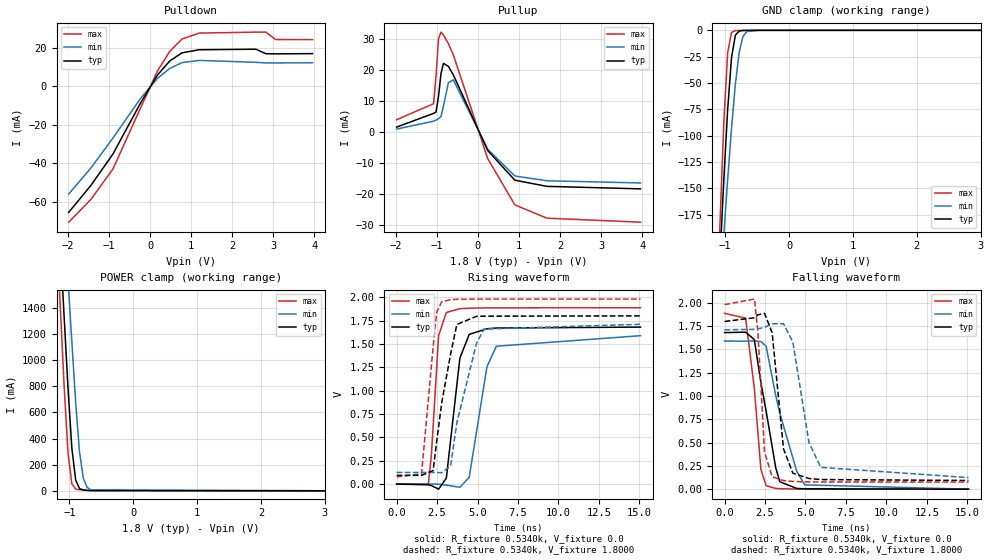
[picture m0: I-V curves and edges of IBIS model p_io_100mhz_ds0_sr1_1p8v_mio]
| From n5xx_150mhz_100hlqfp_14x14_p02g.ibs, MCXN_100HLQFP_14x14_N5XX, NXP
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[Model] p_io_100mhz_ds0_sr1_1p8v_mio
|   Model p_io_100mhz_ds0_sr1_1p8v_mio
| This model was characterised for following simulation conditions:
| External (pad) voltage:
|   - Typ: 1.8V,   - Min: 1.71V,   - Max: 1.98V
| Library cells for typ/min/max conditions are connected as defined below:
|  pad - External Pad
|  ipp_do_lv - Core Input
|  ipp_obe_lv - Output Buffer Enable
|  IOGC - NC
|  REFH3V3 - REFH3V3
|  REFL3V3 - REFL3V3
|  ZI - NC
|  abut_ncal_vddio[1] - vssio vddio vddio
|  abut_ncal_vddio[2] - vddio vddio vssio
|  abut_ncal_vddio[3] - vddio
|  abut_ncal_vddio[4] - vssio vddio vddio
|  abut_ncal_vddio[5] - vddio vddio vssio
|  abut_ncal_vddio[6] - vddio
|  abut_pcal_vddio[1] - vssio
|  abut_pcal_vddio[2] - vddio vssio vddio
|  abut_pcal_vddio[3] - vssio
|  abut_pcal_vddio[4] - vssio
|  abut_pcal_vddio[5] - vddio vssio vddio
|  abut_pcal_vddio[6] - vssio
|  ipp_do_1p8v - ipp_do_1p8v
|  ipp_dse_lv - 0
|  ipp_eftd_lv - NC
|  ipp_ina_mux_vddio - NC
|  ipp_ina_mux_vddio[0] - NC
|  ipp_ina_mux_vddio[1] - NC
|  ipp_ina_r0_vddio - NC
|  ipp_ina_r0a_vddio - NC
|  ipp_ina_r0b_vddio - NC
|  ipp_ina_r0c_vddio - NC
|  ipp_ina_r0d_vddio - NC
|  ipp_ina_r0e_vddio - NC
|  ipp_ina_r0f_vddio - NC
|  ipp_ina_r300_vddio - NC
|  ipp_ina_r300a_vddio - NC
|  ipp_ina_r300b_vddio - NC
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Model_type I/O
Polarity   Non-Inverting
Enable   Active-High
Vinl =   0.5400V
Vinh =   1.2600V
Vmeas =  0.9000V
Cref =   30.0000pF
Rref =   1.0000M
Vref =   1.8000V
C_comp   1.3623pF   1.2981pF   1.4425pF
|C_comp_pullup   0.7130pF   0.7388pF   0.6867pF
|C_comp_pulldown   0.5818pF   0.6364pF   0.5437pF
[Model Spec]
| variable   typ   min   max
Vinh   1.2600V   1.1970V   1.3860V
Vinl   0.5400V   0.5130V   0.5940V
[Temperature Range]   25.0000   0.1250k   -40.0000
[Voltage Range]   1.8000V   1.7100V   1.9800V
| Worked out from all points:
|   slope of the pulldown table from 0 to 0.27 V, typ, clamps not added: 32.1 ohm
|   slope of the pullup table from 0 to 0.27 V, typ, clamps not added: 40.8 ohm
|   GND clamp passes 1 mA (typ) near -0.79 V on its own axis
|   POWER clamp passes 1 mA (typ) near -0.56 V on its own axis
|   rising waveform, R_fixture 0.5340k, V_fixture 0.0: 20-80 % time 601ps typ, 817ps min, 376ps max; typ from 0 V to 1.68 V
|   rising waveform, R_fixture 0.5340k, V_fixture 1.8000: 20-80 % time 932ps typ, 1.21ns min, 574ps max; typ from 0.093 V to 1.8 V
|   falling waveform, R_fixture 0.5340k, V_fixture 0.0: 20-80 % time 990ps typ, 1.35ns min, 603ps max; typ from 1.68 V to 0 V
|   falling waveform, R_fixture 0.5340k, V_fixture 1.8000: 20-80 % time 546ps typ, 868ps min, 349ps max; typ from 1.8 V to 0.093 V
[Pulldown]
|Voltage   I(typ)   I(min)   I(max)
-1.98V    -65.51mA   -56mA      -70.63mA
-1.44V    -51.49mA   -42.44mA   -58.8mA
-900mV    -35.05mA   -26.74mA   -42.86mA
-240mV    -8.99mA    -6.551mA   -11.63mA
180mV     5.909mA    4.185mA    8.006mA
480mV     13.23mA    9.376mA    18.24mA
780mV     17.5mA     12.4mA     24.7mA
1.2V      19.11mA    13.55mA    27.78mA
2.58V     19.37mA    12.56mA    28.27mA
2.82V     17.04mA    12.25mA    28.29mA
3.06V     16.96mA    12.25mA    24.43mA
3.96V     17.09mA    12.34mA    24.37mA
[Pullup]
|Voltage   I(typ)   I(min)   I(max)
-1.98V    1.636mA    1mA        4.028mA
-1.08V    6.077mA    3.554mA    9.208mA
-1.02V    6.51mA     3.931mA    18.29mA
-960mV    11.61mA    4.325mA    30.19mA
-900mV    18.94mA    5.078mA    32.34mA
-840mV    22.24mA    8.431mA    31.43mA
-720mV    21.27mA    15.96mA    28.62mA
-600mV    18.54mA    16.92mA    25.03mA
240mV     -5.971mA   -5.553mA   -8.582mA
900mV     -15.52mA   -14.17mA   -23.51mA
1.68V     -17.51mA   -15.71mA   -27.79mA
3.96V     -18.32mA   -16.41mA   -29.09mA
[GND_clamp]
|Voltage   I(typ)   I(min)   I(max)
-1.98V    -1.537A    -1.19A     -2.019A
-1.14V    -294.9mA   -305.1mA   -290.2mA
-1.08V    -215.7mA   -248.6mA   -182.3mA
-1.02V    -141mA     -193.8mA   -86.65mA
-960mV    -74.83mA   -141.5mA   -21.03mA
-900mV    -25.88mA   -93.07mA   -2.012mA
-840mV    -4.609mA   -51.31mA   -311uA
-780mV    -637.2uA   -20.91mA   -159.7uA
-720mV    -151.2uA   -5.716mA   -109.9uA
-660mV    -72.83uA   -1.219mA   -73.5uA
-480mV    -11.41uA   -25.38uA   -9.438uA
3.96V     0A         0A         0A
[POWER_clamp]
|Voltage   I(typ)   I(min)   I(max)
-1.98V    9.576A     9.287A     10.07A
-1.2V     2.409A     3.037A     2.006A
-1.14V    1.864A     2.56A      1.395A
-1.08V    1.321A     2.084A     791mA
-1.02V    782.7mA    1.609A     287.5mA
-960mV    325.1mA    1.137A     54.65mA
-900mV    82.58mA    671mA      14.08mA
-840mV    18.02mA    296.8mA    8.778mA
-780mV    6.907mA    95.14mA    6.356mA
-720mV    4.149mA    25.95mA    4.381mA
-660mV    2.634mA    7.923mA    2.736mA
3.96V     0A         0A         0A
[Ramp]
| variable   typ   min   max
dV/dt_r  1.0081/0.6014n   0.9529/0.8166n   1.1320/0.3762n
dV/dt_f  1.0242/0.5458n   0.9513/0.8676n   1.1422/0.3495n
R_load = 0.5340k
[Rising Waveform]
R_fixture= 0.5340k
V_fixture= 0.0
V_fixture_min= 0.0
V_fixture_max= 0.0
|time   V(typ)   V(min)   V(max)
0s        464.8pV    171.6nV    14.01pV
1.962ns   -8.088mV   270.7uV    3.648mV
2.148ns   -15.92mV   560.3uV    309.5mV
2.593ns   -54.73mV   -902.1uV   1.59V
3.071ns   63.74mV    -11.49mV   1.836V
3.909ns   1.349V     -35.2mV    1.877V
4.486ns   1.602V     73.79mV    1.882V
5.58ns    1.662V     1.255V     1.886V
6.16ns    1.67V      1.475V     1.886V
15.07ns   1.68V      1.588V     1.887V
[Rising Waveform]
R_fixture= 0.5340k
V_fixture= 1.8000
V_fixture_min= 1.7100
V_fixture_max= 1.9800
|time   V(typ)   V(min)   V(max)
0s        92.99mV    124mV      76.26mV
1.542ns   93.33mV    124mV      109.5mV
2.256ns   144.3mV    124.2mV    1.471V
2.473ns   452.9mV    123.3mV    1.841V
2.782ns   866.6mV    121.3mV    1.95V
3.336ns   1.392V     193.3mV    1.974V
3.721ns   1.708V     656.6mV    1.977V
4.931ns   1.795V     1.504V     1.98V
5.397ns   1.797V     1.659V     1.98V
15.07ns   1.8V       1.71V      1.98V
[Falling Waveform]
R_fixture= 0.5340k
V_fixture= 0.0
V_fixture_min= 0.0
V_fixture_max= 0.0
|time   V(typ)   V(min)   V(max)
0s        1.68V      1.589V     1.887V
1.302ns   1.685V     1.588V     1.835V
1.839ns   1.605V     1.592V     1.083V
2.245ns   1.145V     1.584V     213.2mV
2.57ns    837mV      1.534V     37.51mV
3.164ns   228.2mV    1.003V     7.745mV
3.415ns   79.61mV    815.6mV    4.796mV
4.469ns   7.465mV    187.1mV    993.8uV
4.953ns   3.898mV    46.45mV    566.9uV
15.07ns   36.14uV    86.85uV    22.42uV
[Falling Waveform]
R_fixture= 0.5340k
V_fixture= 1.8000
V_fixture_min= 1.7100
V_fixture_max= 1.9800
|time   V(typ)   V(min)   V(max)
0s        1.8V       1.71V      1.98V
1.851ns   1.839V     1.715V     2.04V
2.062ns   1.871V     1.721V     1.683V
2.472ns   1.886V     1.736V     397.2mV
2.941ns   1.679V     1.775V     133.3mV
3.642ns   432.9mV    1.775V     91.6mV
4.221ns   171.9mV    1.58V      82.81mV
5.214ns   114.5mV    500.7mV    78.24mV
5.947ns   103.2mV    233.6mV    77.18mV
15.07ns   93.05mV    124.5mV    76.29mV
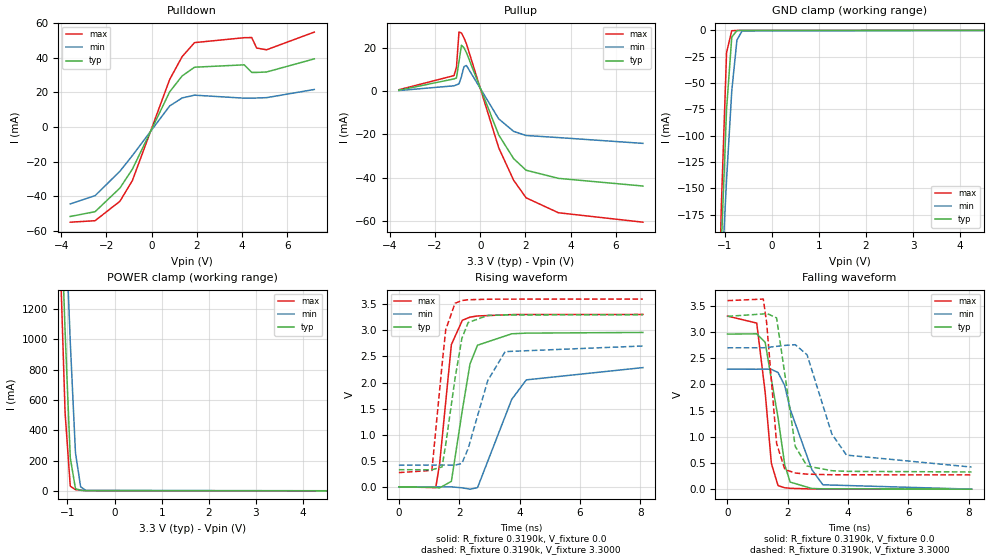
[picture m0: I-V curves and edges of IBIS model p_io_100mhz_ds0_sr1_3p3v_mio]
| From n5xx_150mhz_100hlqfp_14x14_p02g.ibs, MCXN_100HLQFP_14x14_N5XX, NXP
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[Model] p_io_100mhz_ds0_sr1_3p3v_mio
|   Model p_io_100mhz_ds0_sr1_3p3v_mio
| This model was characterised for following simulation conditions:
| External (pad) voltage:
|   - Typ: 3.3V,   - Min: 2.7V,   - Max: 3.6V
| Library cells for typ/min/max conditions are connected as defined below:
|  pad - External Pad
|  ipp_do_lv - Core Input
|  ipp_obe_lv - Output Buffer Enable
|  IOGC - NC
|  REFH3V3 - REFH3V3
|  REFL3V3 - REFL3V3
|  ZI - NC
|  abut_ncal_vddio[1] - vddio
|  abut_ncal_vddio[2] - vddio
|  abut_ncal_vddio[3] - vssio
|  abut_ncal_vddio[4] - vddio
|  abut_ncal_vddio[5] - vddio
|  abut_ncal_vddio[6] - vssio
|  abut_pcal_vddio[1] - vssio
|  abut_pcal_vddio[2] - vssio
|  abut_pcal_vddio[3] - vddio
|  abut_pcal_vddio[4] - vssio
|  abut_pcal_vddio[5] - vssio
|  abut_pcal_vddio[6] - vddio
|  ipp_do_1p8v - ipp_do_1p8v
|  ipp_dse_lv - 0
|  ipp_eftd_lv - NC
|  ipp_ina_mux_vddio - NC
|  ipp_ina_mux_vddio[0] - NC
|  ipp_ina_mux_vddio[1] - NC
|  ipp_ina_r0_vddio - NC
|  ipp_ina_r0a_vddio - NC
|  ipp_ina_r0b_vddio - NC
|  ipp_ina_r0c_vddio - NC
|  ipp_ina_r0d_vddio - NC
|  ipp_ina_r0e_vddio - NC
|  ipp_ina_r0f_vddio - NC
|  ipp_ina_r300_vddio - NC
|  ipp_ina_r300a_vddio - NC
|  ipp_ina_r300b_vddio - NC
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Model_type I/O
Polarity   Non-Inverting
Enable   Active-High
Vinl =   0.9900V
Vinh =   2.3100V
Vmeas =  1.6500V
Cref =   30.0000pF
Rref =   1.0000M
Vref =   3.3000V
C_comp   1.3234pF   1.2639pF   1.4076pF
|C_comp_pullup   0.6739pF   0.7056pF   0.6520pF
|C_comp_pulldown   0.5815pF   0.6343pF   0.5433pF
[Model Spec]
| variable   typ   min   max
Vinh   2.3100V   1.8900V   2.5200V
Vinl   0.9900V   0.8100V   1.0800V
[Temperature Range]   25.0000   0.1250k   -40.0000
[Voltage Range]   3.3000V   2.7000V   3.6000V
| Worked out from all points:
|   slope of the pulldown table from 0 to 0.495 V, typ, clamps not added: 36.6 ohm
|   slope of the pullup table from 0 to 0.495 V, typ, clamps not added: 37.7 ohm
|   GND clamp passes 1 mA (typ) near -0.75 V on its own axis
|   POWER clamp passes 1 mA (typ) near -0.55 V on its own axis
|   rising waveform, R_fixture 0.3190k, V_fixture 0.0: 20-80 % time 463ps typ, 831ps min, 328ps max; typ from 0 V to 2.96 V
|   rising waveform, R_fixture 0.3190k, V_fixture 3.3000: 20-80 % time 462ps typ, 748ps min, 321ps max; typ from 0.328 V to 3.3 V
|   falling waveform, R_fixture 0.3190k, V_fixture 0.0: 20-80 % time 473ps typ, 774ps min, 323ps max; typ from 2.96 V to 0 V
|   falling waveform, R_fixture 0.3190k, V_fixture 3.3000: 20-80 % time 407ps typ, 768ps min, 280ps max; typ from 3.3 V to 0.329 V
[Pulldown]
|Voltage   I(typ)   I(min)   I(max)
-3.6V     -51.52mA   -44.27mA   -54.81mA
-2.5V     -48.75mA   -39.51mA   -53.96mA
-1.4V     -35.12mA   -25.45mA   -42.73mA
-850mV    -24.27mA   -16.41mA   -30.84mA
800mV     20.29mA    12.16mA    27.43mA
1.35V     29.44mA    16.78mA    40.57mA
1.9V      34.5mA     18.39mA    48.67mA
4.1V      35.87mA    16.66mA    51.51mA
4.43V     31.5mA     16.69mA    51.59mA
4.65V     31.5mA     16.75mA    45.53mA
5.09V     31.75mA    16.96mA    44.55mA
7.2V      39.3mA     21.67mA    54.74mA
[Pullup]
|Voltage   I(typ)   I(min)   I(max)
-3.6V     391.8uA    234.9uA    605.7uA
-1.16V    5.604mA    2.419mA    7.14mA
-1.05V    6.055mA    2.871mA    11mA
-940mV    13.56mA    3.339mA    27.24mA
-830mV    21.15mA    6.685mA    26.82mA
-720mV    20.05mA    11.26mA    24.61mA
-610mV    17.74mA    11.81mA    21.86mA
820mV     -20.29mA   -12.86mA   -26.23mA
1.48V     -31.23mA   -18.63mA   -41.23mA
2.03V     -36.57mA   -20.53mA   -49.31mA
3.46V     -40.33mA   -21.49mA   -56.22mA
7.2V      -43.87mA   -24.17mA   -60.58mA
[GND_clamp]
|Voltage   I(typ)   I(min)   I(max)
-3.6V     -4.134A    -3.035A    -5.609A
-1.18V    -349.4mA   -343.6mA   -365.7mA
-1.07V    -202.9mA   -239.3mA   -165.2mA
-960mV    -74.83mA   -141.5mA   -21.03mA
-850mV    -6.389mA   -57.64mA   -383.3uA
-740mV    -222.1uA   -9.174mA   -124.1uA
-630mV    -55.93uA   -558.9uA   -58.07uA
7.2V      0A         0A         0A
[POWER_clamp]
|Voltage   I(typ)   I(min)   I(max)
-3.6V     24.54A     22.33A     26.93A
-1.16V    2.046A     2.721A     1.599A
-1.05V    1.052A     1.847A     514.4mA
-940mV    218.6mA    981.8mA    31.16mA
-830mV    15.1mA     252.4mA    8.462mA
-720mV    4.281mA    26.81mA    4.453mA
-610mV    1.717mA    3.626mA    1.66mA
7.2V      0A         0A         0A
[Ramp]
| variable   typ   min   max
dV/dt_r  1.7762/0.4628n   1.3718/0.8312n   1.9832/0.3278n
dV/dt_f  1.7828/0.4073n   1.3669/0.7682n   1.9962/0.2798n
R_load = 0.3190k
[Rising Waveform]
R_fixture= 0.3190k
V_fixture= 0.0
V_fixture_min= 0.0
V_fixture_max= 0.0
|time   V(typ)   V(min)   V(max)
0s        2.902nV    250nV      9.459nV
1.223ns   -10.89mV   -6.243uV   -14.66mV
1.35ns    -21.51mV   358.4uV    434mV
1.741ns   105.7mV    -947.7uV   2.727V
2.104ns   1.47V      -19.17mV   3.193V
2.36ns    2.361V     -44.72mV   3.254V
2.608ns   2.715V     -14.73mV   3.276V
3.741ns   2.934V     1.676V     3.302V
4.225ns   2.947V     2.051V     3.304V
8.09ns    2.96V      2.286V     3.305V
[Rising Waveform]
R_fixture= 0.3190k
V_fixture= 3.3000
V_fixture_min= 2.7000
V_fixture_max= 3.6000
|time   V(typ)   V(min)   V(max)
0s        328.4mV    417.4mV    273mV
1.095ns   327.1mV    417.3mV    314.8mV
1.431ns   382.2mV    418mV      2.335V
1.554ns   814mV      418.4mV    3.012V
1.861ns   2.073V     414.8mV    3.519V
2.089ns   2.846V     449mV      3.572V
2.297ns   3.149V     734.6mV    3.587V
2.946ns   3.286V     2.037V     3.597V
3.524ns   3.295V     2.593V     3.599V
8.09ns    3.3V       2.7V       3.6V
[Falling Waveform]
R_fixture= 0.3190k
V_fixture= 0.0
V_fixture_min= 0.0
V_fixture_max= 0.0
|time   V(typ)   V(min)   V(max)
0s        2.961V     2.292V     3.305V
969.2ps   2.966V     2.29V      3.171V
1.25ns    2.803V     2.294V     1.843V
1.455ns   2.098V     2.287V     491.1mV
1.675ns   1.368V     2.228V     68.76mV
1.899ns   460.9mV    1.976V     27.06mV
2.078ns   134.9mV    1.527V     16.67mV
2.798ns   12.69mV    370.7mV    3.526mV
3.163ns   6.586mV    83.31mV    1.82mV
8.09ns    98.44uV    359.7uV    57.86uV
[Falling Waveform]
R_fixture= 0.3190k
V_fixture= 3.3000
V_fixture_min= 2.7000
V_fixture_max= 3.6000
|time   V(typ)   V(min)   V(max)
0s        3.3V       2.7V       3.6V
1.188ns   3.346V     2.7V       3.63V
1.3ns     3.357V     2.706V     3.166V
1.628ns   3.27V      2.727V     873.3mV
1.902ns   2.192V     2.745V     375.1mV
2.245ns   817.2mV    2.759V     308.5mV
2.638ns   442.1mV    2.567V     286.7mV
3.46ns    352.5mV    1.052V     275.7mV
3.946ns   340mV      650.1mV    274.3mV
8.09ns    328.7mV    421.8mV    273.1mV
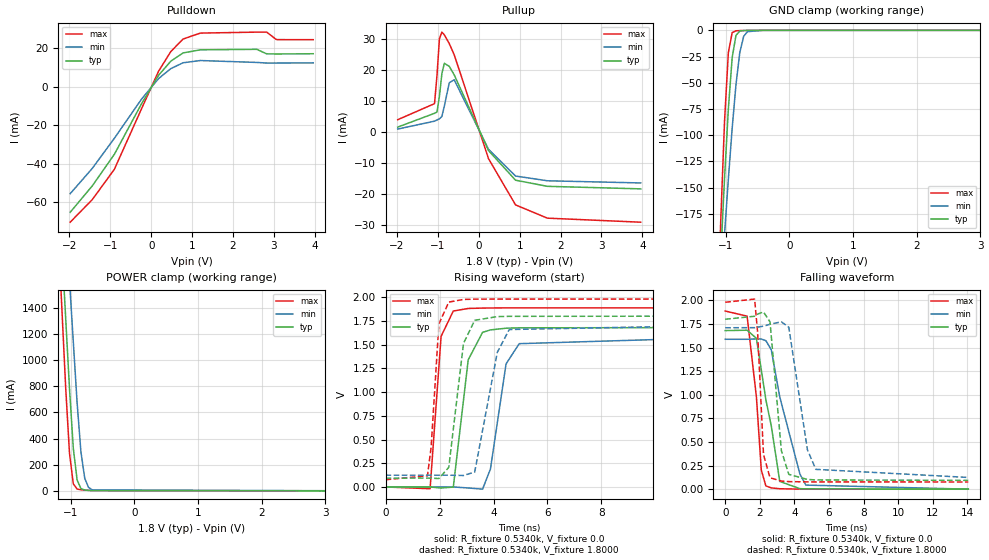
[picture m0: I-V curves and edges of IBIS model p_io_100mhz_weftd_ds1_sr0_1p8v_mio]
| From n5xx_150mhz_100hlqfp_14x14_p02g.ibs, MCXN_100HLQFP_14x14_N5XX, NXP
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[Model] p_io_100mhz_weftd_ds1_sr0_1p8v_mio
|   Model p_io_100mhz_weftd_ds1_sr0_1p8v_mio
| This model was characterised for following simulation conditions:
| External (pad) voltage:
|   - Typ: 1.8V,   - Min: 1.71V,   - Max: 1.98V
| Library cells for typ/min/max conditions are connected as defined below:
|  pad - External Pad
|  ipp_do_lv - Core Input
|  ipp_obe_lv - Output Buffer Enable
|  IOGC - NC
|  REFH3V3 - REFH3V3
|  REFL3V3 - REFL3V3
|  ZI - NC
|  abut_ncal_vddio[1] - vssio vddio vddio
|  abut_ncal_vddio[2] - vddio vddio vssio
|  abut_ncal_vddio[3] - vddio
|  abut_ncal_vddio[4] - vssio vddio vddio
|  abut_ncal_vddio[5] - vddio vddio vssio
|  abut_ncal_vddio[6] - vddio
|  abut_pcal_vddio[1] - vssio
|  abut_pcal_vddio[2] - vddio vssio vddio
|  abut_pcal_vddio[3] - vssio
|  abut_pcal_vddio[4] - vssio
|  abut_pcal_vddio[5] - vddio vssio vddio
|  abut_pcal_vddio[6] - vssio
|  ipp_do_1p8v - ipp_do_1p8v
|  ipp_dse_lv - vdd_lv
|  ipp_eftd_lv - NC
|  ipp_ina_mux_vddio - NC
|  ipp_ina_mux_vddio[0] - NC
|  ipp_ina_mux_vddio[1] - NC
|  ipp_ina_r0_vddio - NC
|  ipp_ina_r0a_vddio - NC
|  ipp_ina_r0b_vddio - NC
|  ipp_ina_r0c_vddio - NC
|  ipp_ina_r0d_vddio - NC
|  ipp_ina_r0e_vddio - NC
|  ipp_ina_r0f_vddio - NC
|  ipp_ina_r300_vddio - NC
|  ipp_ina_r300a_vddio - NC
|  ipp_ina_r300b_vddio - NC
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Model_type I/O
Polarity   Non-Inverting
Enable   Active-High
Vinl =   0.5400V
Vinh =   1.2600V
Vmeas =  0.9000V
Cref =   30.0000pF
Rref =   1.0000M
Vref =   1.8000V
C_comp   1.4209pF   1.3571pF   1.5007pF
|C_comp_pullup   0.7321pF   0.7588pF   0.7062pF
|C_comp_pulldown   0.6105pF   0.6618pF   0.5700pF
[Model Spec]
| variable   typ   min   max
Vinh   1.2600V   1.1970V   1.3860V
Vinl   0.5400V   0.5130V   0.5940V
[Temperature Range]   25.0000   0.1250k   -40.0000
[Voltage Range]   1.8000V   1.7100V   1.9800V
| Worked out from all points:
|   slope of the pulldown table from 0 to 0.27 V, typ, clamps not added: 32.1 ohm
|   slope of the pullup table from 0 to 0.27 V, typ, clamps not added: 40.9 ohm
|   GND clamp passes 1 mA (typ) near -0.78 V on its own axis
|   POWER clamp passes 1 mA (typ) near -0.56 V on its own axis
|   rising waveform, R_fixture 0.5340k, V_fixture 0.0: 20-80 % time 375ps typ, 478ps min, 240ps max; typ from 0 V to 1.68 V
|   rising waveform, R_fixture 0.5340k, V_fixture 1.8000: 20-80 % time 383ps typ, 516ps min, 235ps max; typ from 0.093 V to 1.8 V
|   falling waveform, R_fixture 0.5340k, V_fixture 0.0: 20-80 % time 874ps typ, 1.25ns min, 521ps max; typ from 1.68 V to 0 V
|   falling waveform, R_fixture 0.5340k, V_fixture 1.8000: 20-80 % time 429ps typ, 647ps min, 286ps max; typ from 1.8 V to 0.093 V
[Pulldown]
|Voltage   I(typ)   I(min)   I(max)
-1.98V    -65.1mA    -55.47mA   -70.23mA
-1.44V    -51.41mA   -42.35mA   -58.53mA
-900mV    -35.03mA   -26.74mA   -42.81mA
-240mV    -8.989mA   -6.551mA   -11.62mA
180mV     5.908mA    4.185mA    8mA
480mV     13.23mA    9.376mA    18.23mA
780mV     17.5mA     12.4mA     24.7mA
1.2V      19.1mA     13.55mA    27.77mA
2.58V     19.36mA    12.56mA    28.27mA
2.82V     17.02mA    12.25mA    28.29mA
3.06V     16.94mA    12.25mA    24.4mA
3.96V     17.07mA    12.34mA    24.35mA
[Pullup]
|Voltage   I(typ)   I(min)   I(max)
-1.98V    1.629mA    999.6uA    4.015mA
-1.08V    6.088mA    3.551mA    9.212mA
-1.02V    6.511mA    3.928mA    18.3mA
-960mV    11.61mA    4.321mA    30.17mA
-900mV    18.93mA    5.074mA    32.31mA
-840mV    22.23mA    8.425mA    31.4mA
-720mV    21.25mA    15.95mA    28.6mA
-600mV    18.53mA    16.91mA    25.01mA
240mV     -5.966mA   -5.551mA   -8.574mA
900mV     -15.51mA   -14.17mA   -23.49mA
1.68V     -17.49mA   -15.7mA    -27.77mA
3.96V     -18.31mA   -16.4mA    -29.07mA
[GND_clamp]
|Voltage   I(typ)   I(min)   I(max)
-1.98V    -1.543A    -1.201A    -2.023A
-1.14V    -295.8mA   -306.3mA   -290.9mA
-1.08V    -216.4mA   -249.6mA   -182.7mA
-1.02V    -141.5mA   -194.6mA   -86.96mA
-960mV    -75.17mA   -142.1mA   -21.27mA
-900mV    -26.1mA    -93.57mA   -2.203mA
-840mV    -4.74mA    -51.67mA   -459.1uA
-780mV    -724.6uA   -21.14mA   -268.2uA
-720mV    -210.5uA   -5.843mA   -184.1uA
-660mV    -110.6uA   -1.28mA    -119.5uA
-420mV    -5.355uA   -12.87uA   -3.609uA
3.96V     0A         0A         0A
[POWER_clamp]
|Voltage   I(typ)   I(min)   I(max)
-1.98V    9.578A     9.289A     10.07A
-1.2V     2.41A      3.038A     2.007A
-1.14V    1.864A     2.561A     1.396A
-1.08V    1.321A     2.084A     791.3mA
-1.02V    783mA      1.609A     287.7mA
-960mV    325.3mA    1.137A     54.76mA
-900mV    82.69mA    671.2mA    14.16mA
-840mV    18.08mA    297mA      8.834mA
-780mV    6.944mA    95.27mA    6.398mA
-720mV    4.174mA    26.01mA    4.41mA
-660mV    2.65mA     7.951mA    2.754mA
3.96V     0A         0A         0A
[Ramp]
| variable   typ   min   max
dV/dt_r  1.0081/0.3746n   0.9531/0.4784n   1.1320/0.2401n
dV/dt_f  1.0242/0.4289n   0.9515/0.6474n   1.1422/0.2863n
R_load = 0.5340k
[Rising Waveform]
R_fixture= 0.5340k
V_fixture= 0.0
V_fixture_min= 0.0
V_fixture_max= 0.0
|time   V(typ)   V(min)   V(max)
0s        469.4pV    172.1nV    14.64pV
1.65ns    132.1uV    -84.45uV   -18.72mV
2.058ns   -10.99mV   292.2uV    1.587V
2.51ns    -1.382mV   -42.26uV   1.854V
3.063ns   1.34V      -10.44mV   1.881V
3.595ns   1.629V     -23.25mV   1.885V
3.887ns   1.655V     189.7mV    1.886V
4.465ns   1.673V     1.297V     1.887V
4.953ns   1.677V     1.51V      1.887V
14.06ns   1.68V      1.588V     1.887V
[Rising Waveform]
R_fixture= 0.5340k
V_fixture= 1.8000
V_fixture_min= 1.7100
V_fixture_max= 1.9800
|time   V(typ)   V(min)   V(max)
0s        93mV       124mV      76.32mV
1.553ns   93.25mV    123.9mV    117.7mV
1.688ns   92.31mV    123.9mV    416.9mV
1.976ns   88.86mV    124.2mV    1.718V
2.343ns   207.3mV    124mV      1.948V
2.888ns   1.513V     121mV      1.976V
3.303ns   1.756V     157mV      1.979V
4.141ns   1.795V     1.419V     1.98V
4.583ns   1.798V     1.659V     1.98V
14.06ns   1.8V       1.71V      1.98V
[Falling Waveform]
R_fixture= 0.5340k
V_fixture= 0.0
V_fixture_min= 0.0
V_fixture_max= 0.0
|time   V(typ)   V(min)   V(max)
0s        1.68V      1.588V     1.887V
1.266ns   1.684V     1.588V     1.833V
1.804ns   1.598V     1.592V     977.9mV
2.087ns   1.264V     1.591V     202mV
2.351ns   948.2mV    1.573V     34.38mV
2.665ns   669.8mV    1.476V     13.4mV
3.155ns   81.83mV    976.7mV    4.503mV
4.319ns   5.338mV    160.8mV    586uV
4.662ns   3.286mV    43.18mV    371.7uV
14.06ns   39.62uV    75.35uV    25uV
[Falling Waveform]
R_fixture= 0.5340k
V_fixture= 1.8000
V_fixture_min= 1.7100
V_fixture_max= 1.9800
|time   V(typ)   V(min)   V(max)
0s        1.8V       1.71V      1.98V
1.7ns     1.832V     1.711V     2.014V
1.872ns   1.855V     1.716V     1.667V
2.215ns   1.877V     1.727V     365.9mV
2.591ns   1.772V     1.747V     120.9mV
3.247ns   409.7mV    1.773V     85.73mV
3.677ns   157mV      1.716V     80.23mV
4.755ns   102.9mV    417mV      76.96mV
5.242ns   97.84mV    209.9mV    76.68mV
14.06ns   93.05mV    124.1mV    76.35mV
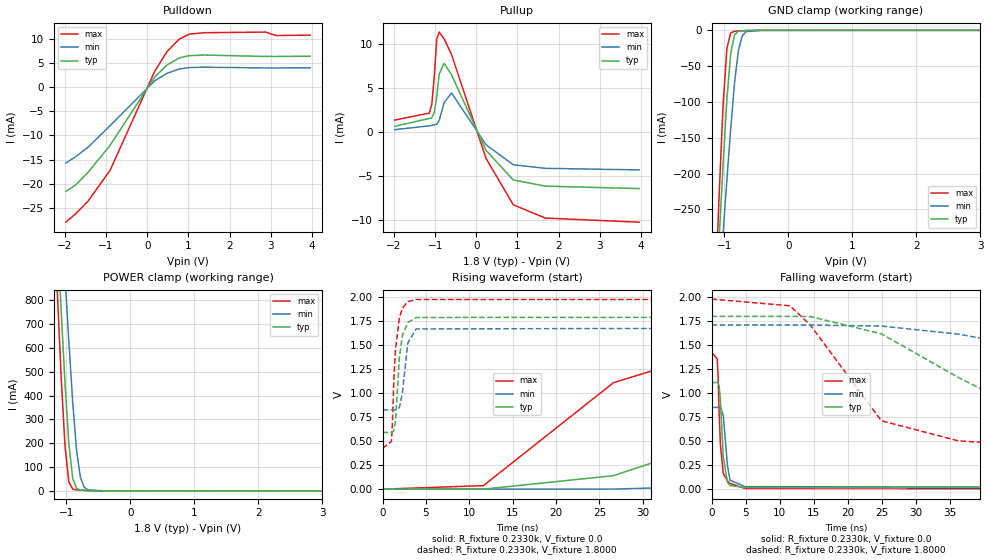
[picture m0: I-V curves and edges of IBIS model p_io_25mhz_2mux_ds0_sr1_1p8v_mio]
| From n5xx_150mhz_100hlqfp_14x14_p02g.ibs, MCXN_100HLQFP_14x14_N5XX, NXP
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[Model] p_io_25mhz_2mux_ds0_sr1_1p8v_mio
|   Model p_io_25mhz_2mux_ds0_sr1_1p8v_mio
| This model was characterised for following simulation conditions:
| External (pad) voltage:
|   - Typ: 1.8V,   - Min: 1.71V,   - Max: 1.98V
| Library cells for typ/min/max conditions are connected as defined below:
|  pad - External Pad
|  ipp_do_lv - Core Input
|  ipp_obe_lv - Output Buffer Enable
|  IOGC - NC
|  REFH3V3 - REFH3V3
|  REFL3V3 - REFL3V3
|  ZI - NC
|  abut_ncal_vddio[1] - vssio vddio vddio
|  abut_ncal_vddio[2] - vddio vddio vssio
|  abut_ncal_vddio[3] - vddio
|  abut_ncal_vddio[4] - vssio vddio vddio
|  abut_ncal_vddio[5] - vddio vddio vssio
|  abut_ncal_vddio[6] - vddio
|  abut_pcal_vddio[1] - vssio
|  abut_pcal_vddio[2] - vddio vssio vddio
|  abut_pcal_vddio[3] - vssio
|  abut_pcal_vddio[4] - vssio
|  abut_pcal_vddio[5] - vddio vssio vddio
|  abut_pcal_vddio[6] - vssio
|  ipp_do_1p8v - ipp_do_1p8v
|  ipp_dse_lv - 0
|  ipp_eftd_lv - NC
|  ipp_ina_mux_vddio - NC
|  ipp_ina_mux_vddio[0] - NC
|  ipp_ina_mux_vddio[1] - NC
|  ipp_ina_r0_vddio - NC
|  ipp_ina_r0a_vddio - NC
|  ipp_ina_r0b_vddio - NC
|  ipp_ina_r0c_vddio - NC
|  ipp_ina_r0d_vddio - NC
|  ipp_ina_r0e_vddio - NC
|  ipp_ina_r0f_vddio - NC
|  ipp_ina_r300_vddio - NC
|  ipp_ina_r300a_vddio - NC
|  ipp_ina_r300b_vddio - NC
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Model_type I/O
Polarity   Non-Inverting
Enable   Active-High
Vinl =   0.5400V
Vinh =   1.2600V
Vmeas =  0.9000V
Cref =   30.0000pF
Rref =   1.0000M
Vref =   1.8000V
C_comp   1.3067pF   1.2540pF   1.3694pF
|C_comp_pullup   0.5689pF   0.5980pF   0.5421pF
|C_comp_pulldown   0.6636pF   0.6953pF   0.6387pF
[Model Spec]
| variable   typ   min   max
Vinh   1.2600V   1.1970V   1.3860V
Vinl   0.5400V   0.5130V   0.5940V
[Temperature Range]   25.0000   0.1250k   -40.0000
[Voltage Range]   1.8000V   1.7100V   1.9800V
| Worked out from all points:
|   slope of the pulldown table from 0 to 0.27 V, typ, clamps not added: 93.6 ohm
|   slope of the pullup table from 0 to 0.27 V, typ, clamps not added: 116 ohm
|   GND clamp passes 1 mA (typ) near -0.75 V on its own axis
|   POWER clamp passes 1 mA (typ) near -0.63 V on its own axis
|   rising waveform, R_fixture 0.2330k, V_fixture 0.0: 20-80 % time 23ns typ, 43.3ns min, 11.5ns max; typ from 0 V to 1.11 V
|   rising waveform, R_fixture 0.2330k, V_fixture 1.8000: 20-80 % time 591ps typ, 648ps min, 565ps max; typ from 0.59 V to 1.8 V
|   falling waveform, R_fixture 0.2330k, V_fixture 0.0: 20-80 % time 550ps typ, 630ps min, 505ps max; typ from 1.11 V to 0 V
|   falling waveform, R_fixture 0.2330k, V_fixture 1.8000: 20-80 % time 19.4ns typ, 38ns min, 9.57ns max; typ from 1.8 V to 0.591 V
[Pulldown]
|Voltage   I(typ)   I(min)   I(max)
-1.98V    -21.59mA   -15.72mA   -27.94mA
-1.74V    -20.25mA   -14.42mA   -26.22mA
-1.44V    -17.66mA   -12.45mA   -23.61mA
-900mV    -12.03mA   -7.992mA   -17.18mA
180mV     2.026mA    1.252mA    3.209mA
480mV     4.533mA    2.805mA    7.304mA
780mV     5.999mA    3.712mA    9.89mA
1.02V     6.468mA    4.005mA    10.9mA
1.38V     6.587mA    4.078mA    11.2mA
2.88V     6.293mA    3.922mA    11.33mA
3.12V     6.289mA    3.924mA    10.62mA
3.96V     6.35mA     3.959mA    10.7mA
[Pullup]
|Voltage   I(typ)   I(min)   I(max)
-1.98V    644.9uA    266.3uA    1.361mA
-1.14V    1.542mA    707.2uA    2.153mA
-1.08V    1.604mA    764.5uA    3.171mA
-1.02V    2.234mA    824.1uA    6.358mA
-960mV    4.021mA    885.3uA    10.59mA
-900mV    6.607mA    1.315mA    11.37mA
-780mV    7.807mA    3.354mA    10.59mA
-600mV    6.505mA    4.443mA    8.805mA
240mV     -2.097mA   -1.459mA   -3.022mA
900mV     -5.454mA   -3.726mA   -8.28mA
1.68V     -6.156mA   -4.132mA   -9.795mA
3.96V     -6.438mA   -4.31mA    -10.26mA
[GND_clamp]
|Voltage   I(typ)   I(min)   I(max)
-1.98V    -2A        -1.65A     -2.499A
-1.14V    -394mA     -441.5mA   -363.8mA
-1.08V    -288.3mA   -361.7mA   -226.5mA
-1.02V    -187.2mA   -283.6mA   -103.8mA
-960mV    -95.65mA   -208mA     -24.73mA
-900mV    -31.48mA   -136.2mA   -3.446mA
-840mV    -6.013mA   -72.18mA   -1.335mA
-780mV    -1.302mA   -27.91mA   -907.3uA
-720mV    -579.6uA   -7.635mA   -620.4uA
-660mV    -347.7uA   -1.81mA    -390uA
-420mV    -12.74uA   -30.23uA   -7.287uA
3.96V     0A         0A         0A
[POWER_clamp]
|Voltage   I(typ)   I(min)   I(max)
-1.98V    5.618A     5.349A     6.084A
-1.14V    1.071A     1.443A     829.6mA
-1.08V    754.2mA    1.168A     476.4mA
-1.02V    449mA      895.6mA    184.6mA
-960mV    195.8mA    625.5mA    36.76mA
-900mV    52.43mA    371.1mA    7.779mA
-840mV    10.73mA    170.2mA    4.41mA
-780mV    3.609mA    56.22mA    3.161mA
-720mV    2.066mA    15.04mA    2.177mA
-660mV    1.299mA    4.297mA    1.362mA
-360mV    4.834uA    27.3uA     1.2uA
3.96V     0A         0A         0A
[Ramp]
| variable   typ   min   max
dV/dt_r  0.6658/22.9565n   0.5082/43.3348n   0.8537/11.4911n
dV/dt_f  0.7256/19.4260n   0.5286/37.9905n   0.9328/9.5683n
R_load = 0.2330k
[Rising Waveform]
R_fixture= 0.2330k
V_fixture= 0.0
V_fixture_min= 0.0
V_fixture_max= 0.0
|time   V(typ)   V(min)   V(max)
0s        586.1pV    202.5nV    16.24pV
11.63ns   -35.35uV   -15.81uV   36.92mV
26.64ns   140.8mV    873.7uV    1.11V
32.3ns    310.5mV    15.68mV    1.266V
41.04ns   607mV      74.15mV    1.351V
50.05ns   847.8mV    173.6mV    1.387V
60.24ns   971.3mV    312.1mV    1.406V
81.69ns   1.062V     589.4mV    1.419V
102.2ns   1.09V      723mV      1.422V
225.6ns   1.11V      847mV      1.423V
[Rising Waveform]
R_fixture= 0.2330k
V_fixture= 1.8000
V_fixture_min= 1.7100
V_fixture_max= 1.9800
|time   V(typ)   V(min)   V(max)
0s        590.5mV    825.5mV    425.3mV
1.01ns    590.4mV    825.6mV    494.8mV
1.102ns   590.6mV    825.6mV    601.6mV
1.299ns   611.4mV    825.6mV    1.132V
1.49ns    698.1mV    825.4mV    1.452V
1.939ns   1.367V     848.1mV    1.784V
2.292ns   1.602V     1.004V     1.886V
2.911ns   1.734V     1.522V     1.954V
3.875ns   1.788V     1.669V     1.975V
225.6ns   1.8V       1.71V      1.98V
[Falling Waveform]
R_fixture= 0.2330k
V_fixture= 0.0
V_fixture_min= 0.0
V_fixture_max= 0.0
|time   V(typ)   V(min)   V(max)
0s        1.11V      851.6mV    1.423V
825.5ps   1.111V     851.6mV    1.358V
946.3ps   1.109V     851.5mV    1.194V
1.109ns   1.074V     852.1mV    804mV
1.295ns   926.3mV    853.6mV    466.3mV
1.718ns   336mV      768.2mV    163.1mV
2.333ns   71.08mV    246.4mV    85.79mV
2.711ns   37.71mV    93.38mV    59.86mV
4.934ns   17.68mV    26.16mV    6.154mV
225.6ns   173.9nV    2.824uV    36.08nV
[Falling Waveform]
R_fixture= 0.2330k
V_fixture= 1.8000
V_fixture_min= 1.7100
V_fixture_max= 1.9800
|time   V(typ)   V(min)   V(max)
0s        1.8V       1.71V      1.98V
11.51ns   1.8V       1.71V      1.91V
14.49ns   1.798V     1.71V      1.71V
24.92ns   1.618V     1.699V     712.7mV
36.2ns    1.165V     1.615V     503.5mV
44.44ns   867.9mV    1.509V     466mV
52.67ns   744.5mV    1.377V     448.1mV
70.6ns    651.2mV    1.094V     432.4mV
91.93ns   614.3mV    947.5mV    427.2mV
225.6ns   590.6mV    828.9mV    425.3mV
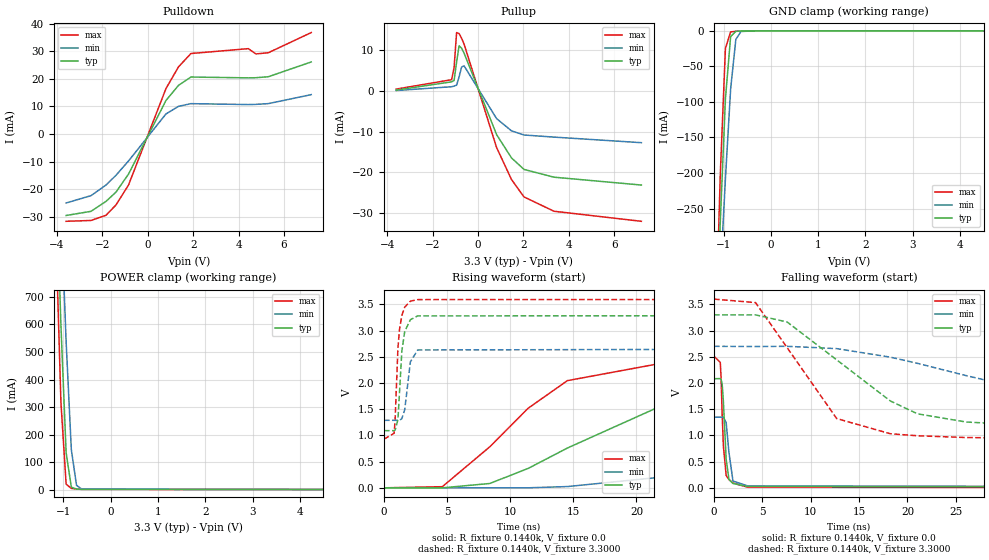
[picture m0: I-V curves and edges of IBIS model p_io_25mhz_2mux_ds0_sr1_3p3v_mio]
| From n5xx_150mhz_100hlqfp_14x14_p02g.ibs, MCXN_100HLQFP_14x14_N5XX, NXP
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[Model] p_io_25mhz_2mux_ds0_sr1_3p3v_mio
|   Model p_io_25mhz_2mux_ds0_sr1_3p3v_mio
| This model was characterised for following simulation conditions:
| External (pad) voltage:
|   - Typ: 3.3V,   - Min: 2.7V,   - Max: 3.6V
| Library cells for typ/min/max conditions are connected as defined below:
|  pad - External Pad
|  ipp_do_lv - Core Input
|  ipp_obe_lv - Output Buffer Enable
|  IOGC - NC
|  REFH3V3 - REFH3V3
|  REFL3V3 - REFL3V3
|  ZI - NC
|  abut_ncal_vddio[1] - vddio
|  abut_ncal_vddio[2] - vddio
|  abut_ncal_vddio[3] - vssio
|  abut_ncal_vddio[4] - vddio
|  abut_ncal_vddio[5] - vddio
|  abut_ncal_vddio[6] - vssio
|  abut_pcal_vddio[1] - vssio
|  abut_pcal_vddio[2] - vssio
|  abut_pcal_vddio[3] - vddio
|  abut_pcal_vddio[4] - vssio
|  abut_pcal_vddio[5] - vssio
|  abut_pcal_vddio[6] - vddio
|  ipp_do_1p8v - ipp_do_1p8v
|  ipp_dse_lv - 0
|  ipp_eftd_lv - NC
|  ipp_ina_mux_vddio - NC
|  ipp_ina_mux_vddio[0] - NC
|  ipp_ina_mux_vddio[1] - NC
|  ipp_ina_r0_vddio - NC
|  ipp_ina_r0a_vddio - NC
|  ipp_ina_r0b_vddio - NC
|  ipp_ina_r0c_vddio - NC
|  ipp_ina_r0d_vddio - NC
|  ipp_ina_r0e_vddio - NC
|  ipp_ina_r0f_vddio - NC
|  ipp_ina_r300_vddio - NC
|  ipp_ina_r300a_vddio - NC
|  ipp_ina_r300b_vddio - NC
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Model_type I/O
Polarity   Non-Inverting
Enable   Active-High
Vinl =   0.9900V
Vinh =   2.3100V
Vmeas =  1.6500V
Cref =   30.0000pF
Rref =   1.0000M
Vref =   3.3000V
C_comp   1.2811pF   1.2303pF   1.3501pF
|C_comp_pullup   0.5371pF   0.5683pF   0.5158pF
|C_comp_pulldown   0.6703pF   0.7070pF   0.6412pF
[Model Spec]
| variable   typ   min   max
Vinh   2.3100V   1.8900V   2.5200V
Vinl   0.9900V   0.8100V   1.0800V
[Temperature Range]   25.0000   0.1250k   -40.0000
[Voltage Range]   3.3000V   2.7000V   3.6000V
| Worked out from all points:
|   slope of the pulldown table from 0 to 0.495 V, typ, clamps not added: 61.2 ohm
|   slope of the pullup table from 0 to 0.495 V, typ, clamps not added: 71.7 ohm
|   GND clamp passes 1 mA (typ) near -0.74 V on its own axis
|   POWER clamp passes 1 mA (typ) near -0.62 V on its own axis
|   rising waveform, R_fixture 0.1440k, V_fixture 0.0: 20-80 % time 11.8ns typ, 25.5ns min, 6.93ns max; typ from 0 V to 2.08 V
|   rising waveform, R_fixture 0.1440k, V_fixture 3.3000: 20-80 % time 369ps typ, 420ps min, 343ps max; typ from 1.09 V to 3.3 V
|   falling waveform, R_fixture 0.1440k, V_fixture 0.0: 20-80 % time 354ps typ, 419ps min, 326ps max; typ from 2.08 V to 0 V
|   falling waveform, R_fixture 0.1440k, V_fixture 3.3000: 20-80 % time 9.37ns typ, 20.6ns min, 5.63ns max; typ from 3.3 V to 1.09 V
[Pulldown]
|Voltage   I(typ)   I(min)   I(max)
-3.6V     -29.55mA   -25.02mA   -31.65mA
-2.5V     -28.03mA   -22.34mA   -31.35mA
-1.84V    -24.43mA   -18.49mA   -29.45mA
-1.4V     -21.05mA   -14.95mA   -25.71mA
-850mV    -14.55mA   -9.778mA   -18.51mA
800mV     12.15mA    7.264mA    16.45mA
1.35V     17.61mA    10.02mA    24.32mA
1.9V      20.65mA    11mA       29.17mA
4.43V     20.35mA    10.67mA    30.94mA
4.76V     20.4mA     10.74mA    29.03mA
5.31V     20.76mA    11.01mA    29.46mA
7.2V      26.12mA    14.27mA    36.77mA
[Pullup]
|Voltage   I(typ)   I(min)   I(max)
-3.6V     250.7uA    138.3uA    483.6uA
-1.16V    2.271mA    1.069mA    2.801mA
-1.05V    2.603mA    1.213mA    5.776mA
-940mV    7.093mA    1.465mA    14.38mA
-830mV    11.13mA    3.481mA    14.15mA
-720mV    10.55mA    5.904mA    12.99mA
-610mV    9.336mA    6.198mA    11.54mA
820mV     -10.68mA   -6.749mA   -13.84mA
1.48V     -16.43mA   -9.783mA   -21.75mA
2.03V     -19.25mA   -10.79mA   -26.01mA
3.35V     -21.16mA   -11.31mA   -29.53mA
7.2V      -23.09mA   -12.68mA   -32mA
[GND_clamp]
|Voltage   I(typ)   I(min)   I(max)
-3.6V     -5.309A    -4.128A    -6.876A
-1.18V    -466mA     -495.4mA   -458.9mA
-1.07V    -271.1mA   -348.5mA   -204.6mA
-960mV    -95.65mA   -208mA     -24.74mA
-850mV    -8.096mA   -81.85mA   -1.471mA
-740mV    -719.7uA   -12.14mA   -717.6uA
-630mV    -272.5uA   -923.5uA   -300.8uA
-300mV    -385.6nA   -2.502uA   -74.88nA
7.2V      0A         0A         0A
[POWER_clamp]
|Voltage   I(typ)   I(min)   I(max)
-3.6V     14.48A     12.95A     16.35A
-1.16V    1.177A     1.535A     951.2mA
-1.05V    598.4mA    1.032A     318mA
-940mV    134.2mA    537.3mA    20.02mA
-830mV    8.708mA    145.4mA    4.242mA
-720mV    2.127mA    15.38mA    2.218mA
-610mV    847.4uA    1.853mA    834.1uA
7.2V      0A         0A         0A
[Ramp]
| variable   typ   min   max
dV/dt_r  1.2492/11.7863n   0.8051/25.5330n   1.5061/6.9303n
dV/dt_f  1.3253/9.3646n   0.8448/20.6188n   1.6029/5.6275n
R_load = 0.1440k
[Rising Waveform]
R_fixture= 0.1440k
V_fixture= 0.0
V_fixture_min= 0.0
V_fixture_max= 0.0
|time   V(typ)   V(min)   V(max)
0s        4.603nV    154.1nV    15.8nV
4.623ns   -87.19uV   -485.7uV   21.82mV
8.385ns   82.97mV    -14.69uV   783.5mV
11.43ns   371.1mV    524.6uV    1.52V
14.53ns   759.1mV    24.19mV    2.045V
21.8ns    1.546V     199.7mV    2.369V
32.26ns   1.91V      584.5mV    2.466V
44.2ns    2.014V     975.5mV    2.496V
55.64ns   2.051V     1.151V     2.505V
141ns     2.082V     1.342V     2.51V
[Rising Waveform]
R_fixture= 0.1440k
V_fixture= 3.3000
V_fixture_min= 2.7000
V_fixture_max= 3.6000
|time   V(typ)   V(min)   V(max)
0s        1.091V     1.288V     928.6mV
807.5ps   1.091V     1.288V     1.041V
884.8ps   1.1V       1.288V     1.3V
1.107ns   1.3V       1.288V     2.664V
1.231ns   1.814V     1.289V     3.019V
1.417ns   2.608V     1.319V     3.289V
1.645ns   2.982V     1.492V     3.447V
2.094ns   3.207V     2.403V     3.561V
2.67ns    3.28V      2.63V      3.591V
141ns     3.3V       2.7V       3.6V
[Falling Waveform]
R_fixture= 0.1440k
V_fixture= 0.0
V_fixture_min= 0.0
V_fixture_max= 0.0
|time   V(typ)   V(min)   V(max)
0s        2.082V     1.348V     2.51V
641.6ps   2.084V     1.348V     2.392V
722.3ps   2.072V     1.348V     2.117V
835.5ps   1.986V     1.348V     1.409V
964ps     1.646V     1.349V     797.8mV
1.251ns   543.9mV    1.242V     236.9mV
1.539ns   161.3mV    673.5mV    157.7mV
1.955ns   82.81mV    130mV      93.06mV
3.486ns   25.59mV    37.02mV    10.93mV
141ns     112.5nV    3.195uV    21.4nV
[Falling Waveform]
R_fixture= 0.1440k
V_fixture= 3.3000
V_fixture_min= 2.7000
V_fixture_max= 3.6000
|time   V(typ)   V(min)   V(max)
0s        3.3V       2.7V       3.6V
4.285ns   3.3V       2.696V     3.534V
7.56ns    3.163V     2.7V       2.673V
12.68ns   2.442V     2.656V     1.322V
18.23ns   1.657V     2.493V     1.032V
21.04ns   1.412V     2.375V     993.7mV
26.07ns   1.256V     2.141V     960.2mV
37.48ns   1.147V     1.653V     936.7mV
48.23ns   1.115V     1.466V     931.3mV
141ns     1.091V     1.292V     928.6mV
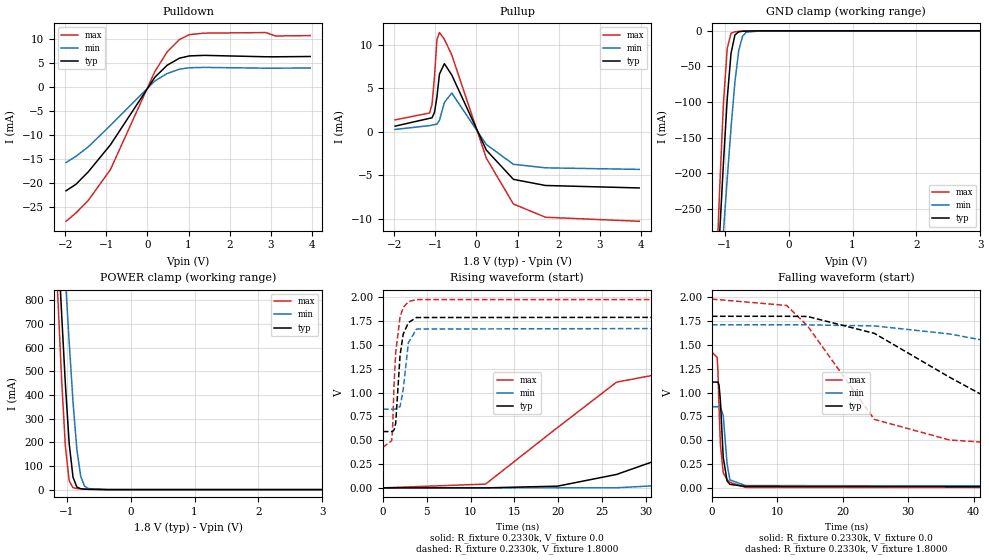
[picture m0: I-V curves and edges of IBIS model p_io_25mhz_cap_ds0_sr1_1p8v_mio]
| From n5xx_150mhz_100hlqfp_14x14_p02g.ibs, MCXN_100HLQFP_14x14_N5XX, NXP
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[Model] p_io_25mhz_cap_ds0_sr1_1p8v_mio
|   Model p_io_25mhz_cap_ds0_sr1_1p8v_mio
| This model was characterised for following simulation conditions:
| External (pad) voltage:
|   - Typ: 1.8V,   - Min: 1.71V,   - Max: 1.98V
| Library cells for typ/min/max conditions are connected as defined below:
|  pad - External Pad
|  ipp_do_lv - Core Input
|  ipp_obe_lv - Output Buffer Enable
|  IOGC - NC
|  REFH3V3 - REFH3V3
|  REFL3V3 - REFL3V3
|  ZI - NC
|  abut_ncal_vddio[1] - vssio vddio vddio
|  abut_ncal_vddio[2] - vddio vddio vssio
|  abut_ncal_vddio[3] - vddio
|  abut_ncal_vddio[4] - vssio vddio vddio
|  abut_ncal_vddio[5] - vddio vddio vssio
|  abut_ncal_vddio[6] - vddio
|  abut_pcal_vddio[1] - vssio
|  abut_pcal_vddio[2] - vddio vssio vddio
|  abut_pcal_vddio[3] - vssio
|  abut_pcal_vddio[4] - vssio
|  abut_pcal_vddio[5] - vddio vssio vddio
|  abut_pcal_vddio[6] - vssio
|  ipp_do_1p8v - ipp_do_1p8v
|  ipp_dse_lv - 0
|  ipp_eftd_lv - NC
|  ipp_ina_mux_vddio - NC
|  ipp_ina_mux_vddio[0] - NC
|  ipp_ina_mux_vddio[1] - NC
|  ipp_ina_r0_vddio - NC
|  ipp_ina_r0a_vddio - NC
|  ipp_ina_r0b_vddio - NC
|  ipp_ina_r0c_vddio - NC
|  ipp_ina_r0d_vddio - NC
|  ipp_ina_r0e_vddio - NC
|  ipp_ina_r0f_vddio - NC
|  ipp_ina_r300_vddio - NC
|  ipp_ina_r300a_vddio - NC
|  ipp_ina_r300b_vddio - NC
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Model_type I/O
Polarity   Non-Inverting
Enable   Active-High
Vinl =   0.5400V
Vinh =   1.2600V
Vmeas =  0.9000V
Cref =   30.0000pF
Rref =   1.0000M
Vref =   1.8000V
C_comp   1.3068pF   1.2541pF   1.3694pF
|C_comp_pullup   0.5699pF   0.5991pF   0.5431pF
|C_comp_pulldown   0.6502pF   0.6819pF   0.6252pF
[Model Spec]
| variable   typ   min   max
Vinh   1.2600V   1.1970V   1.3860V
Vinl   0.5400V   0.5130V   0.5940V
[Temperature Range]   25.0000   0.1250k   -40.0000
[Voltage Range]   1.8000V   1.7100V   1.9800V
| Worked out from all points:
|   slope of the pulldown table from 0 to 0.27 V, typ, clamps not added: 93.6 ohm
|   slope of the pullup table from 0 to 0.27 V, typ, clamps not added: 116 ohm
|   GND clamp passes 1 mA (typ) near -0.76 V on its own axis
|   POWER clamp passes 1 mA (typ) near -0.63 V on its own axis
|   rising waveform, R_fixture 0.2330k, V_fixture 0.0: 20-80 % time 23ns typ, 43.4ns min, 11.5ns max; typ from 0 V to 1.11 V
|   rising waveform, R_fixture 0.2330k, V_fixture 1.8000: 20-80 % time 592ps typ, 649ps min, 565ps max; typ from 0.59 V to 1.8 V
|   falling waveform, R_fixture 0.2330k, V_fixture 0.0: 20-80 % time 550ps typ, 630ps min, 505ps max; typ from 1.11 V to 0 V
|   falling waveform, R_fixture 0.2330k, V_fixture 1.8000: 20-80 % time 19.4ns typ, 38ns min, 9.57ns max; typ from 1.8 V to 0.591 V
[Pulldown]
|Voltage   I(typ)   I(min)   I(max)
-1.98V    -21.59mA   -15.72mA   -27.94mA
-1.74V    -20.25mA   -14.42mA   -26.22mA
-1.44V    -17.66mA   -12.45mA   -23.61mA
-900mV    -12.03mA   -7.993mA   -17.18mA
180mV     2.026mA    1.252mA    3.209mA
480mV     4.533mA    2.805mA    7.305mA
780mV     5.999mA    3.712mA    9.891mA
1.02V     6.469mA    4.005mA    10.9mA
1.38V     6.587mA    4.078mA    11.21mA
2.88V     6.294mA    3.922mA    11.33mA
3.12V     6.289mA    3.924mA    10.62mA
3.96V     6.351mA    3.959mA    10.7mA
[Pullup]
|Voltage   I(typ)   I(min)   I(max)
-1.98V    644.9uA    266.3uA    1.361mA
-1.14V    1.542mA    707.2uA    2.153mA
-1.08V    1.604mA    764.5uA    3.171mA
-1.02V    2.234mA    824.1uA    6.358mA
-960mV    4.021mA    885.3uA    10.59mA
-900mV    6.607mA    1.315mA    11.37mA
-780mV    7.807mA    3.354mA    10.59mA
-600mV    6.505mA    4.443mA    8.805mA
240mV     -2.097mA   -1.459mA   -3.022mA
900mV     -5.454mA   -3.726mA   -8.28mA
1.68V     -6.156mA   -4.132mA   -9.795mA
3.96V     -6.438mA   -4.31mA    -10.26mA
[GND_clamp]
|Voltage   I(typ)   I(min)   I(max)
-1.98V    -2A        -1.65A     -2.499A
-1.14V    -394mA     -441.5mA   -363.8mA
-1.08V    -288.3mA   -361.7mA   -226.5mA
-1.02V    -187.2mA   -283.6mA   -103.8mA
-960mV    -95.64mA   -207.9mA   -24.71mA
-900mV    -31.47mA   -136.2mA   -3.431mA
-840mV    -6.005mA   -72.18mA   -1.326mA
-780mV    -1.297mA   -27.91mA   -902.8uA
-720mV    -576.7uA   -7.631mA   -619.4uA
-660mV    -346.6uA   -1.807mA   -391.2uA
-420mV    -13.9uA    -31.12uA   -8.588uA
3.96V     0A         0A         0A
[POWER_clamp]
|Voltage   I(typ)   I(min)   I(max)
-1.98V    5.618A     5.349A     6.084A
-1.14V    1.071A     1.443A     829.6mA
-1.08V    754.2mA    1.168A     476.4mA
-1.02V    449mA      895.6mA    184.6mA
-960mV    195.8mA    625.5mA    36.79mA
-900mV    52.44mA    371.1mA    7.808mA
-840mV    10.74mA    170.2mA    4.435mA
-780mV    3.619mA    56.22mA    3.182mA
-720mV    2.074mA    15.04mA    2.195mA
-660mV    1.306mA    4.299mA    1.376mA
-360mV    5.079uA    27.62uA    1.341uA
3.96V     0A         0A         0A
[Ramp]
| variable   typ   min   max
dV/dt_r  0.6658/22.9562n   0.5082/43.3555n   0.8537/11.5006n
dV/dt_f  0.7256/19.4131n   0.5286/37.9876n   0.9328/9.5732n
R_load = 0.2330k
[Rising Waveform]
R_fixture= 0.2330k
V_fixture= 0.0
V_fixture_min= 0.0
V_fixture_max= 0.0
|time   V(typ)   V(min)   V(max)
0s        633.2pV    205.5nV    16.75pV
11.71ns   -34.77uV   -15.75uV   39.45mV
19.91ns   17.74mV    38.91uV    632.4mV
26.64ns   140.6mV    862.6uV    1.109V
40.41ns   586.7mV    68.61mV    1.347V
49.27ns   832.8mV    163.9mV    1.385V
59.5ns    965.5mV    301.6mV    1.405V
80.54ns   1.059V     578mV      1.419V
99.99ns   1.088V     713.4mV    1.422V
225.6ns   1.11V      847mV      1.423V
[Rising Waveform]
R_fixture= 0.2330k
V_fixture= 1.8000
V_fixture_min= 1.7100
V_fixture_max= 1.9800
|time   V(typ)   V(min)   V(max)
0s        590.5mV    825.5mV    425.3mV
1.009ns   590.4mV    825.6mV    493.9mV
1.106ns   590.6mV    825.6mV    609.3mV
1.3ns     611.4mV    825.6mV    1.132V
1.47ns    683mV      825.5mV    1.424V
1.964ns   1.393V     852.7mV    1.794V
2.32ns    1.612V     1.029V     1.891V
2.914ns   1.734V     1.523V     1.954V
3.827ns   1.787V     1.666V     1.975V
225.6ns   1.8V       1.71V      1.98V
[Falling Waveform]
R_fixture= 0.2330k
V_fixture= 0.0
V_fixture_min= 0.0
V_fixture_max= 0.0
|time   V(typ)   V(min)   V(max)
0s        1.11V      851.6mV    1.423V
810ps     1.11V      851.6mV    1.369V
930.3ps   1.11V      851.5mV    1.223V
1.095ns   1.079V     852mV      836.7mV
1.301ns   916.9mV    853.6mV    457mV
1.735ns   320.1mV    757.8mV    158mV
2.324ns   72.57mV    251.6mV    86.63mV
2.755ns   36.7mV     83.44mV    57.69mV
5.128ns   15.42mV    24.35mV    4.946mV
225.6ns   174nV      2.834uV    36.02nV
[Falling Waveform]
R_fixture= 0.2330k
V_fixture= 1.8000
V_fixture_min= 1.7100
V_fixture_max= 1.9800
|time   V(typ)   V(min)   V(max)
0s        1.8V       1.71V      1.98V
11.41ns   1.8V       1.71V      1.914V
14.61ns   1.798V     1.71V      1.699V
24.82ns   1.621V     1.699V     718.1mV
36.27ns   1.162V     1.615V     503mV
43.53ns   891mV      1.522V     468.8mV
51.74ns   753.6mV    1.393V     449.5mV
72.24ns   646.7mV    1.076V     431.7mV
90.92ns   615.4mV    951.6mV    427.3mV
225.6ns   590.6mV    828.9mV    425.3mV
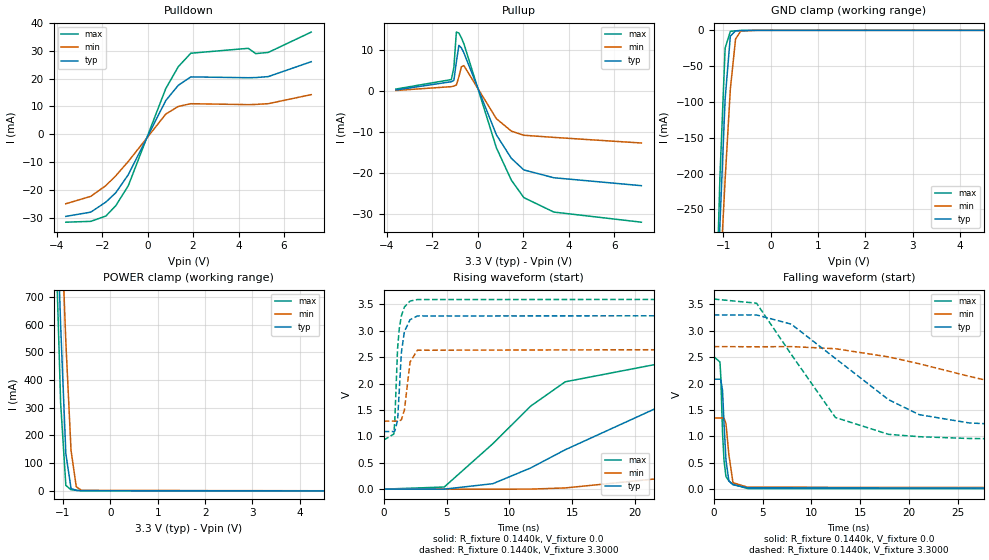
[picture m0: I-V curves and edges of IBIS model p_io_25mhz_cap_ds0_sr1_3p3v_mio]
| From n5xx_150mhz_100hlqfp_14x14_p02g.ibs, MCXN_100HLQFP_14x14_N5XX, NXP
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[Model] p_io_25mhz_cap_ds0_sr1_3p3v_mio
|   Model p_io_25mhz_cap_ds0_sr1_3p3v_mio
| This model was characterised for following simulation conditions:
| External (pad) voltage:
|   - Typ: 3.3V,   - Min: 2.7V,   - Max: 3.6V
| Library cells for typ/min/max conditions are connected as defined below:
|  pad - External Pad
|  ipp_do_lv - Core Input
|  ipp_obe_lv - Output Buffer Enable
|  IOGC - NC
|  REFH3V3 - REFH3V3
|  REFL3V3 - REFL3V3
|  ZI - NC
|  abut_ncal_vddio[1] - vddio
|  abut_ncal_vddio[2] - vddio
|  abut_ncal_vddio[3] - vssio
|  abut_ncal_vddio[4] - vddio
|  abut_ncal_vddio[5] - vddio
|  abut_ncal_vddio[6] - vssio
|  abut_pcal_vddio[1] - vssio
|  abut_pcal_vddio[2] - vssio
|  abut_pcal_vddio[3] - vddio
|  abut_pcal_vddio[4] - vssio
|  abut_pcal_vddio[5] - vssio
|  abut_pcal_vddio[6] - vddio
|  ipp_do_1p8v - ipp_do_1p8v
|  ipp_dse_lv - 0
|  ipp_eftd_lv - NC
|  ipp_ina_mux_vddio - NC
|  ipp_ina_mux_vddio[0] - NC
|  ipp_ina_mux_vddio[1] - NC
|  ipp_ina_r0_vddio - NC
|  ipp_ina_r0a_vddio - NC
|  ipp_ina_r0b_vddio - NC
|  ipp_ina_r0c_vddio - NC
|  ipp_ina_r0d_vddio - NC
|  ipp_ina_r0e_vddio - NC
|  ipp_ina_r0f_vddio - NC
|  ipp_ina_r300_vddio - NC
|  ipp_ina_r300a_vddio - NC
|  ipp_ina_r300b_vddio - NC
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Model_type I/O
Polarity   Non-Inverting
Enable   Active-High
Vinl =   0.9900V
Vinh =   2.3100V
Vmeas =  1.6500V
Cref =   30.0000pF
Rref =   1.0000M
Vref =   3.3000V
C_comp   1.2811pF   1.2304pF   1.3502pF
|C_comp_pullup   0.5381pF   0.5693pF   0.5168pF
|C_comp_pulldown   0.6568pF   0.6935pF   0.6277pF
[Model Spec]
| variable   typ   min   max
Vinh   2.3100V   1.8900V   2.5200V
Vinl   0.9900V   0.8100V   1.0800V
[Temperature Range]   25.0000   0.1250k   -40.0000
[Voltage Range]   3.3000V   2.7000V   3.6000V
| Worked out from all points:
|   slope of the pulldown table from 0 to 0.495 V, typ, clamps not added: 61.2 ohm
|   slope of the pullup table from 0 to 0.495 V, typ, clamps not added: 71.7 ohm
|   GND clamp passes 1 mA (typ) near -0.74 V on its own axis
|   POWER clamp passes 1 mA (typ) near -0.62 V on its own axis
|   rising waveform, R_fixture 0.1440k, V_fixture 0.0: 20-80 % time 11.8ns typ, 25.5ns min, 6.93ns max; typ from 0 V to 2.08 V
|   rising waveform, R_fixture 0.1440k, V_fixture 3.3000: 20-80 % time 368ps typ, 420ps min, 343ps max; typ from 1.09 V to 3.3 V
|   falling waveform, R_fixture 0.1440k, V_fixture 0.0: 20-80 % time 355ps typ, 419ps min, 326ps max; typ from 2.08 V to 0 V
|   falling waveform, R_fixture 0.1440k, V_fixture 3.3000: 20-80 % time 9.36ns typ, 20.6ns min, 5.63ns max; typ from 3.3 V to 1.09 V
[Pulldown]
|Voltage   I(typ)   I(min)   I(max)
-3.6V     -29.56mA   -25.02mA   -31.65mA
-2.5V     -28.03mA   -22.34mA   -31.35mA
-1.84V    -24.43mA   -18.49mA   -29.45mA
-1.4V     -21.05mA   -14.95mA   -25.71mA
-850mV    -14.55mA   -9.779mA   -18.52mA
800mV     12.15mA    7.264mA    16.46mA
1.35V     17.62mA    10.02mA    24.32mA
1.9V      20.65mA    11mA       29.17mA
4.43V     20.35mA    10.67mA    30.94mA
4.76V     20.41mA    10.74mA    29.03mA
5.31V     20.76mA    11.01mA    29.46mA
7.2V      26.12mA    14.27mA    36.78mA
[Pullup]
|Voltage   I(typ)   I(min)   I(max)
-3.6V     250.7uA    138.3uA    483.6uA
-1.16V    2.271mA    1.069mA    2.801mA
-1.05V    2.603mA    1.213mA    5.776mA
-940mV    7.093mA    1.465mA    14.38mA
-830mV    11.13mA    3.481mA    14.15mA
-720mV    10.55mA    5.904mA    12.99mA
-610mV    9.336mA    6.198mA    11.54mA
820mV     -10.68mA   -6.749mA   -13.84mA
1.48V     -16.43mA   -9.783mA   -21.75mA
2.03V     -19.25mA   -10.79mA   -26.01mA
3.35V     -21.16mA   -11.31mA   -29.53mA
7.2V      -23.09mA   -12.68mA   -32mA
[GND_clamp]
|Voltage   I(typ)   I(min)   I(max)
-3.6V     -5.309A    -4.128A    -6.876A
-1.18V    -466mA     -495.4mA   -458.9mA
-1.07V    -271.1mA   -348.5mA   -204.6mA
-960mV    -95.65mA   -207.9mA   -24.72mA
-850mV    -8.088mA   -81.85mA   -1.461mA
-740mV    -716.3uA   -12.13mA   -715.9uA
-630mV    -272.3uA   -921.7uA   -303uA
-300mV    -444.9nA   -2.656uA   -94.82nA
7.2V      0A         0A         0A
[POWER_clamp]
|Voltage   I(typ)   I(min)   I(max)
-3.6V     14.48A     12.95A     16.35A
-1.16V    1.177A     1.535A     951.2mA
-1.05V    598.4mA    1.032A     318mA
-940mV    134.2mA    537.3mA    20.05mA
-830mV    8.719mA    145.4mA    4.267mA
-720mV    2.135mA    15.38mA    2.236mA
-610mV    852.8uA    1.854mA    844.7uA
7.2V      0A         0A         0A
[Ramp]
| variable   typ   min   max
dV/dt_r  1.2492/11.7922n   0.8051/25.5189n   1.5061/6.9341n
dV/dt_f  1.3253/9.3636n   0.8449/20.5957n   1.6029/5.6280n
R_load = 0.1440k
[Rising Waveform]
R_fixture= 0.1440k
V_fixture= 0.0
V_fixture_min= 0.0
V_fixture_max= 0.0
|time   V(typ)   V(min)   V(max)
0s        4.636nV    156.4nV    15.8nV
4.816ns   -71.67uV   -328.3uV   40.61mV
8.685ns   103.9mV    -2.297uV   862.2mV
11.68ns   400.9mV    612.2uV    1.572V
14.43ns   745.9mV    22.81mV    2.033V
21.72ns   1.539V     196.9mV    2.367V
32.57ns   1.915V     596.2mV    2.467V
44.53ns   2.015V     983.3mV    2.497V
56.41ns   2.053V     1.158V     2.506V
141ns     2.082V     1.342V     2.51V
[Rising Waveform]
R_fixture= 0.1440k
V_fixture= 3.3000
V_fixture_min= 2.7000
V_fixture_max= 3.6000
|time   V(typ)   V(min)   V(max)
0s        1.091V     1.288V     928.5mV
809.7ps   1.091V     1.288V     1.044V
884.1ps   1.099V     1.288V     1.296V
1.107ns   1.3V       1.288V     2.663V
1.242ns   1.871V     1.29V      3.041V
1.411ns   2.591V     1.317V     3.283V
1.651ns   2.987V     1.501V     3.45V
2.099ns   3.209V     2.408V     3.562V
2.682ns   3.28V      2.631V     3.591V
141ns     3.3V       2.7V       3.6V
[Falling Waveform]
R_fixture= 0.1440k
V_fixture= 0.0
V_fixture_min= 0.0
V_fixture_max= 0.0
|time   V(typ)   V(min)   V(max)
0s        2.082V     1.348V     2.51V
632.4ps   2.083V     1.348V     2.408V
716.5ps   2.074V     1.348V     2.144V
897.4ps   1.869V     1.349V     1.069V
1.051ns   1.241V     1.343V     540.9mV
1.249ns   546.7mV    1.243V     237.8mV
1.547ns   155.8mV    653.2mV    155.6mV
1.967ns   83.68mV    122.8mV    91.86mV
3.459ns   26.4mV     37.44mV    11.4mV
141ns     112.7nV    3.203uV    21.4nV
[Falling Waveform]
R_fixture= 0.1440k
V_fixture= 3.3000
V_fixture_min= 2.7000
V_fixture_max= 3.6000
|time   V(typ)   V(min)   V(max)
0s        3.3V       2.7V       3.6V
4.383ns   3.299V     2.696V     3.522V
7.943ns   3.125V     2.7V       2.552V
12.47ns   2.475V     2.66V      1.357V
17.92ns   1.694V     2.505V     1.038V
21.06ns   1.411V     2.375V     993.6mV
26.15ns   1.255V     2.138V     959.7mV
37.89ns   1.145V     1.64V      936.3mV
48.86ns   1.114V     1.46V      931.1mV
141ns     1.091V     1.292V     928.5mV
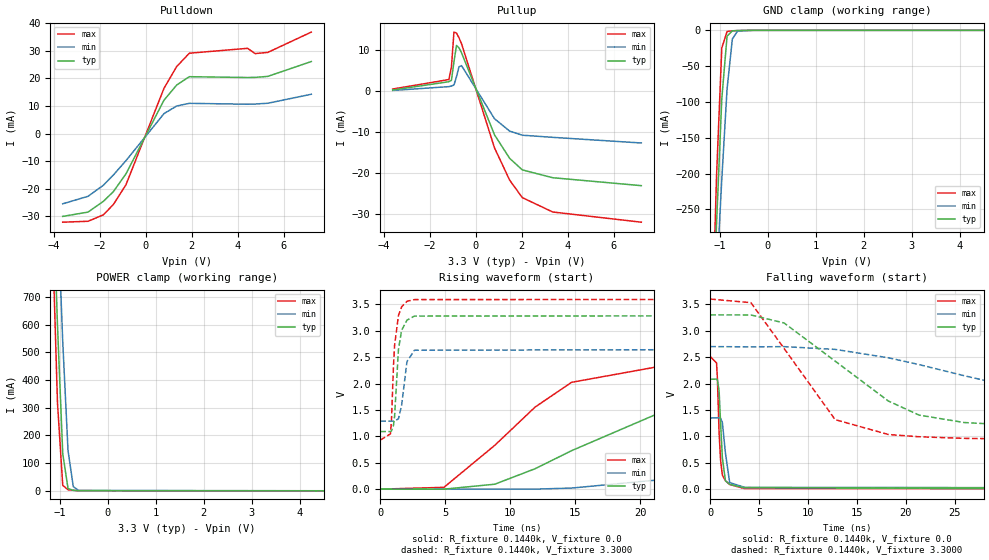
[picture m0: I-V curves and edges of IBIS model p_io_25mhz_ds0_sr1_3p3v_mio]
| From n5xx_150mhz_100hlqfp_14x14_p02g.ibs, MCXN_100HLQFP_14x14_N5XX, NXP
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[Model] p_io_25mhz_ds0_sr1_3p3v_mio
|   Model p_io_25mhz_ds0_sr1_3p3v_mio
| This model was characterised for following simulation conditions:
| External (pad) voltage:
|   - Typ: 3.3V,   - Min: 2.7V,   - Max: 3.6V
| Library cells for typ/min/max conditions are connected as defined below:
|  pad - External Pad
|  ipp_do_lv - Core Input
|  ipp_obe_lv - Output Buffer Enable
|  IOGC - NC
|  REFH3V3 - REFH3V3
|  REFL3V3 - REFL3V3
|  ZI - NC
|  abut_ncal_vddio[1] - vddio
|  abut_ncal_vddio[2] - vddio
|  abut_ncal_vddio[3] - vssio
|  abut_ncal_vddio[4] - vddio
|  abut_ncal_vddio[5] - vddio
|  abut_ncal_vddio[6] - vssio
|  abut_pcal_vddio[1] - vssio
|  abut_pcal_vddio[2] - vssio
|  abut_pcal_vddio[3] - vddio
|  abut_pcal_vddio[4] - vssio
|  abut_pcal_vddio[5] - vssio
|  abut_pcal_vddio[6] - vddio
|  ipp_do_1p8v - ipp_do_1p8v
|  ipp_dse_lv - 0
|  ipp_eftd_lv - NC
|  ipp_ina_mux_vddio - NC
|  ipp_ina_mux_vddio[0] - NC
|  ipp_ina_mux_vddio[1] - NC
|  ipp_ina_r0_vddio - NC
|  ipp_ina_r0a_vddio - NC
|  ipp_ina_r0b_vddio - NC
|  ipp_ina_r0c_vddio - NC
|  ipp_ina_r0d_vddio - NC
|  ipp_ina_r0e_vddio - NC
|  ipp_ina_r0f_vddio - NC
|  ipp_ina_r300_vddio - NC
|  ipp_ina_r300a_vddio - NC
|  ipp_ina_r300b_vddio - NC
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Model_type I/O
Polarity   Non-Inverting
Enable   Active-High
Vinl =   0.9900V
Vinh =   2.3100V
Vmeas =  1.6500V
Cref =   30.0000pF
Rref =   1.0000M
Vref =   3.3000V
C_comp   1.2813pF   1.2310pF   1.3501pF
|C_comp_pullup   0.5367pF   0.5681pF   0.5154pF
|C_comp_pulldown   0.6536pF   0.6897pF   0.6248pF
[Model Spec]
| variable   typ   min   max
Vinh   2.3100V   1.8900V   2.5200V
Vinl   0.9900V   0.8100V   1.0800V
[Temperature Range]   25.0000   0.1250k   -40.0000
[Voltage Range]   3.3000V   2.7000V   3.6000V
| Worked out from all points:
|   slope of the pulldown table from 0 to 0.495 V, typ, clamps not added: 61.2 ohm
|   slope of the pullup table from 0 to 0.495 V, typ, clamps not added: 71.6 ohm
|   GND clamp passes 1 mA (typ) near -0.74 V on its own axis
|   POWER clamp passes 1 mA (typ) near -0.62 V on its own axis
|   rising waveform, R_fixture 0.1440k, V_fixture 0.0: 20-80 % time 12.1ns typ, 26.1ns min, 7.09ns max; typ from 0 V to 2.08 V
|   rising waveform, R_fixture 0.1440k, V_fixture 3.3000: 20-80 % time 367ps typ, 422ps min, 345ps max; typ from 1.09 V to 3.3 V
|   falling waveform, R_fixture 0.1440k, V_fixture 0.0: 20-80 % time 358ps typ, 425ps min, 329ps max; typ from 2.08 V to 0 V
|   falling waveform, R_fixture 0.1440k, V_fixture 3.3000: 20-80 % time 9.56ns typ, 21ns min, 5.76ns max; typ from 3.3 V to 1.09 V
[Pulldown]
|Voltage   I(typ)   I(min)   I(max)
-3.6V     -30mA      -25.44mA   -32.1mA
-2.5V     -28.44mA   -22.71mA   -31.77mA
-1.84V    -24.58mA   -18.74mA   -29.46mA
-1.4V     -21.04mA   -15mA      -25.71mA
-850mV    -14.54mA   -9.776mA   -18.5mA
800mV     12.14mA    7.262mA    16.45mA
1.35V     17.61mA    10.02mA    24.31mA
1.9V      20.65mA    10.99mA    29.16mA
4.43V     20.35mA    10.67mA    30.93mA
4.76V     20.4mA     10.74mA    29.02mA
5.31V     20.76mA    11.02mA    29.46mA
7.2V      26.15mA    14.29mA    36.82mA
[Pullup]
|Voltage   I(typ)   I(min)   I(max)
-3.6V     251.1uA    138.4uA    485.2uA
-1.16V    2.273mA    1.07mA     2.803mA
-1.05V    2.605mA    1.214mA    5.78mA
-940mV    7.098mA    1.466mA    14.39mA
-830mV    11.13mA    3.483mA    14.16mA
-720mV    10.55mA    5.906mA    12.99mA
-610mV    9.34mA     6.201mA    11.54mA
820mV     -10.68mA   -6.751mA   -13.85mA
1.48V     -16.44mA   -9.786mA   -21.76mA
2.03V     -19.26mA   -10.79mA   -26.03mA
3.35V     -21.17mA   -11.31mA   -29.54mA
7.2V      -23.11mA   -12.69mA   -32.03mA
[GND_clamp]
|Voltage   I(typ)   I(min)   I(max)
-3.6V     -5.285A    -4.099A    -6.854A
-1.18V    -466mA     -495.3mA   -458.9mA
-1.07V    -271.1mA   -348.5mA   -204.6mA
-960mV    -95.66mA   -207.9mA   -24.82mA
-850mV    -8.126mA   -81.84mA   -1.536mA
-740mV    -740.4uA   -12.14mA   -755uA
-630mV    -283.6uA   -928.1uA   -319.7uA
-300mV    -497.8nA   -2.865uA   -109.5nA
7.2V      0A         0A         0A
[POWER_clamp]
|Voltage   I(typ)   I(min)   I(max)
-3.6V     14.48A     12.95A     16.35A
-1.16V    1.177A     1.535A     951.2mA
-1.05V    598.3mA    1.032A     318mA
-940mV    134.2mA    537.3mA    19.98mA
-830mV    8.694mA    145.4mA    4.231mA
-720mV    2.123mA    15.37mA    2.22mA
-610mV    848.6uA    1.85mA     839.5uA
7.2V      0A         0A         0A
[Ramp]
| variable   typ   min   max
dV/dt_r  1.2494/12.0722n   0.8047/26.1311n   1.5064/7.0911n
dV/dt_f  1.3251/9.5638n   0.8446/21.0206n   1.6027/5.7555n
R_load = 0.1440k
[Rising Waveform]
R_fixture= 0.1440k
V_fixture= 0.0
V_fixture_min= 0.0
V_fixture_max= 0.0
|time   V(typ)   V(min)   V(max)
0s        4.67nV     159.2nV    15.81nV
4.895ns   -91.81uV   -262.4uV   34.24mV
8.805ns   93.57mV    -14.76uV   830mV
11.91ns   387.1mV    525.9uV    1.555V
14.71ns   728.4mV    20.54mV    2.023V
22.58ns   1.561V     202.9mV    2.374V
33.65ns   1.919V     601.1mV    2.469V
44.77ns   2.012V     960.1mV    2.496V
56.88ns   2.051V     1.149V     2.506V
141ns     2.082V     1.341V     2.511V
[Rising Waveform]
R_fixture= 0.1440k
V_fixture= 3.3000
V_fixture_min= 2.7000
V_fixture_max= 3.6000
|time   V(typ)   V(min)   V(max)
0s        1.091V     1.289V     928.9mV
785.4ps   1.091V     1.289V     1.047V
857.9ps   1.101V     1.289V     1.287V
1.015ns   1.205V     1.289V     2.332V
1.099ns   1.375V     1.288V     2.717V
1.398ns   2.645V     1.333V     3.289V
1.64ns    3.007V     1.585V     3.452V
2.051ns   3.2V       2.414V     3.557V
2.629ns   3.278V     2.631V     3.59V
141ns     3.3V       2.7V       3.6V
[Falling Waveform]
R_fixture= 0.1440k
V_fixture= 0.0
V_fixture_min= 0.0
V_fixture_max= 0.0
|time   V(typ)   V(min)   V(max)
0s        2.083V     1.348V     2.511V
641.5ps   2.084V     1.348V     2.392V
731.4ps   2.068V     1.348V     2.082V
902.6ps   1.863V     1.349V     1.068V
1.053ns   1.262V     1.343V     550.2mV
1.237ns   594.6mV    1.263V     265.4mV
1.551ns   159.5mV    685.3mV    159.3mV
1.985ns   90.75mV    124.6mV    88.43mV
3.499ns   24.68mV    35.57mV    11.09mV
141ns     118nV      3.311uV    20.12nV
[Falling Waveform]
R_fixture= 0.1440k
V_fixture= 3.3000
V_fixture_min= 2.7000
V_fixture_max= 3.6000
|time   V(typ)   V(min)   V(max)
0s        3.3V       2.7V       3.6V
4.157ns   3.299V     2.695V     3.532V
7.558ns   3.147V     2.699V     2.664V
12.78ns   2.425V     2.647V     1.317V
18.23ns   1.669V     2.488V     1.035V
21.37ns   1.403V     2.359V     992.4mV
25.98ns   1.262V     2.149V     961.8mV
37.33ns   1.15V      1.666V     937.4mV
48.26ns   1.116V     1.47V      931.7mV
141ns     1.091V     1.292V     928.9mV
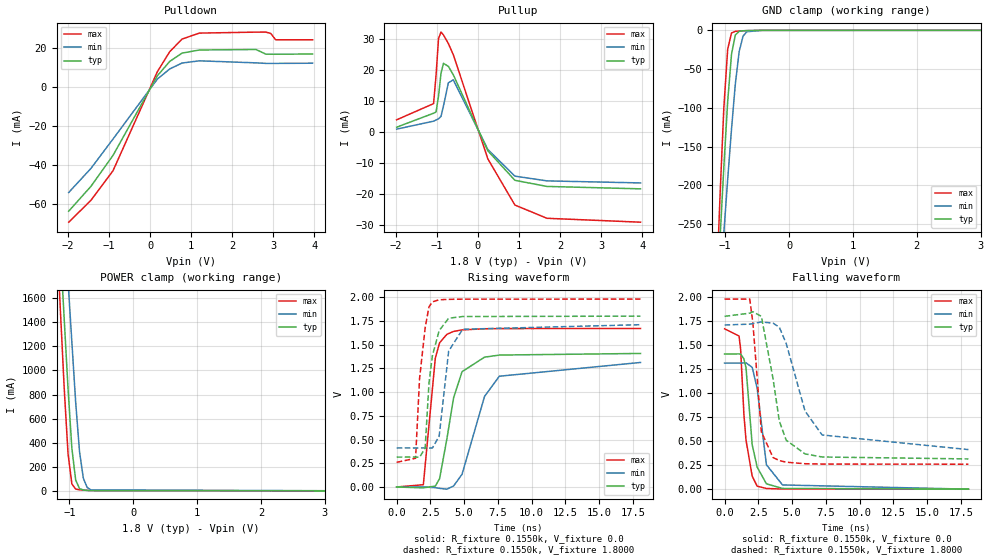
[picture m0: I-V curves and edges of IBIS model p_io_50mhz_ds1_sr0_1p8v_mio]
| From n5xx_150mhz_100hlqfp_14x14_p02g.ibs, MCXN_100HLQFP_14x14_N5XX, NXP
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[Model] p_io_50mhz_ds1_sr0_1p8v_mio
|   Model p_io_50mhz_ds1_sr0_1p8v_mio
| This model was characterised for following simulation conditions:
| External (pad) voltage:
|   - Typ: 1.8V,   - Min: 1.71V,   - Max: 1.98V
| Library cells for typ/min/max conditions are connected as defined below:
|  pad - External Pad
|  ipp_do_lv - Core Input
|  ipp_obe_lv - Output Buffer Enable
|  IOGC - NC
|  REFH3V3 - REFH3V3
|  REFL3V3 - REFL3V3
|  ZI - NC
|  abut_ncal_vddio[1] - vssio vddio vddio
|  abut_ncal_vddio[2] - vddio vddio vssio
|  abut_ncal_vddio[3] - vddio
|  abut_ncal_vddio[4] - vssio vddio vddio
|  abut_ncal_vddio[5] - vddio vddio vssio
|  abut_ncal_vddio[6] - vddio
|  abut_pcal_vddio[1] - vssio
|  abut_pcal_vddio[2] - vddio vssio vddio
|  abut_pcal_vddio[3] - vssio
|  abut_pcal_vddio[4] - vssio
|  abut_pcal_vddio[5] - vddio vssio vddio
|  abut_pcal_vddio[6] - vssio
|  ipp_do_1p8v - ipp_do_1p8v
|  ipp_dse_lv - vdd_lv
|  ipp_eftd_lv - NC
|  ipp_ina_mux_vddio - NC
|  ipp_ina_mux_vddio[0] - NC
|  ipp_ina_mux_vddio[1] - NC
|  ipp_ina_r0_vddio - NC
|  ipp_ina_r0a_vddio - NC
|  ipp_ina_r0b_vddio - NC
|  ipp_ina_r0c_vddio - NC
|  ipp_ina_r0d_vddio - NC
|  ipp_ina_r0e_vddio - NC
|  ipp_ina_r0f_vddio - NC
|  ipp_ina_r300_vddio - NC
|  ipp_ina_r300a_vddio - NC
|  ipp_ina_r300b_vddio - NC
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Model_type I/O
Polarity   Non-Inverting
Enable   Active-High
Vinl =   0.5400V
Vinh =   1.2600V
Vmeas =  0.9000V
Cref =   30.0000pF
Rref =   1.0000M
Vref =   1.8000V
C_comp   1.4770pF   1.4118pF   1.5590pF
|C_comp_pullup   0.7605pF   0.7871pF   0.7346pF
|C_comp_pulldown   0.6305pF   0.6838pF   0.5886pF
[Model Spec]
| variable   typ   min   max
Vinh   1.2600V   1.1970V   1.3860V
Vinl   0.5400V   0.5130V   0.5940V
[Temperature Range]   25.0000   0.1250k   -40.0000
[Voltage Range]   1.8000V   1.7100V   1.9800V
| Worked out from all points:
|   slope of the pulldown table from 0 to 0.27 V, typ, clamps not added: 32.1 ohm
|   slope of the pullup table from 0 to 0.27 V, typ, clamps not added: 40.9 ohm
|   GND clamp passes 1 mA (typ) near -0.75 V on its own axis
|   POWER clamp passes 1 mA (typ) near -0.55 V on its own axis
|   rising waveform, R_fixture 0.1550k, V_fixture 0.0: 20-80 % time 1.1ns typ, 1.7ns min, 609ps max; typ from 0 V to 1.41 V
|   rising waveform, R_fixture 0.1550k, V_fixture 1.8000: 20-80 % time 594ps typ, 636ps min, 529ps max; typ from 0.315 V to 1.8 V
|   falling waveform, R_fixture 0.1550k, V_fixture 0.0: 20-80 % time 584ps typ, 669ps min, 563ps max; typ from 1.41 V to 0 V
|   falling waveform, R_fixture 0.1550k, V_fixture 1.8000: 20-80 % time 988ps typ, 1.75ns min, 565ps max; typ from 1.8 V to 0.315 V
[Pulldown]
|Voltage   I(typ)   I(min)   I(max)
-1.98V    -63.59mA   -54.01mA   -69.25mA
-1.44V    -50.89mA   -41.69mA   -58.06mA
-900mV    -34.94mA   -26.56mA   -42.81mA
180mV     5.908mA    4.185mA    8.001mA
480mV     13.23mA    9.376mA    18.23mA
780mV     17.5mA     12.41mA    24.7mA
1.2V      19.1mA     13.55mA    27.77mA
2.58V     19.36mA    12.5mA     28.27mA
2.82V     16.99mA    12.23mA    28.29mA
2.94V     16.93mA    12.23mA    27.6mA
3.06V     16.92mA    12.23mA    24.35mA
3.96V     17.05mA    12.32mA    24.33mA
[Pullup]
|Voltage   I(typ)   I(min)   I(max)
-1.98V    1.62mA     998.6uA    4.005mA
-1.08V    6.133mA    3.566mA    9.235mA
-1.02V    6.531mA    3.947mA    18.33mA
-960mV    11.63mA    4.346mA    30.19mA
-900mV    18.95mA    5.088mA    32.31mA
-840mV    22.23mA    8.438mA    31.4mA
-720mV    21.25mA    15.95mA    28.6mA
-600mV    18.53mA    16.91mA    25.01mA
240mV     -5.967mA   -5.552mA   -8.574mA
900mV     -15.51mA   -14.17mA   -23.49mA
1.68V     -17.49mA   -15.7mA    -27.77mA
3.96V     -18.27mA   -16.36mA   -29.03mA
[GND_clamp]
|Voltage   I(typ)   I(min)   I(max)
-1.98V    -1.861A    -1.524A    -2.333A
-1.14V    -366mA     -404.8mA   -340.6mA
-1.08V    -268.7mA   -331.9mA   -213.6mA
-1.02V    -175.9mA   -260.7mA   -99.61mA
-960mV    -91.54mA   -192mA     -24.26mA
-900mV    -30.77mA   -127.1mA   -3.42mA
-840mV    -5.96mA    -68.91mA   -1.328mA
-780mV    -1.308mA   -27.16mA   -908.9uA
-720mV    -590.1uA   -7.525mA   -630.1uA
-660mV    -358.7uA   -1.804mA   -403.9uA
-420mV    -15.5uA    -34.36uA   -9.716uA
3.96V     0A         0A         0A
[POWER_clamp]
|Voltage   I(typ)   I(min)   I(max)
-1.98V    10.29A     9.986A     10.79A
-1.2V     2.598A     3.277A     2.158A
-1.14V    2.012A     2.764A     1.504A
-1.08V    1.429A     2.253A     855.2mA
-1.02V    851mA      1.743A     310.4mA
-960mV    354.2mA    1.236A     58.61mA
-900mV    89.61mA    734.2mA    15.24mA
-840mV    19.5mA     326mA      9.554mA
-780mV    7.508mA    104.4mA    6.926mA
-720mV    4.523mA    28.33mA    4.778mA
-660mV    2.875mA    8.601mA    2.988mA
3.96V     0A         0A         0A
[Ramp]
| variable   typ   min   max
dV/dt_r  0.8441/1.1037n   0.7874/1.7012n   1.0018/0.6085n
dV/dt_f  0.8911/0.9883n   0.7786/1.7538n   1.0321/0.5651n
R_load = 0.1550k
[Rising Waveform]
R_fixture= 0.1550k
V_fixture= 0.0
V_fixture_min= 0.0
V_fixture_max= 0.0
|time   V(typ)   V(min)   V(max)
0s        513.4pV    165.8nV    14.19pV
1.978ns   -9.171mV   210.8uV    24.02mV
2.864ns   9.372mV    -7.299mV   1.357V
3.179ns   86.63mV    -14.48mV   1.519V
3.723ns   508.5mV    -22.97mV   1.609V
4.22ns    940.9mV    10.77mV    1.639V
4.845ns   1.215V     134.3mV    1.655V
6.51ns    1.368V     954.3mV    1.667V
7.606ns   1.39V      1.167V     1.669V
18.06ns   1.407V     1.312V     1.67V
[Rising Waveform]
R_fixture= 0.1550k
V_fixture= 1.8000
V_fixture_min= 1.7100
V_fixture_max= 1.9800
|time   V(typ)   V(min)   V(max)
0s        314.8mV    411.2mV    259.8mV
1.402ns   315.2mV    411.1mV    302.6mV
1.698ns   313.1mV    411.1mV    1.143V
2.112ns   411mV      411.4mV    1.678V
2.393ns   1.091V     410.3mV    1.897V
2.646ns   1.382V     410.4mV    1.951V
3.148ns   1.647V     534mV      1.972V
3.853ns   1.778V     1.432V     1.977V
4.889ns   1.796V     1.662V     1.979V
18.06ns   1.8V       1.71V      1.98V
[Falling Waveform]
R_fixture= 0.1550k
V_fixture= 0.0
V_fixture_min= 0.0
V_fixture_max= 0.0
|time   V(typ)   V(min)   V(max)
0s        1.407V     1.313V     1.67V
1.073ns   1.409V     1.313V     1.595V
1.19ns    1.407V     1.313V     1.458V
1.435ns   1.357V     1.315V     773.8mV
1.59ns    1.263V     1.316V     510.5mV
2.047ns   462mV      1.269V     135.1mV
2.414ns   229.8mV    1.051V     31.17mV
3.099ns   55.83mV    254.4mV    7.319mV
4.294ns   7.635mV    43.98mV    1.393mV
18.06ns   24.09uV    50.88uV    15.96uV
[Falling Waveform]
R_fixture= 0.1550k
V_fixture= 1.8000
V_fixture_min= 1.7100
V_fixture_max= 1.9800
|time   V(typ)   V(min)   V(max)
0s        1.8V       1.71V      1.98V
1.867ns   1.833V     1.719V     1.98V
2.1ns     1.848V     1.724V     1.729V
2.725ns   1.8V       1.742V     597.6mV
3.59ns    1.151V     1.729V     329.9mV
4.055ns   709.7mV    1.687V     298.1mV
4.567ns   509.6mV    1.517V     280.9mV
5.96ns    367.7mV    813.6mV    264.9mV
7.225ns   335mV      564.3mV    261.5mV
18.06ns   314.9mV    412.3mV    259.9mV
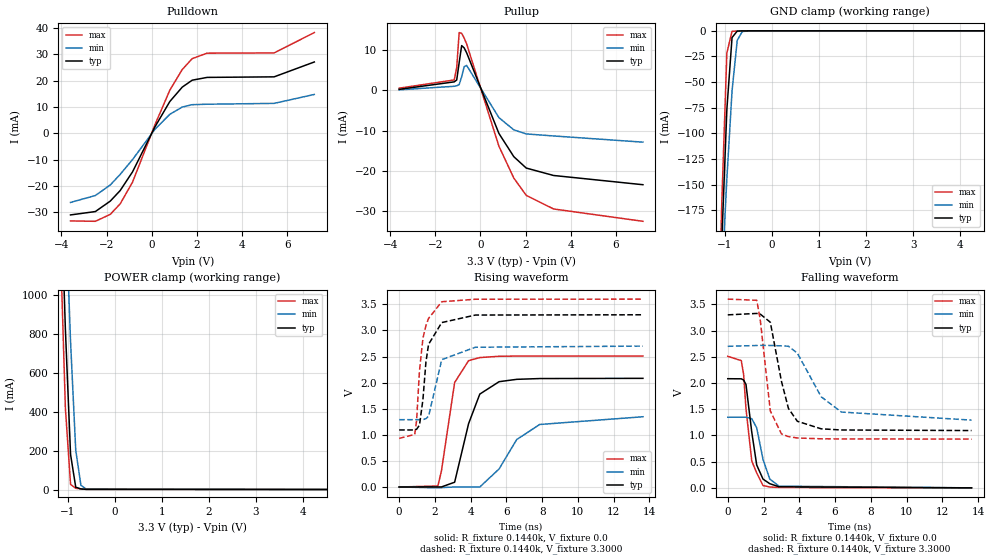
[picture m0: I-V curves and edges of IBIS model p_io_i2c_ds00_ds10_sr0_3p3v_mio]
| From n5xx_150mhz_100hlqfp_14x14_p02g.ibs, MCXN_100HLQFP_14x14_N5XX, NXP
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[Model] p_io_i2c_ds00_ds10_sr0_3p3v_mio
|   Model p_io_i2c_ds00_ds10_sr0_3p3v_mio
| This model was characterised for following simulation conditions:
| External (pad) voltage:
|   - Typ: 3.3V,   - Min: 2.7V,   - Max: 3.6V
| Library cells for typ/min/max conditions are connected as defined below:
|  pad - External Pad
|  ipp_do_lv - Core Input
|  ipp_obe_lv - Output Buffer Enable
|  IOGC - NC
|  REFH3V3 - REFH3V3
|  REFL3V3 - REFL3V3
|  ZI - NC
|  abut_ncal_vddio[1] - vddio
|  abut_ncal_vddio[2] - vddio
|  abut_ncal_vddio[3] - vssio
|  abut_ncal_vddio[4] - vddio
|  abut_ncal_vddio[5] - vddio
|  abut_ncal_vddio[6] - vssio
|  abut_pcal_vddio[1] - vssio
|  abut_pcal_vddio[2] - vssio
|  abut_pcal_vddio[3] - vddio
|  abut_pcal_vddio[4] - vssio
|  abut_pcal_vddio[5] - vssio
|  abut_pcal_vddio[6] - vddio
|  ipp_do_1p8v - ipp_do_1p8v
|  ipp_dse_lv[0] - 0
|  ipp_dse_lv[1] - 0
|  ipp_eftd_lv - NC
|  ipp_ina_mux_vddio - NC
|  ipp_ina_mux_vddio[0] - NC
|  ipp_ina_mux_vddio[1] - NC
|  ipp_ina_r0_vddio - NC
|  ipp_ina_r0a_vddio - NC
|  ipp_ina_r0b_vddio - NC
|  ipp_ina_r0c_vddio - NC
|  ipp_ina_r0d_vddio - NC
|  ipp_ina_r0e_vddio - NC
|  ipp_ina_r0f_vddio - NC
|  ipp_ina_r300_vddio - NC
|  ipp_ina_r300a_vddio - NC
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Model_type I/O
Polarity   Non-Inverting
Enable   Active-High
Vinl =   0.9900V
Vinh =   2.3100V
Vmeas =  1.6500V
Cref =   30.0000pF
Rref =   1.0000M
Vref =   3.3000V
C_comp   1.4149pF   1.3702pF   1.4746pF
|C_comp_pullup   0.5854pF   0.6307pF   0.5568pF
|C_comp_pulldown   0.7312pF   0.7415pF   0.7171pF
[Model Spec]
| variable   typ   min   max
Vinh   2.3100V   1.8900V   2.5200V
Vinl   0.9900V   0.8100V   1.0800V
[Temperature Range]   25.0000   0.1250k   -40.0000
[Voltage Range]   3.3000V   2.7000V   3.6000V
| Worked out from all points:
|   slope of the pulldown table from 0 to 0.495 V, typ, clamps not added: 61.3 ohm
|   slope of the pullup table from 0 to 0.495 V, typ, clamps not added: 71.7 ohm
|   GND clamp passes 1 mA (typ) near -0.75 V on its own axis
|   POWER clamp passes 1 mA (typ) near -0.57 V on its own axis
|   rising waveform, R_fixture 0.1440k, V_fixture 0.0: 20-80 % time 949ps typ, 1.73ns min, 658ps max; typ from 0 V to 2.08 V
|   rising waveform, R_fixture 0.1440k, V_fixture 3.3000: 20-80 % time 452ps typ, 482ps min, 463ps max; typ from 1.09 V to 3.3 V
|   falling waveform, R_fixture 0.1440k, V_fixture 0.0: 20-80 % time 456ps typ, 538ps min, 424ps max; typ from 2.08 V to 0 V
|   falling waveform, R_fixture 0.1440k, V_fixture 3.3000: 20-80 % time 791ps typ, 1.54ns min, 519ps max; typ from 3.3 V to 1.09 V
[Pulldown]
|Voltage   I(typ)   I(min)   I(max)
-3.6V     -30.97mA   -26.22mA   -33.25mA
-2.5V     -29.69mA   -23.6mA    -33.39mA
-1.84V    -25.73mA   -19.61mA   -30.76mA
-1.4V     -21.71mA   -15.56mA   -26.77mA
-850mV    -14.57mA   -9.916mA   -18.47mA
140mV     2.472mA    1.548mA    3.283mA
800mV     12.12mA    7.253mA    16.41mA
1.35V     17.58mA    10.01mA    24.26mA
1.79V     20.21mA    10.91mA    28.4mA
2.45V     21.27mA    11.08mA    30.48mA
5.42V     21.48mA    11.4mA     30.56mA
7.2V      27.13mA    14.79mA    38.3mA
[Pullup]
|Voltage   I(typ)   I(min)   I(max)
-3.6V     265.1uA    141.9uA    552.1uA
-1.16V    2.117mA    1.022mA    2.595mA
-1.05V    2.581mA    1.145mA    5.627mA
-940mV    6.922mA    1.451mA    14.34mA
-830mV    11.11mA    3.398mA    14.14mA
-720mV    10.54mA    5.878mA    12.98mA
-610mV    9.33mA     6.194mA    11.53mA
820mV     -10.67mA   -6.749mA   -13.83mA
1.48V     -16.43mA   -9.783mA   -21.74mA
2.03V     -19.25mA   -10.79mA   -26.01mA
3.24V     -21.09mA   -11.29mA   -29.39mA
7.2V      -23.38mA   -12.83mA   -32.45mA
[GND_clamp]
|Voltage   I(typ)   I(min)   I(max)
-3.6V     -4.327A    -3.181A    -5.901A
-1.18V    -358.9mA   -350.6mA   -379.3mA
-1.07V    -208.2mA   -244.2mA   -170.8mA
-960mV    -76.59mA   -144.3mA   -21.58mA
-850mV    -6.561mA   -58.74mA   -508.1uA
-740mV    -273.3uA   -9.382mA   -183.5uA
-630mV    -73.8uA    -593.1uA   -76.7uA
-410mV    -3.432uA   -9.016uA   -2.096uA
7.2V      0A         0A         0A
[POWER_clamp]
|Voltage   I(typ)   I(min)   I(max)
-3.6V     20.44A     18.76A     22.48A
-1.16V    1.647A     2.216A     1.289A
-1.05V    823.6mA    1.482A     419.2mA
-940mV    180.4mA    758.9mA    26.72mA
-830mV    12.56mA    202.9mA    6.794mA
-720mV    3.422mA    22.23mA    3.58mA
-610mV    1.373mA    2.923mA    1.344mA
7.2V      0A         0A         0A
[Ramp]
| variable   typ   min   max
dV/dt_r  1.2491/0.9491n   0.8076/1.7305n   1.5059/0.6578n
dV/dt_f  1.3239/0.7910n   0.8446/1.5368n   1.6015/0.5190n
R_load = 0.1440k
[Rising Waveform]
R_fixture= 0.1440k
V_fixture= 0.0
V_fixture_min= 0.0
V_fixture_max= 0.0
|time   V(typ)   V(min)   V(max)
0s        3.241nV    240.6nV    11.14nV
2.166ns   804.3uV    -16.54mV   19.1mV
2.364ns   771.9uV    -12.09mV   302.2mV
3.105ns   91.45mV    720.8uV    2.002V
3.886ns   1.214V     -496.7uV   2.421V
4.512ns   1.78V      -172.4uV   2.48V
5.593ns   2.018V     346mV      2.505V
6.575ns   2.063V     908.4mV    2.509V
7.863ns   2.078V     1.198V     2.51V
13.64ns   2.082V     1.346V     2.51V
[Rising Waveform]
R_fixture= 0.1440k
V_fixture= 3.3000
V_fixture_min= 2.7000
V_fixture_max= 3.6000
|time   V(typ)   V(min)   V(max)
0s        1.093V     1.29V      930.6mV
872.3ps   1.093V     1.29V      1.008V
975.6ps   1.106V     1.29V      1.267V
1.138ns   1.184V     1.29V      2.227V
1.33ns    1.671V     1.291V     2.847V
1.499ns   2.395V     1.309V     3.093V
1.647ns   2.734V     1.357V     3.231V
2.385ns   3.151V     2.441V     3.55V
4.266ns   3.295V     2.678V     3.598V
13.64ns   3.3V       2.7V       3.6V
[Falling Waveform]
R_fixture= 0.1440k
V_fixture= 0.0
V_fixture_min= 0.0
V_fixture_max= 0.0
|time   V(typ)   V(min)   V(max)
0s        2.082V     1.348V     2.51V
756.7ps   2.08V      1.348V     2.427V
888.2ps   2.056V     1.347V     2.16V
1.019ns   1.973V     1.348V     1.514V
1.343ns   1.062V     1.319V     511.8mV
1.619ns   435.8mV    1.144V     284.6mV
1.972ns   167.3mV    544.3mV    43.97mV
2.35ns    79.61mV    168.1mV    16.53mV
2.868ns   20.57mV    32.26mV    7.442mV
13.64ns   5.688uV    51.39uV    959.6nV
[Falling Waveform]
R_fixture= 0.1440k
V_fixture= 3.3000
V_fixture_min= 2.7000
V_fixture_max= 3.6000
|time   V(typ)   V(min)   V(max)
0s        3.3V       2.7V       3.6V
1.621ns   3.327V     2.715V     3.578V
1.812ns   3.316V     2.718V     3.221V
2.381ns   3.159V     2.716V     1.467V
3.004ns   2.032V     2.708V     1.029V
3.396ns   1.514V     2.702V     977.1mV
3.894ns   1.27V      2.569V     951.5mV
5.227ns   1.126V     1.737V     935.6mV
6.358ns   1.104V     1.446V     933.1mV
13.64ns   1.093V     1.292V     930.8mV
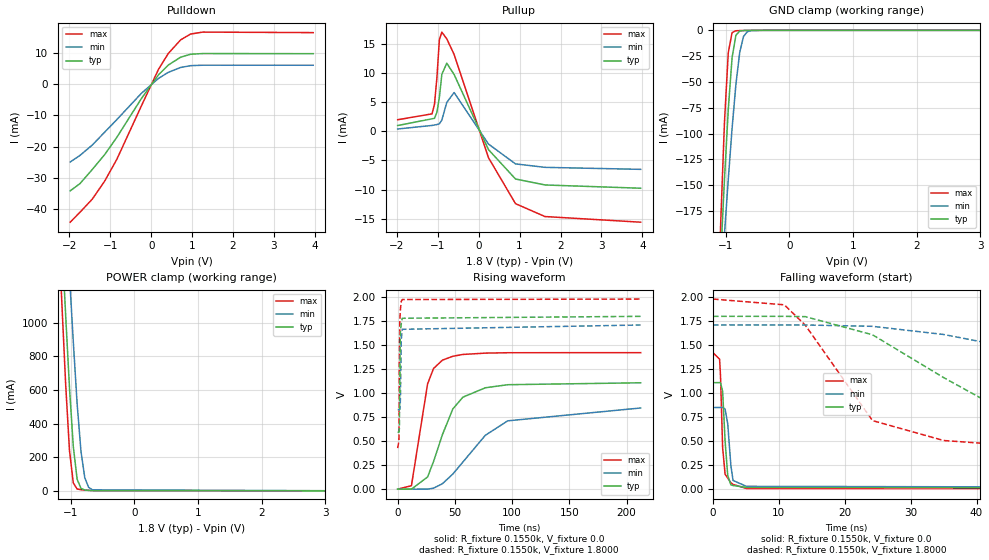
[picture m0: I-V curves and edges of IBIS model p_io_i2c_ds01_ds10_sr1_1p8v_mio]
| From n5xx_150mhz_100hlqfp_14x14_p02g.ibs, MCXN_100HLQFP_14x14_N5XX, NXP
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[Model] p_io_i2c_ds01_ds10_sr1_1p8v_mio
|   Model p_io_i2c_ds01_ds10_sr1_1p8v_mio
| This model was characterised for following simulation conditions:
| External (pad) voltage:
|   - Typ: 1.8V,   - Min: 1.71V,   - Max: 1.98V
| Library cells for typ/min/max conditions are connected as defined below:
|  pad - External Pad
|  ipp_do_lv - Core Input
|  ipp_obe_lv - Output Buffer Enable
|  IOGC - NC
|  REFH3V3 - REFH3V3
|  REFL3V3 - REFL3V3
|  ZI - NC
|  abut_ncal_vddio[1] - vssio vddio vddio
|  abut_ncal_vddio[2] - vddio vddio vssio
|  abut_ncal_vddio[3] - vddio
|  abut_ncal_vddio[4] - vssio vddio vddio
|  abut_ncal_vddio[5] - vddio vddio vssio
|  abut_ncal_vddio[6] - vddio
|  abut_pcal_vddio[1] - vssio
|  abut_pcal_vddio[2] - vddio vssio vddio
|  abut_pcal_vddio[3] - vssio
|  abut_pcal_vddio[4] - vssio
|  abut_pcal_vddio[5] - vddio vssio vddio
|  abut_pcal_vddio[6] - vssio
|  ipp_do_1p8v - ipp_do_1p8v
|  ipp_dse_lv[0] - vdd_lv
|  ipp_dse_lv[1] - 0
|  ipp_eftd_lv - NC
|  ipp_ina_mux_vddio - NC
|  ipp_ina_mux_vddio[0] - NC
|  ipp_ina_mux_vddio[1] - NC
|  ipp_ina_r0_vddio - NC
|  ipp_ina_r0a_vddio - NC
|  ipp_ina_r0b_vddio - NC
|  ipp_ina_r0c_vddio - NC
|  ipp_ina_r0d_vddio - NC
|  ipp_ina_r0e_vddio - NC
|  ipp_ina_r0f_vddio - NC
|  ipp_ina_r300_vddio - NC
|  ipp_ina_r300a_vddio - NC
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Model_type I/O
Polarity   Non-Inverting
Enable   Active-High
Vinl =   0.5400V
Vinh =   1.2600V
Vmeas =  0.9000V
Cref =   30.0000pF
Rref =   1.0000M
Vref =   1.8000V
C_comp   1.4328pF   1.3910pF   1.4871pF
|C_comp_pullup   0.6298pF   0.6731pF   0.5895pF
|C_comp_pulldown   0.7019pF   0.7080pF   0.7043pF
[Model Spec]
| variable   typ   min   max
Vinh   1.2600V   1.1970V   1.3860V
Vinl   0.5400V   0.5130V   0.5940V
[Temperature Range]   25.0000   0.1250k   -40.0000
[Voltage Range]   1.8000V   1.7100V   1.9800V
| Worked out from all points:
|   slope of the pulldown table from 0 to 0.27 V, typ, clamps not added: 62.5 ohm
|   slope of the pullup table from 0 to 0.27 V, typ, clamps not added: 77.5 ohm
|   GND clamp passes 1 mA (typ) near -0.78 V on its own axis
|   POWER clamp passes 1 mA (typ) near -0.58 V on its own axis
|   rising waveform, R_fixture 0.1550k, V_fixture 0.0: 20-80 % time 21.7ns typ, 40.7ns min, 11ns max; typ from 0 V to 1.11 V
|   rising waveform, R_fixture 0.1550k, V_fixture 1.8000: 20-80 % time 488ps typ, 580ps min, 475ps max; typ from 0.593 V to 1.8 V
|   falling waveform, R_fixture 0.1550k, V_fixture 0.0: 20-80 % time 489ps typ, 596ps min, 434ps max; typ from 1.11 V to 0 V
|   falling waveform, R_fixture 0.1550k, V_fixture 1.8000: 20-80 % time 18.9ns typ, 36.9ns min, 9.38ns max; typ from 1.8 V to 0.593 V
[Pulldown]
|Voltage   I(typ)   I(min)   I(max)
-1.98V    -34.2mA    -24.94mA   -44.24mA
-1.74V    -31.86mA   -22.83mA   -41.05mA
-1.44V    -27.34mA   -19.51mA   -36.85mA
-1.14V    -22.63mA   -15.42mA   -31.14mA
-840mV    -17.04mA   -11.36mA   -24.09mA
-240mV    -4.613mA   -2.936mA   -6.972mA
180mV     3.031mA    1.875mA    4.796mA
420mV     6.16mA     3.813mA    9.881mA
720mV     8.658mA    5.36mA     14.2mA
960mV     9.581mA    5.932mA    16.06mA
1.26V     9.826mA    6.085mA    16.7mA
3.96V     9.775mA    6.071mA    16.53mA
[Pullup]
|Voltage   I(typ)   I(min)   I(max)
-1.98V    993.6uA    401.3uA    1.989mA
-1.14V    2.152mA    1.013mA    3.004mA
-1.08V    2.231mA    1.087mA    4.647mA
-1.02V    3.272mA    1.164mA    9.289mA
-960mV    5.867mA    1.291mA    15.78mA
-900mV    9.784mA    1.928mA    17.04mA
-780mV    11.7mA     4.959mA    15.88mA
-600mV    9.753mA    6.662mA    13.2mA
240mV     -3.145mA   -2.189mA   -4.532mA
900mV     -8.182mA   -5.59mA    -12.42mA
1.62V     -9.207mA   -6.184mA   -14.63mA
3.96V     -9.769mA   -6.528mA   -15.6mA
[GND_clamp]
|Voltage   I(typ)   I(min)   I(max)
-1.98V    -1.586A    -1.229A    -2.1A
-1.08V    -221.4mA   -253.6mA   -188.5mA
-1.02V    -144.6mA   -197.7mA   -89.32mA
-960mV    -76.59mA   -144.3mA   -21.58mA
-900mV    -26.43mA   -94.89mA   -2.183mA
-840mV    -4.754mA   -52.29mA   -428.7uA
-780mV    -708.9uA   -21.31mA   -240uA
-720mV    -194.5uA   -5.864mA   -159.9uA
-660mV    -97.62uA   -1.274mA   -100.6uA
-600mV    -55.49uA   -286.4uA   -56.47uA
-420mV    -4.265uA   -10.7uA    -2.74uA
3.96V     0A         0A         0A
[POWER_clamp]
|Voltage   I(typ)   I(min)   I(max)
-1.98V    7.929A     7.752A     8.366A
-1.2V     1.949A     2.483A     1.628A
-1.14V    1.495A     2.081A     1.12A
-1.08V    1.044A     1.68A      633.7mA
-1.02V    613.2mA    1.282A     240.4mA
-960mV    264mA      886.2mA    47.43mA
-900mV    69.94mA    519.6mA    11.58mA
-840mV    15.1mA     237.3mA    7.049mA
-780mV    5.589mA    78.54mA    5.099mA
-720mV    3.316mA    21.56mA    3.521mA
-660mV    2.102mA    6.487mA    2.205mA
3.96V     0A         0A         0A
[Ramp]
| variable   typ   min   max
dV/dt_r  0.6651/21.6842n   0.5074/40.6976n   0.8530/11.0016n
dV/dt_f  0.7241/18.9247n   0.5266/36.9045n   0.9315/9.3824n
R_load = 0.1550k
[Rising Waveform]
R_fixture= 0.1550k
V_fixture= 0.0
V_fixture_min= 0.0
V_fixture_max= 0.0
|time   V(typ)   V(min)   V(max)
0s        511.6pV    206.6nV    17.81pV
12.03ns   -44.49uV   -21uV      35.85mV
26.15ns   127.1mV    279.3uV    1.097V
31.35ns   288.4mV    9.924mV    1.257V
39.13ns   568.5mV    56.91mV    1.344V
48.13ns   834.5mV    156.9mV    1.384V
56.94ns   958mV      281.9mV    1.403V
76.59ns   1.056V     561.2mV    1.417V
96.18ns   1.088V     711.8mV    1.421V
212.3ns   1.108V     845.6mV    1.422V
[Rising Waveform]
R_fixture= 0.1550k
V_fixture= 1.8000
V_fixture_min= 1.7100
V_fixture_max= 1.9800
|time   V(typ)   V(min)   V(max)
0s        593mV      828.3mV    427.5mV
1.116ns   592.7mV    828.3mV    504.2mV
1.224ns   593.4mV    828.3mV    641.6mV
1.502ns   635.5mV    828.3mV    1.395V
1.871ns   1.054V     829.8mV    1.74V
2.118ns   1.45V      850.2mV    1.811V
2.411ns   1.643V     942.5mV    1.874V
3.139ns   1.725V     1.56V      1.956V
4.038ns   1.78V      1.665V     1.975V
212.3ns   1.8V       1.71V      1.98V
[Falling Waveform]
R_fixture= 0.1550k
V_fixture= 0.0
V_fixture_min= 0.0
V_fixture_max= 0.0
|time   V(typ)   V(min)   V(max)
0s        1.109V     850.5mV    1.422V
1.004ns   1.11V      850.4mV    1.353V
1.143ns   1.107V     850.5mV    1.174V
1.462ns   1.018V     852.4mV    432.3mV
1.836ns   502.7mV    833.3mV    155.6mV
2.234ns   143mV      682.6mV    116.1mV
2.714ns   45.62mV    245.6mV    66.83mV
3.041ns   37.81mV    91.03mV    49.66mV
5.072ns   18.55mV    29.31mV    7.328mV
212.3ns   159.3nV    2.397uV    29.73nV
[Falling Waveform]
R_fixture= 0.1550k
V_fixture= 1.8000
V_fixture_min= 1.7100
V_fixture_max= 1.9800
|time   V(typ)   V(min)   V(max)
0s        1.8V       1.71V      1.98V
10.82ns   1.8V       1.71V      1.92V
14.01ns   1.797V     1.71V      1.708V
24.21ns   1.608V     1.696V     714.2mV
35.01ns   1.162V     1.611V     506.7mV
42.25ns   887.8mV    1.515V     471.1mV
50.3ns    753.3mV    1.384V     451.7mV
69.45ns   650.5mV    1.08V      434.2mV
88.17ns   617.7mV    952.5mV    429.5mV
212.3ns   593.1mV    832.3mV    427.5mV
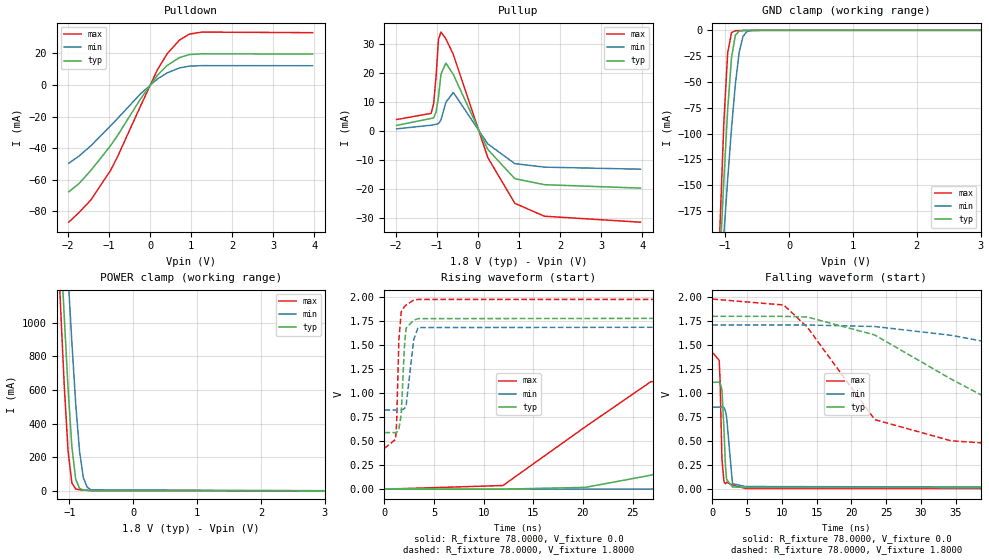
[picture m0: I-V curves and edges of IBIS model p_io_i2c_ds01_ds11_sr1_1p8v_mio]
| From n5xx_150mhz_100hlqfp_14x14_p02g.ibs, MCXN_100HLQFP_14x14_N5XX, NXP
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[Model] p_io_i2c_ds01_ds11_sr1_1p8v_mio
|   Model p_io_i2c_ds01_ds11_sr1_1p8v_mio
| This model was characterised for following simulation conditions:
| External (pad) voltage:
|   - Typ: 1.8V,   - Min: 1.71V,   - Max: 1.98V
| Library cells for typ/min/max conditions are connected as defined below:
|  pad - External Pad
|  ipp_do_lv - Core Input
|  ipp_obe_lv - Output Buffer Enable
|  IOGC - NC
|  REFH3V3 - REFH3V3
|  REFL3V3 - REFL3V3
|  ZI - NC
|  abut_ncal_vddio[1] - vssio vddio vddio
|  abut_ncal_vddio[2] - vddio vddio vssio
|  abut_ncal_vddio[3] - vddio
|  abut_ncal_vddio[4] - vssio vddio vddio
|  abut_ncal_vddio[5] - vddio vddio vssio
|  abut_ncal_vddio[6] - vddio
|  abut_pcal_vddio[1] - vssio
|  abut_pcal_vddio[2] - vddio vssio vddio
|  abut_pcal_vddio[3] - vssio
|  abut_pcal_vddio[4] - vssio
|  abut_pcal_vddio[5] - vddio vssio vddio
|  abut_pcal_vddio[6] - vssio
|  ipp_do_1p8v - ipp_do_1p8v
|  ipp_dse_lv[0] - vdd_lv
|  ipp_dse_lv[1] - vdd_lv
|  ipp_eftd_lv - NC
|  ipp_ina_mux_vddio - NC
|  ipp_ina_mux_vddio[0] - NC
|  ipp_ina_mux_vddio[1] - NC
|  ipp_ina_r0_vddio - NC
|  ipp_ina_r0a_vddio - NC
|  ipp_ina_r0b_vddio - NC
|  ipp_ina_r0c_vddio - NC
|  ipp_ina_r0d_vddio - NC
|  ipp_ina_r0e_vddio - NC
|  ipp_ina_r0f_vddio - NC
|  ipp_ina_r300_vddio - NC
|  ipp_ina_r300a_vddio - NC
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Model_type I/O
Polarity   Non-Inverting
Enable   Active-High
Vinl =   0.5400V
Vinh =   1.2600V
Vmeas =  0.9000V
Cref =   30.0000pF
Rref =   1.0000M
Vref =   1.8000V
C_comp   1.4328pF   1.3910pF   1.4871pF
|C_comp_pullup   0.6297pF   0.6730pF   0.5894pF
|C_comp_pulldown   0.7020pF   0.7080pF   0.7044pF
[Model Spec]
| variable   typ   min   max
Vinh   1.2600V   1.1970V   1.3860V
Vinl   0.5400V   0.5130V   0.5940V
[Temperature Range]   25.0000   0.1250k   -40.0000
[Voltage Range]   1.8000V   1.7100V   1.9800V
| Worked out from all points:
|   slope of the pulldown table from 0 to 0.27 V, typ, clamps not added: 31.3 ohm
|   slope of the pullup table from 0 to 0.27 V, typ, clamps not added: 38.8 ohm
|   GND clamp passes 1 mA (typ) near -0.78 V on its own axis
|   POWER clamp passes 1 mA (typ) near -0.58 V on its own axis
|   rising waveform, R_fixture 78.0000, V_fixture 0.0: 20-80 % time 22.3ns typ, 41.7ns min, 11.3ns max; typ from 0 V to 1.11 V
|   rising waveform, R_fixture 78.0000, V_fixture 1.8000: 20-80 % time 335ps typ, 461ps min, 269ps max; typ from 0.59 V to 1.8 V
|   falling waveform, R_fixture 78.0000, V_fixture 0.0: 20-80 % time 369ps typ, 500ps min, 286ps max; typ from 1.11 V to 0 V
|   falling waveform, R_fixture 78.0000, V_fixture 1.8000: 20-80 % time 18.7ns typ, 36.6ns min, 9.32ns max; typ from 1.8 V to 0.59 V
[Pulldown]
|Voltage   I(typ)   I(min)   I(max)
-1.98V    -67.59mA   -49.58mA   -86.84mA
-1.74V    -62.7mA    -45.23mA   -80.98mA
-1.44V    -54.1mA    -38.51mA   -72.8mA
-960mV    -38.41mA   -25.86mA   -54.05mA
-780mV    -31.57mA   -20.97mA   -44.79mA
-240mV    -9.218mA   -5.869mA   -13.93mA
180mV     6.058mA    3.748mA    9.583mA
420mV     12.31mA    7.625mA    19.75mA
720mV     17.31mA    10.72mA    28.38mA
960mV     19.16mA    11.86mA    32.11mA
1.26V     19.65mA    12.17mA    33.39mA
3.96V     19.52mA    12.12mA    33.02mA
[Pullup]
|Voltage   I(typ)   I(min)   I(max)
-1.98V    1.974mA    801.8uA    4.007mA
-1.14V    4.389mA    2.051mA    6.122mA
-1.08V    4.553mA    2.205mA    9.344mA
-1.02V    6.58mA     2.365mA    18.71mA
-960mV    11.81mA    2.599mA    31.64mA
-900mV    19.63mA    3.875mA    34.08mA
-780mV    23.4mA     9.952mA    31.75mA
-600mV    19.5mA     13.32mA    26.39mA
240mV     -6.288mA   -4.377mA   -9.06mA
900mV     -16.36mA   -11.18mA   -24.83mA
1.62V     -18.41mA   -12.37mA   -29.26mA
3.96V     -19.59mA   -13.08mA   -31.31mA
[GND_clamp]
|Voltage   I(typ)   I(min)   I(max)
-1.98V    -1.586A    -1.229A    -2.1A
-1.08V    -221.4mA   -253.6mA   -188.5mA
-1.02V    -144.6mA   -197.7mA   -89.32mA
-960mV    -76.59mA   -144.3mA   -21.58mA
-900mV    -26.43mA   -94.89mA   -2.183mA
-840mV    -4.754mA   -52.29mA   -428.7uA
-780mV    -708.9uA   -21.31mA   -240uA
-720mV    -194.5uA   -5.864mA   -159.9uA
-660mV    -97.62uA   -1.274mA   -100.6uA
-600mV    -55.49uA   -286.4uA   -56.47uA
-420mV    -4.265uA   -10.7uA    -2.74uA
3.96V     0A         0A         0A
[POWER_clamp]
|Voltage   I(typ)   I(min)   I(max)
-1.98V    7.929A     7.752A     8.366A
-1.2V     1.949A     2.483A     1.628A
-1.14V    1.495A     2.081A     1.12A
-1.08V    1.044A     1.68A      633.7mA
-1.02V    613.2mA    1.282A     240.4mA
-960mV    264mA      886.2mA    47.43mA
-900mV    69.94mA    519.6mA    11.58mA
-840mV    15.1mA     237.3mA    7.049mA
-780mV    5.589mA    78.54mA    5.099mA
-720mV    3.316mA    21.56mA    3.521mA
-660mV    2.102mA    6.487mA    2.205mA
3.96V     0A         0A         0A
[Ramp]
| variable   typ   min   max
dV/dt_r  0.6672/22.2590n   0.5096/41.7296n   0.8548/11.3154n
dV/dt_f  0.7261/18.7286n   0.5294/36.5685n   0.9329/9.3211n
R_load = 78.0000
[Rising Waveform]
R_fixture= 78.0000
V_fixture= 0.0
V_fixture_min= 0.0
V_fixture_max= 0.0
|time   V(typ)   V(min)   V(max)
0s        293.7pV    104.7nV    10.7pV
11.94ns   -36.03uV   -8.428uV   37.92mV
20.26ns   18.87mV    35.18uV    650.7mV
26.81ns   144.7mV    642.4uV    1.117V
39.7ns    576.4mV    63.35mV    1.346V
48.78ns   837.8mV    163.5mV    1.387V
57.99ns   962.8mV    291.8mV    1.406V
78.77ns   1.061V     578.4mV    1.42V
99.84ns   1.093V     725.1mV    1.424V
215.6ns   1.112V     849.3mV    1.425V
[Rising Waveform]
R_fixture= 78.0000
V_fixture= 1.8000
V_fixture_min= 1.7100
V_fixture_max= 1.9800
|time   V(typ)   V(min)   V(max)
0s        589.7mV    824.3mV    425.2mV
1.125ns   589.2mV    824.3mV    518.9mV
1.227ns   590.7mV    824.3mV    686.5mV
1.454ns   625.4mV    824.2mV    1.553V
1.689ns   776.7mV    823.8mV    1.847V
2.009ns   1.48V      837.4mV    1.901V
2.182ns   1.677V     869.3mV    1.917V
2.948ns   1.76V      1.556V     1.97V
3.379ns   1.776V     1.683V     1.976V
215.6ns   1.8V       1.71V      1.98V
[Falling Waveform]
R_fixture= 78.0000
V_fixture= 0.0
V_fixture_min= 0.0
V_fixture_max= 0.0
|time   V(typ)   V(min)   V(max)
0s        1.112V     854.3mV    1.425V
980.1ps   1.115V     854.2mV    1.342V
1.103ns   1.111V     854.6mV    1.153V
1.378ns   1.037V     856.9mV    313.2mV
1.676ns   615.2mV    849.2mV    74.53mV
1.882ns   241.4mV    815.4mV    57.11mV
2.049ns   102.5mV    752.8mV    71.55mV
2.896ns   22.4mV     56.92mV    43.09mV
4.827ns   18.74mV    27.38mV    6.433mV
215.6ns   99.05nV    1.811uV    11.31nV
[Falling Waveform]
R_fixture= 78.0000
V_fixture= 1.8000
V_fixture_min= 1.7100
V_fixture_max= 1.9800
|time   V(typ)   V(min)   V(max)
0s        1.8V       1.71V      1.98V
10.28ns   1.8V       1.71V      1.918V
13.68ns   1.793V     1.71V      1.686V
23.37ns   1.606V     1.694V     724.5mV
34.33ns   1.148V     1.603V     504.2mV
41.24ns   884.4mV    1.51V      469.6mV
49.19ns   750.1mV    1.379V     449.8mV
67.62ns   648.5mV    1.08V      432.2mV
85.84ns   615.3mV    951.1mV    427.4mV
215.6ns   589.8mV    827.6mV    425.2mV
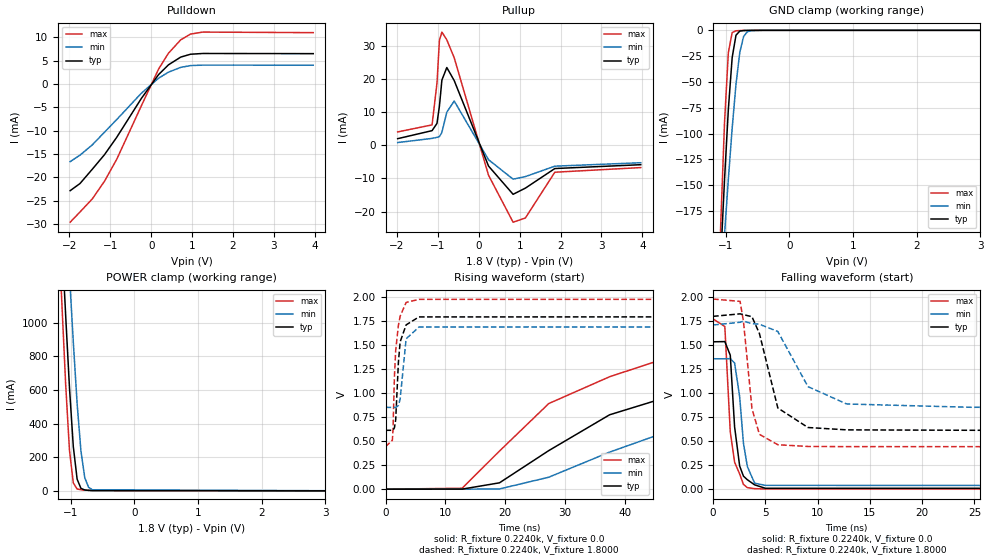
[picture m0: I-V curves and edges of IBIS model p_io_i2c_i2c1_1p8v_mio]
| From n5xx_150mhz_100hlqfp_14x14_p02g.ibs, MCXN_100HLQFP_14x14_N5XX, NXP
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[Model] p_io_i2c_i2c1_1p8v_mio
|   Model p_io_i2c_i2c1_1p8v_mio
| This model was characterised for following simulation conditions:
| External (pad) voltage:
|   - Typ: 1.8V,   - Min: 1.71V,   - Max: 1.98V
| Library cells for typ/min/max conditions are connected as defined below:
|  pad - External Pad
|  ipp_do_lv - Core Input
|  ipp_obe_lv - Output Buffer Enable
|  IOGC - NC
|  REFH3V3 - REFH3V3
|  REFL3V3 - REFL3V3
|  ZI - NC
|  abut_ncal_vddio[1] - vssio vddio vddio
|  abut_ncal_vddio[2] - vddio vddio vssio
|  abut_ncal_vddio[3] - vddio
|  abut_ncal_vddio[4] - vssio vddio vddio
|  abut_ncal_vddio[5] - vddio vddio vssio
|  abut_ncal_vddio[6] - vddio
|  abut_pcal_vddio[1] - vssio
|  abut_pcal_vddio[2] - vddio vssio vddio
|  abut_pcal_vddio[3] - vssio
|  abut_pcal_vddio[4] - vssio
|  abut_pcal_vddio[5] - vddio vssio vddio
|  abut_pcal_vddio[6] - vssio
|  ipp_do_1p8v - ipp_do_1p8v
|  ipp_eftd_lv - NC
|  ipp_i2c_lv - vdd_lv
|  ipp_ina_mux_vddio - NC
|  ipp_ina_mux_vddio[0] - NC
|  ipp_ina_mux_vddio[1] - NC
|  ipp_ina_r0_vddio - NC
|  ipp_ina_r0a_vddio - NC
|  ipp_ina_r0b_vddio - NC
|  ipp_ina_r0c_vddio - NC
|  ipp_ina_r0d_vddio - NC
|  ipp_ina_r0e_vddio - NC
|  ipp_ina_r0f_vddio - NC
|  ipp_ina_r300_vddio - NC
|  ipp_ina_r300a_vddio - NC
|  ipp_ina_r300b_vddio - NC
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Model_type I/O
Polarity   Non-Inverting
Enable   Active-High
Vinl =   0.5400V
Vinh =   1.2600V
Vmeas =  0.9000V
Cref =   30.0000pF
Rref =   1.0000M
Vref =   1.8000V
C_comp   1.4328pF   1.3910pF   1.4871pF
|C_comp_pullup   0.6295pF   0.6728pF   0.5892pF
|C_comp_pulldown   0.7022pF   0.7083pF   0.7046pF
[Model Spec]
| variable   typ   min   max
Vinh   1.2600V   1.1970V   1.3860V
Vinl   0.5400V   0.5130V   0.5940V
[Temperature Range]   25.0000   0.1250k   -40.0000
[Voltage Range]   1.8000V   1.7100V   1.9800V
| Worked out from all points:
|   slope of the pulldown table from 0 to 0.27 V, typ, clamps not added: 93.8 ohm
|   slope of the pullup table from 0 to 0.27 V, typ, clamps not added: 38.8 ohm
|   GND clamp passes 1 mA (typ) near -0.78 V on its own axis
|   POWER clamp passes 1 mA (typ) near -0.58 V on its own axis
|   rising waveform, R_fixture 0.2240k, V_fixture 0.0: 20-80 % time 38.9ns typ, 50.6ns min, 31.1ns max; typ from 0 V to 1.53 V
|   rising waveform, R_fixture 0.2240k, V_fixture 1.8000: 20-80 % time 698ps typ, 741ps min, 752ps max; typ from 0.613 V to 1.8 V
|   falling waveform, R_fixture 0.2240k, V_fixture 0.0: 20-80 % time 653ps typ, 752ps min, 628ps max; typ from 1.53 V to 0 V
|   falling waveform, R_fixture 0.2240k, V_fixture 1.8000: 20-80 % time 1.62ns typ, 2.78ns min, 877ps max; typ from 1.8 V to 0.613 V
[Pulldown]
|Voltage   I(typ)   I(min)   I(max)
-1.98V    -22.85mA   -16.63mA   -29.61mA
-1.74V    -21.32mA   -15.24mA   -27.42mA
-1.44V    -18.26mA   -13.04mA   -24.62mA
-1.14V    -15.12mA   -10.3mA    -20.81mA
-840mV    -11.38mA   -7.585mA   -16.08mA
-240mV    -3.077mA   -1.958mA   -4.652mA
180mV     2.022mA    1.25mA     3.2mA
420mV     4.109mA    2.543mA    6.592mA
720mV     5.775mA    3.575mA    9.468mA
960mV     6.391mA    3.957mA    10.71mA
1.26V     6.554mA    4.059mA    11.14mA
3.96V     6.52mA     4.05mA     11.02mA
[Pullup]
|Voltage   I(typ)   I(min)   I(max)
-1.98V    1.974mA    801.8uA    4.007mA
-1.14V    4.389mA    2.051mA    6.122mA
-1.02V    6.58mA     2.365mA    18.71mA
-960mV    11.81mA    2.599mA    31.64mA
-900mV    19.63mA    3.875mA    34.08mA
-780mV    23.4mA     9.952mA    31.75mA
-600mV    19.5mA     13.32mA    26.39mA
240mV     -6.288mA   -4.377mA   -9.06mA
840mV     -14.79mA   -10.23mA   -23.19mA
1.14V     -12.93mA   -9.456mA   -21.93mA
1.86V     -7.028mA   -6.313mA   -8.136mA
3.96V     -5.868mA   -5.275mA   -6.737mA
[GND_clamp]
|Voltage   I(typ)   I(min)   I(max)
-1.98V    -1.586A    -1.229A    -2.1A
-1.08V    -221.4mA   -253.6mA   -188.5mA
-1.02V    -144.6mA   -197.7mA   -89.32mA
-960mV    -76.59mA   -144.3mA   -21.58mA
-900mV    -26.43mA   -94.89mA   -2.183mA
-840mV    -4.754mA   -52.29mA   -428.7uA
-780mV    -708.9uA   -21.31mA   -240uA
-720mV    -194.5uA   -5.864mA   -159.9uA
-660mV    -97.62uA   -1.274mA   -100.6uA
-600mV    -55.49uA   -286.4uA   -56.47uA
-420mV    -4.265uA   -10.7uA    -2.74uA
3.96V     0A         0A         0A
[POWER_clamp]
|Voltage   I(typ)   I(min)   I(max)
-1.98V    7.929A     7.752A     8.366A
-1.2V     1.949A     2.483A     1.628A
-1.14V    1.495A     2.081A     1.12A
-1.08V    1.044A     1.68A      633.7mA
-1.02V    613.2mA    1.282A     240.4mA
-960mV    264mA      886.2mA    47.43mA
-900mV    69.94mA    519.6mA    11.58mA
-840mV    15.1mA     237.3mA    7.049mA
-780mV    5.589mA    78.54mA    5.099mA
-720mV    3.316mA    21.56mA    3.521mA
-660mV    2.102mA    6.487mA    2.205mA
3.96V     0A         0A         0A
[Ramp]
| variable   typ   min   max
dV/dt_r  0.9174/38.9196n   0.8026/50.6025n   1.0628/31.0535n
dV/dt_f  0.7121/1.6158n   0.5149/2.7784n   0.9223/0.8766n
R_load = 0.2240k
[Rising Waveform]
R_fixture= 0.2240k
V_fixture= 0.0
V_fixture_min= 0.0
V_fixture_max= 0.0
|time   V(typ)   V(min)   V(max)
0s        722.1pV    304.4nV    24.71pV
12.79ns   386.9uV    -65.74uV   9.4mV
19.04ns   65.94mV    1.813mV    396.6mV
27.28ns   401.6mV    124.5mV    891.7mV
37.45ns   774.7mV    385.8mV    1.171V
52.61ns   1.065V     721.3mV    1.482V
66.76ns   1.254V     920.7mV    1.662V
87.02ns   1.398V     1.091V     1.734V
242.6ns   1.519V     1.303V     1.769V
1us       1.529V     1.338V     1.771V
[Rising Waveform]
R_fixture= 0.2240k
V_fixture= 1.8000
V_fixture_min= 1.7100
V_fixture_max= 1.9800
|time   V(typ)   V(min)   V(max)
0s        613.2mV    851.8mV    442.8mV
1.14ns    613mV      851.8mV    509.8mV
1.251ns   614.2mV    851.8mV    626.4mV
1.483ns   639.4mV    851.8mV    1.174V
1.697ns   723.6mV    851.6mV    1.446V
2.15ns    1.323V     871.1mV    1.708V
2.441ns   1.534V     938.9mV    1.801V
3.439ns   1.711V     1.566V     1.945V
5.586ns   1.794V     1.689V     1.977V
1us       1.8V       1.71V      1.98V
[Falling Waveform]
R_fixture= 0.2240k
V_fixture= 0.0
V_fixture_min= 0.0
V_fixture_max= 0.0
|time   V(typ)   V(min)   V(max)
0s        1.535V     1.358V     1.773V
1.125ns   1.537V     1.358V     1.694V
1.646ns   1.395V     1.359V     597.2mV
2.059ns   650mV      1.314V     282mV
2.544ns   240.7mV    964.2mV    158.2mV
2.905ns   135.9mV    478.5mV    49.73mV
3.281ns   98.1mV     235.3mV    15.68mV
3.978ns   44.71mV    62.4mV     5.575mV
5.009ns   9.185mV    39.83mV    1.936mV
1us       107.8nV    732.2nV    22.49nV
[Falling Waveform]
R_fixture= 0.2240k
V_fixture= 1.8000
V_fixture_min= 1.7100
V_fixture_max= 1.9800
|time   V(typ)   V(min)   V(max)
0s        1.8V       1.71V      1.98V
2.584ns   1.826V     1.738V     1.956V
2.906ns   1.818V     1.75V      1.749V
3.722ns   1.796V     1.724V     838.6mV
4.436ns   1.621V     1.718V     570.9mV
6.195ns   845.6mV    1.642V     462.7mV
9.08ns    642.2mV    1.068V     444.8mV
12.79ns   617.6mV    887.1mV    443mV
24.69ns   613.3mV    852.8mV    442.8mV
1us       613.2mV    851.8mV    442.8mV
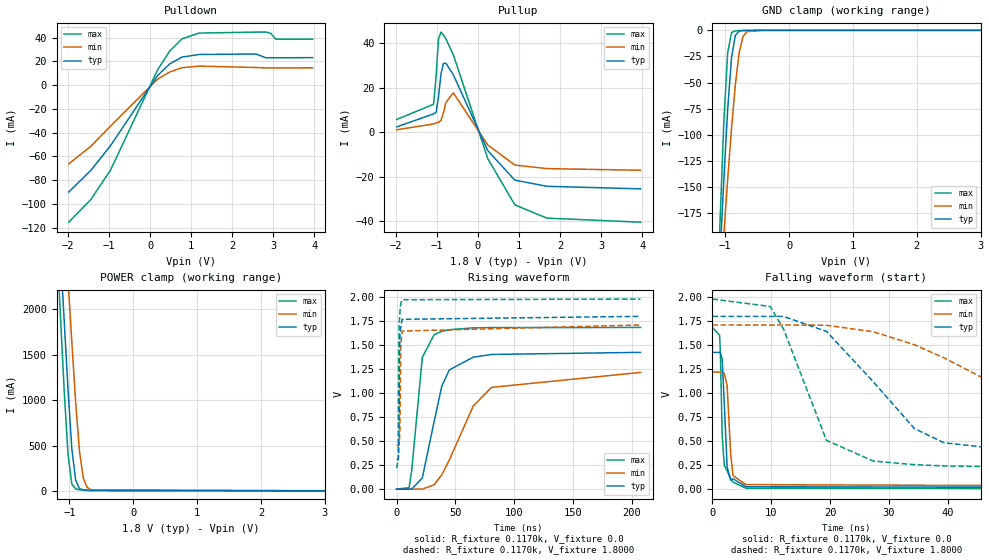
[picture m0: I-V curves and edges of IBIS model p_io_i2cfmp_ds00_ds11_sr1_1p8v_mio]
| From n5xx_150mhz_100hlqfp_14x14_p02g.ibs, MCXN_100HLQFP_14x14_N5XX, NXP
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[Model] p_io_i2cfmp_ds00_ds11_sr1_1p8v_mio
|   Model p_io_i2cfmp_ds00_ds11_sr1_1p8v_mio
| This model was characterised for following simulation conditions:
| External (pad) voltage:
|   - Typ: 1.8V,   - Min: 1.71V,   - Max: 1.98V
| Library cells for typ/min/max conditions are connected as defined below:
|  pad - External Pad
|  ipp_do_lv - Core Input
|  ipp_obe_lv - Output Buffer Enable
|  IOGC - NC
|  REFH3V3 - REFH3V3
|  REFL3V3 - REFL3V3
|  ZI - NC
|  abut_ncal_vddio[1] - vssio vddio vddio
|  abut_ncal_vddio[2] - vddio vddio vssio
|  abut_ncal_vddio[3] - vddio
|  abut_ncal_vddio[4] - vssio vddio vddio
|  abut_ncal_vddio[5] - vddio vddio vssio
|  abut_ncal_vddio[6] - vddio
|  abut_pcal_vddio[1] - vssio
|  abut_pcal_vddio[2] - vddio vssio vddio
|  abut_pcal_vddio[3] - vssio
|  abut_pcal_vddio[4] - vssio
|  abut_pcal_vddio[5] - vddio vssio vddio
|  abut_pcal_vddio[6] - vssio
|  ipp_do_1p8v - ipp_do_1p8v
|  ipp_dse_lv[0] - 0
|  ipp_dse_lv[1] - vdd_lv
|  ipp_eftd_lv - NC
|  ipp_ina_mux_vddio - NC
|  ipp_ina_mux_vddio[0] - NC
|  ipp_ina_mux_vddio[1] - NC
|  ipp_ina_r0_vddio - NC
|  ipp_ina_r0a_vddio - NC
|  ipp_ina_r0b_vddio - NC
|  ipp_ina_r0c_vddio - NC
|  ipp_ina_r0d_vddio - NC
|  ipp_ina_r0e_vddio - NC
|  ipp_ina_r0f_vddio - NC
|  ipp_ina_r300_vddio - NC
|  ipp_ina_r300a_vddio - NC
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Model_type I/O
Polarity   Non-Inverting
Enable   Active-High
Vinl =   0.5400V
Vinh =   1.2600V
Vmeas =  0.9000V
Cref =   30.0000pF
Rref =   1.0000M
Vref =   1.8000V
C_comp   1.7515pF   1.7218pF   1.7928pF
|C_comp_pullup   0.7565pF   0.8222pF   0.7000pF
|C_comp_pulldown   0.8811pF   0.8516pF   0.9106pF
[Model Spec]
| variable   typ   min   max
Vinh   1.2600V   1.1970V   1.3860V
Vinl   0.5400V   0.5130V   0.5940V
[Temperature Range]   25.0000   0.1250k   -40.0000
[Voltage Range]   1.8000V   1.7100V   1.9800V
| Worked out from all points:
|   slope of the pulldown table from 0 to 0.27 V, typ, clamps not added: 23.6 ohm
|   slope of the pullup table from 0 to 0.27 V, typ, clamps not added: 29.3 ohm
|   GND clamp passes 1 mA (typ) near -0.78 V on its own axis
|   POWER clamp passes 1 mA (typ) near -0.53 V on its own axis
|   rising waveform, R_fixture 0.1170k, V_fixture 0.0: 20-80 % time 15ns typ, 29ns min, 7.66ns max; typ from 0 V to 1.43 V
|   rising waveform, R_fixture 0.1170k, V_fixture 1.8000: 20-80 % time 513ps typ, 615ps min, 501ps max; typ from 0.307 V to 1.8 V
|   falling waveform, R_fixture 0.1170k, V_fixture 0.0: 20-80 % time 511ps typ, 634ps min, 458ps max; typ from 1.43 V to 0 V
|   falling waveform, R_fixture 0.1170k, V_fixture 1.8000: 20-80 % time 12.8ns typ, 25.5ns min, 6.47ns max; typ from 1.8 V to 0.307 V
[Pulldown]
|Voltage   I(typ)   I(min)   I(max)
-1.98V    -90.09mA   -66.35mA   -115.5mA
-1.44V    -71.75mA   -51.46mA   -96.32mA
-960mV    -50.89mA   -34.36mA   -71.46mA
180mV     8.022mA    4.974mA    12.66mA
480mV     17.96mA    11.14mA    28.86mA
780mV     23.75mA    14.73mA    39.1mA
1.2V      25.92mA    16.08mA    43.96mA
2.58V     26.28mA    14.91mA    44.75mA
2.82V     23.17mA    14.57mA    44.78mA
2.94V     23.1mA     14.56mA    43.77mA
3.06V     23.08mA    14.57mA    38.82mA
3.96V     23.26mA    14.67mA    38.81mA
[Pullup]
|Voltage   I(typ)   I(min)   I(max)
-1.98V    2.336mA    1.052mA    5.673mA
-1.08V    8.21mA     3.673mA    12.52mA
-1.02V    8.847mA    4.048mA    25.01mA
-960mV    15.85mA    4.437mA    41.87mA
-900mV    26.16mA    5.212mA    44.99mA
-840mV    30.93mA    8.666mA    43.74mA
-780mV    30.97mA    13.31mA    41.91mA
-600mV    25.81mA    17.68mA    34.83mA
240mV     -8.314mA   -5.805mA   -11.95mA
900mV     -21.61mA   -14.82mA   -32.73mA
1.68V     -24.38mA   -16.42mA   -38.69mA
3.96V     -25.52mA   -17.15mA   -40.52mA
[GND_clamp]
|Voltage   I(typ)   I(min)   I(max)
-1.98V    -1.571A    -1.243A    -2.046A
-1.14V    -296.8mA   -307.7mA   -291.9mA
-1.08V    -217.1mA   -250.6mA   -183.3mA
-1.02V    -142mA     -195.3mA   -87.29mA
-960mV    -75.42mA   -142.6mA   -21.4mA
-900mV    -26.21mA   -93.87mA   -2.23mA
-840mV    -4.776mA   -51.84mA   -446.5uA
-780mV    -725.4uA   -21.22mA   -243.9uA
-720mV    -200uA     -5.88mA    -159.3uA
-660mV    -98.47uA   -1.291mA   -98.82uA
-420mV    -3.926uA   -10.95uA   -2.45uA
3.96V     0A         0A         0A
[POWER_clamp]
|Voltage   I(typ)   I(min)   I(max)
-1.98V    13.51A     13.25A     14.01A
-1.2V     3.414A     4.356A     2.802A
-1.14V    2.644A     3.675A     1.949A
-1.08V    1.876A     2.995A     1.103A
-1.02V    1.113A     2.317A     397.9mA
-960mV    462.1mA    1.641A     75.38mA
-900mV    117mA      972.3mA    21.31mA
-840mV    26.38mA    432.6mA    13.76mA
-780mV    10.65mA    139.4mA    9.996mA
-720mV    6.506mA    38.48mA    6.892mA
-660mV    4.142mA    12.01mA    4.303mA
3.96V     0A         0A         0A
[Ramp]
| variable   typ   min   max
dV/dt_r  0.8548/14.9612n   0.7295/28.9997n   1.0105/7.6484n
dV/dt_f  0.8955/12.7689n   0.7514/25.4836n   1.0571/6.4695n
R_load = 0.1170k
[Rising Waveform]
R_fixture= 0.1170k
V_fixture= 0.0
V_fixture_min= 0.0
V_fixture_max= 0.0
|time   V(typ)   V(min)   V(max)
0s        426.8pV    187.1nV    11.16pV
10.59ns   -140.7uV   -66.37uV   15.38mV
12.81ns   -22.08uV   -65.27uV   195.3mV
21.88ns   117.8mV    408.9uV    1.373V
31.89ns   702.3mV    44.99mV    1.609V
38.43ns   1.072V     150.6mV    1.644V
44.83ns   1.242V     303.6mV    1.661V
65.26ns   1.375V     867.3mV    1.68V
80.8ns    1.403V     1.06V      1.683V
207.6ns   1.425V     1.216V     1.684V
[Rising Waveform]
R_fixture= 0.1170k
V_fixture= 1.8000
V_fixture_min= 1.7100
V_fixture_max= 1.9800
|time   V(typ)   V(min)   V(max)
0s        307.4mV    455.1mV    218.1mV
1.352ns   309mV      455.1mV    300.4mV
1.464ns   313.7mV    455mV      464.9mV
1.708ns   345.9mV    454.8mV    1.34V
2.13ns    784.2mV    465.1mV    1.702V
2.375ns   1.335V     491.7mV    1.762V
2.772ns   1.605V     621.7mV    1.835V
3.543ns   1.689V     1.496V     1.938V
4.714ns   1.769V     1.647V     1.973V
207.6ns   1.8V       1.71V      1.98V
[Falling Waveform]
R_fixture= 0.1170k
V_fixture= 0.0
V_fixture_min= 0.0
V_fixture_max= 0.0
|time   V(typ)   V(min)   V(max)
0s        1.425V     1.219V     1.684V
1.229ns   1.425V     1.219V     1.603V
1.36ns    1.418V     1.22V      1.428V
1.67ns    1.356V     1.22V      552.9mV
2.031ns   880.9mV    1.203V     248mV
2.51ns    229.3mV    1.078V     190.3mV
3.109ns   94.17mV    364mV      107.5mV
3.511ns   108mV      141mV      73.31mV
5.694ns   25.49mV    47.48mV    9.927mV
207.6ns   151.6nV    2.507uV    20.62nV
[Falling Waveform]
R_fixture= 0.1170k
V_fixture= 1.8000
V_fixture_min= 1.7100
V_fixture_max= 1.9800
|time   V(typ)   V(min)   V(max)
0s        1.8V       1.71V      1.98V
9.817ns   1.8V       1.709V     1.903V
12.08ns   1.799V     1.71V      1.668V
19.37ns   1.644V     1.707V     508.8mV
27.33ns   1.118V     1.64V      293mV
34.3ns    632.1mV    1.504V     255.2mV
39.3ns    483.6mV    1.369V     242.2mV
58.07ns   357.6mV    774.9mV    224.1mV
72.27ns   331.8mV    601.5mV    220.4mV
207.6ns   307.4mV    457.6mV    218.1mV
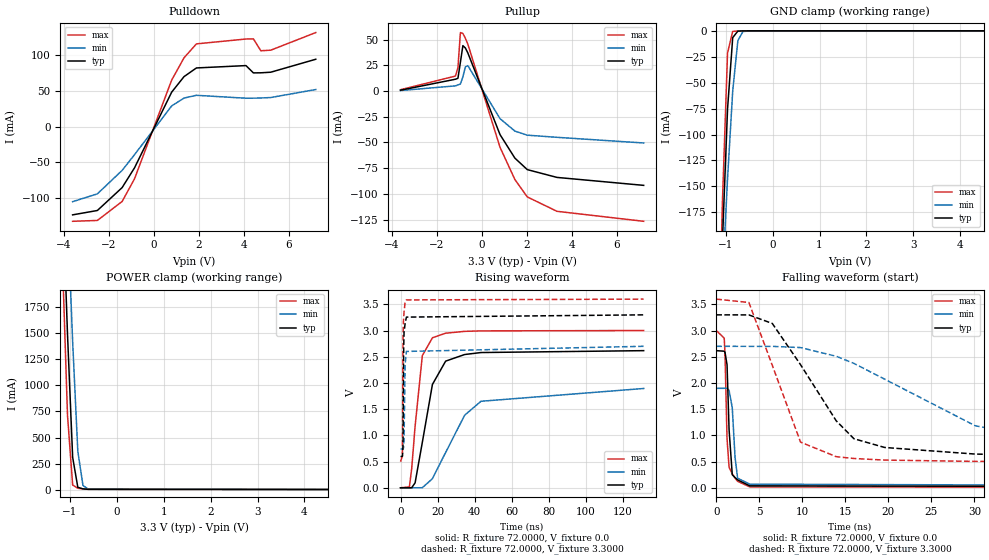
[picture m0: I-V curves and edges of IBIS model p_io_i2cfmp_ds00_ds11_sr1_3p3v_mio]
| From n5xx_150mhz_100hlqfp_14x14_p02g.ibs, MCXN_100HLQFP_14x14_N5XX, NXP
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[Model] p_io_i2cfmp_ds00_ds11_sr1_3p3v_mio
|   Model p_io_i2cfmp_ds00_ds11_sr1_3p3v_mio
| This model was characterised for following simulation conditions:
| External (pad) voltage:
|   - Typ: 3.3V,   - Min: 2.7V,   - Max: 3.6V
| Library cells for typ/min/max conditions are connected as defined below:
|  pad - External Pad
|  ipp_do_lv - Core Input
|  ipp_obe_lv - Output Buffer Enable
|  IOGC - NC
|  REFH3V3 - REFH3V3
|  REFL3V3 - REFL3V3
|  ZI - NC
|  abut_ncal_vddio[1] - vddio
|  abut_ncal_vddio[2] - vddio
|  abut_ncal_vddio[3] - vssio
|  abut_ncal_vddio[4] - vddio
|  abut_ncal_vddio[5] - vddio
|  abut_ncal_vddio[6] - vssio
|  abut_pcal_vddio[1] - vssio
|  abut_pcal_vddio[2] - vssio
|  abut_pcal_vddio[3] - vddio
|  abut_pcal_vddio[4] - vssio
|  abut_pcal_vddio[5] - vssio
|  abut_pcal_vddio[6] - vddio
|  ipp_do_1p8v - ipp_do_1p8v
|  ipp_dse_lv[0] - 0
|  ipp_dse_lv[1] - vdd_lv
|  ipp_eftd_lv - NC
|  ipp_ina_mux_vddio - NC
|  ipp_ina_mux_vddio[0] - NC
|  ipp_ina_mux_vddio[1] - NC
|  ipp_ina_r0_vddio - NC
|  ipp_ina_r0a_vddio - NC
|  ipp_ina_r0b_vddio - NC
|  ipp_ina_r0c_vddio - NC
|  ipp_ina_r0d_vddio - NC
|  ipp_ina_r0e_vddio - NC
|  ipp_ina_r0f_vddio - NC
|  ipp_ina_r300_vddio - NC
|  ipp_ina_r300a_vddio - NC
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Model_type I/O
Polarity   Non-Inverting
Enable   Active-High
Vinl =   0.9900V
Vinh =   2.3100V
Vmeas =  1.6500V
Cref =   30.0000pF
Rref =   1.0000M
Vref =   3.3000V
C_comp   1.7403pF   1.7015pF   1.7922pF
|C_comp_pullup   0.6942pF   0.7580pF   0.6571pF
|C_comp_pulldown   0.9328pF   0.9177pF   0.9318pF
[Model Spec]
| variable   typ   min   max
Vinh   2.3100V   1.8900V   2.5200V
Vinl   0.9900V   0.8100V   1.0800V
[Temperature Range]   25.0000   0.1250k   -40.0000
[Voltage Range]   3.3000V   2.7000V   3.6000V
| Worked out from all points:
|   slope of the pulldown table from 0 to 0.495 V, typ, clamps not added: 15.5 ohm
|   slope of the pullup table from 0 to 0.495 V, typ, clamps not added: 18.1 ohm
|   GND clamp passes 1 mA (typ) near -0.75 V on its own axis
|   POWER clamp passes 1 mA (typ) near -0.52 V on its own axis
|   rising waveform, R_fixture 72.0000, V_fixture 0.0: 20-80 % time 7.77ns typ, 17.3ns min, 4.65ns max; typ from 0 V to 2.62 V
|   rising waveform, R_fixture 72.0000, V_fixture 3.3000: 20-80 % time 325ps typ, 396ps min, 304ps max; typ from 0.595 V to 3.3 V
|   falling waveform, R_fixture 72.0000, V_fixture 0.0: 20-80 % time 353ps typ, 433ps min, 322ps max; typ from 2.62 V to 0 V
|   falling waveform, R_fixture 72.0000, V_fixture 3.3000: 20-80 % time 6.29ns typ, 14.2ns min, 3.78ns max; typ from 3.3 V to 0.595 V
[Pulldown]
|Voltage   I(typ)   I(min)   I(max)
-3.6V     -123.3mA   -104.9mA   -132.3mA
-2.5V     -117.2mA   -93.96mA   -131.1mA
-1.4V     -85.23mA   -61.2mA    -104.6mA
-850mV    -57.62mA   -39.24mA   -72.95mA
800mV     48.07mA    28.85mA    64.9mA
1.35V     69.8mA     39.82mA    96.11mA
1.9V      81.89mA    43.68mA    115.5mA
4.1V      85.18mA    39.6mA     122.3mA
4.43V     74.97mA    39.7mA     122.5mA
4.76V     75.1mA     39.92mA    105.9mA
5.2V      75.92mA    40.55mA    106.7mA
7.2V      94.03mA    51.75mA    131.3mA
[Pullup]
|Voltage   I(typ)   I(min)   I(max)
-3.6V     831.4uA    494.8uA    1.303mA
-1.16V    11.48mA    5.019mA    14.58mA
-1.05V    12.37mA    5.923mA    22.69mA
-940mV    27.99mA    6.853mA    56.83mA
-830mV    44.12mA    13.78mA    55.94mA
-720mV    41.83mA    23.48mA    51.32mA
-610mV    37.03mA    24.67mA    45.59mA
820mV     -42.36mA   -26.86mA   -54.73mA
1.48V     -65.21mA   -38.93mA   -86.04mA
2.03V     -76.37mA   -42.9mA    -102.9mA
3.35V     -83.95mA   -44.98mA   -116.9mA
7.2V      -91.67mA   -50.49mA   -126.6mA
[GND_clamp]
|Voltage   I(typ)   I(min)   I(max)
-3.6V     -4.377A    -3.283A    -5.855A
-1.18V    -351.7mA   -346.5mA   -367.9mA
-1.07V    -204.2mA   -241.2mA   -166.2mA
-960mV    -75.42mA   -142.6mA   -21.4mA
-850mV    -6.575mA   -58.21mA   -529.8uA
-740mV    -281.6uA   -9.383mA   -183.8uA
-630mV    -73.66uA   -605.1uA   -74.76uA
-410mV    -3.148uA   -9.219uA   -1.868uA
7.2V      0A         0A         0A
[POWER_clamp]
|Voltage   I(typ)   I(min)   I(max)
-3.6V     34.56A     31.8A      37.41A
-1.16V    2.902A     3.904A     2.233A
-1.05V    1.495A     2.658A     715.5mA
-940mV    310.6mA    1.419A     44.07mA
-830mV    22.38mA    368.3mA    13.28mA
-720mV    6.713mA    39.84mA    7.005mA
-610mV    2.702mA    5.591mA    2.612mA
7.2V      0A         0A         0A
[Ramp]
| variable   typ   min   max
dV/dt_r  1.5701/7.7662n   1.1371/17.2397n   1.8004/4.6507n
dV/dt_f  1.6231/6.2946n   1.1745/14.1914n   1.8609/3.7800n
R_load = 72.0000
[Rising Waveform]
R_fixture= 72.0000
V_fixture= 0.0
V_fixture_min= 0.0
V_fixture_max= 0.0
|time   V(typ)   V(min)   V(max)
0s        1.745nV    147.2nV    5.779nV
4.789ns   -307.3uV   -1.122mV   17.06mV
6.028ns   1.551mV    -160uV     361.5mV
7.876ns   94.3mV     -114.1uV   1.174V
11.78ns   866.3mV    1.766mV    2.521V
17.24ns   1.972V     174mV      2.863V
24.38ns   2.417V     674mV      2.95V
34.64ns   2.543V     1.385V     2.985V
43.5ns    2.581V     1.651V     2.994V
131.4ns   2.617V     1.895V     3.001V
[Rising Waveform]
R_fixture= 72.0000
V_fixture= 3.3000
V_fixture_min= 2.7000
V_fixture_max= 3.6000
|time   V(typ)   V(min)   V(max)
0s        594.8mV    740.1mV    498.6mV
1.011ns   600.1mV    740.1mV    611.2mV
1.078ns   612mV      740.1mV    828.7mV
1.357ns   838.8mV    741.6mV    2.834V
1.532ns   1.92V      755.8mV    3.138V
1.687ns   2.619V     791.3mV    3.243V
1.903ns   2.966V     904.6mV    3.355V
2.466ns   3.132V     2.35V      3.532V
3.178ns   3.257V     2.602V     3.585V
131.4ns   3.3V       2.7V       3.6V
[Falling Waveform]
R_fixture= 72.0000
V_fixture= 0.0
V_fixture_min= 0.0
V_fixture_max= 0.0
|time   V(typ)   V(min)   V(max)
0s        2.617V     1.899V     3.001V
923.3ps   2.607V     1.899V     2.856V
1.012ns   2.586V     1.9V       2.559V
1.25ns    2.35V      1.896V     934.9mV
1.487ns   1.111V     1.859V     392.3mV
1.858ns   250.4mV    1.526V     267.2mV
2.182ns   196.3mV    583.4mV    185.6mV
2.479ns   151.8mV    183.9mV    125mV
3.886ns   38.65mV    70.53mV    19.03mV
131.4ns   149.8nV    3.619uV    14.93nV
[Falling Waveform]
R_fixture= 72.0000
V_fixture= 3.3000
V_fixture_min= 2.7000
V_fixture_max= 3.6000
|time   V(typ)   V(min)   V(max)
0s        3.3V       2.7V       3.6V
3.79ns    3.299V     2.699V     3.536V
6.509ns   3.136V     2.699V     2.338V
9.793ns   2.35V      2.676V     872.7mV
13.94ns   1.279V     2.51V      595.1mV
16ns      937.1mV    2.374V     560mV
19.57ns   770.2mV    2.073V     529.7mV
30.1ns    644.5mV    1.184V     504.7mV
38.39ns   617.9mV    943mV      500.7mV
131.4ns   594.8mV    742.6mV    498.6mV
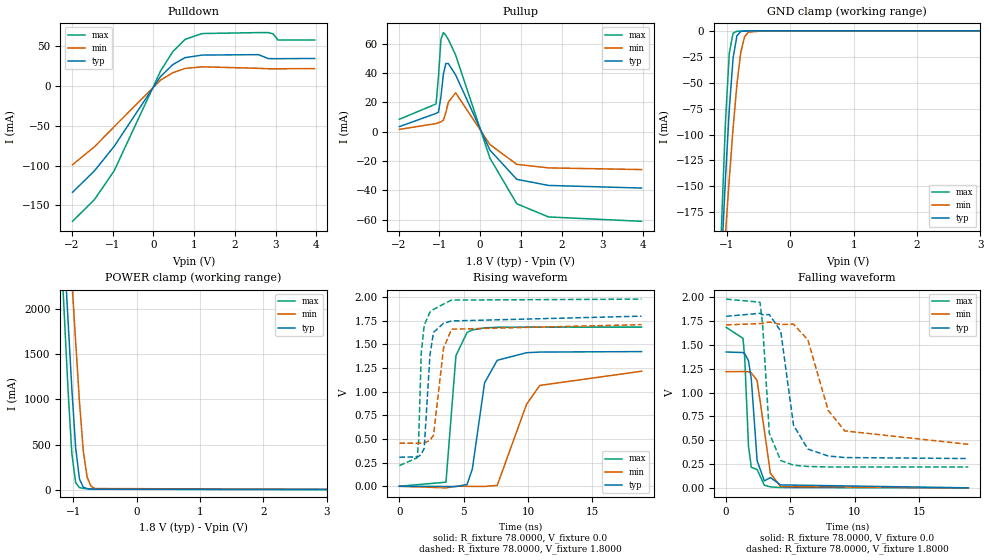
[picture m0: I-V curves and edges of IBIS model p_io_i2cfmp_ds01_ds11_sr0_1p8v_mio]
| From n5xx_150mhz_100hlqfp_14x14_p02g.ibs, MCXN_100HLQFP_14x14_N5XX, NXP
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[Model] p_io_i2cfmp_ds01_ds11_sr0_1p8v_mio
|   Model p_io_i2cfmp_ds01_ds11_sr0_1p8v_mio
| This model was characterised for following simulation conditions:
| External (pad) voltage:
|   - Typ: 1.8V,   - Min: 1.71V,   - Max: 1.98V
| Library cells for typ/min/max conditions are connected as defined below:
|  pad - External Pad
|  ipp_do_lv - Core Input
|  ipp_obe_lv - Output Buffer Enable
|  IOGC - NC
|  REFH3V3 - REFH3V3
|  REFL3V3 - REFL3V3
|  ZI - NC
|  abut_ncal_vddio[1] - vssio vddio vddio
|  abut_ncal_vddio[2] - vddio vddio vssio
|  abut_ncal_vddio[3] - vddio
|  abut_ncal_vddio[4] - vssio vddio vddio
|  abut_ncal_vddio[5] - vddio vddio vssio
|  abut_ncal_vddio[6] - vddio
|  abut_pcal_vddio[1] - vssio
|  abut_pcal_vddio[2] - vddio vssio vddio
|  abut_pcal_vddio[3] - vssio
|  abut_pcal_vddio[4] - vssio
|  abut_pcal_vddio[5] - vddio vssio vddio
|  abut_pcal_vddio[6] - vssio
|  ipp_do_1p8v - ipp_do_1p8v
|  ipp_dse_lv[0] - vdd_lv
|  ipp_dse_lv[1] - vdd_lv
|  ipp_eftd_lv - NC
|  ipp_ina_mux_vddio - NC
|  ipp_ina_mux_vddio[0] - NC
|  ipp_ina_mux_vddio[1] - NC
|  ipp_ina_r0_vddio - NC
|  ipp_ina_r0a_vddio - NC
|  ipp_ina_r0b_vddio - NC
|  ipp_ina_r0c_vddio - NC
|  ipp_ina_r0d_vddio - NC
|  ipp_ina_r0e_vddio - NC
|  ipp_ina_r0f_vddio - NC
|  ipp_ina_r300_vddio - NC
|  ipp_ina_r300a_vddio - NC
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Model_type I/O
Polarity   Non-Inverting
Enable   Active-High
Vinl =   0.5400V
Vinh =   1.2600V
Vmeas =  0.9000V
Cref =   30.0000pF
Rref =   1.0000M
Vref =   1.8000V
C_comp   1.7515pF   1.7218pF   1.7928pF
|C_comp_pullup   0.7554pF   0.8211pF   0.6990pF
|C_comp_pulldown   0.8822pF   0.8527pF   0.9116pF
[Model Spec]
| variable   typ   min   max
Vinh   1.2600V   1.1970V   1.3860V
Vinl   0.5400V   0.5130V   0.5940V
[Temperature Range]   25.0000   0.1250k   -40.0000
[Voltage Range]   1.8000V   1.7100V   1.9800V
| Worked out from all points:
|   slope of the pulldown table from 0 to 0.27 V, typ, clamps not added: 15.8 ohm
|   slope of the pullup table from 0 to 0.27 V, typ, clamps not added: 19.6 ohm
|   GND clamp passes 1 mA (typ) near -0.78 V on its own axis
|   POWER clamp passes 1 mA (typ) near -0.53 V on its own axis
|   rising waveform, R_fixture 78.0000, V_fixture 0.0: 20-80 % time 927ps typ, 1.72ns min, 517ps max; typ from 0 V to 1.43 V
|   rising waveform, R_fixture 78.0000, V_fixture 1.8000: 20-80 % time 372ps typ, 506ps min, 330ps max; typ from 0.308 V to 1.8 V
|   falling waveform, R_fixture 78.0000, V_fixture 0.0: 20-80 % time 451ps typ, 620ps min, 353ps max; typ from 1.43 V to 0 V
|   falling waveform, R_fixture 78.0000, V_fixture 1.8000: 20-80 % time 938ps typ, 1.79ns min, 481ps max; typ from 1.8 V to 0.308 V
[Pulldown]
|Voltage   I(typ)   I(min)   I(max)
-1.98V    -133.6mA   -98.95mA   -170.1mA
-1.44V    -106.5mA   -76.26mA   -142.6mA
-960mV    -75.87mA   -51.23mA   -106.7mA
180mV     12.03mA    7.458mA    18.98mA
480mV     26.93mA    16.71mA    43.26mA
780mV     35.63mA    22.1mA     58.63mA
1.2V      38.89mA    24.13mA    65.95mA
2.58V     39.42mA    22.23mA    67.13mA
2.82V     34.46mA    21.68mA    67.18mA
2.94V     34.35mA    21.68mA    65.63mA
3.06V     34.33mA    21.68mA    57.74mA
3.96V     34.62mA    21.85mA    57.75mA
[Pullup]
|Voltage   I(typ)   I(min)   I(max)
-1.98V    3.472mA    1.574mA    8.476mA
-1.08V    12.47mA    5.549mA    18.91mA
-1.02V    13.37mA    6.125mA    37.75mA
-960mV    23.91mA    6.725mA    62.91mA
-900mV    39.34mA    7.86mA     67.5mA
-840mV    46.42mA    13.06mA    65.6mA
-780mV    46.46mA    20.01mA    62.87mA
-600mV    38.71mA    26.52mA    52.24mA
240mV     -12.47mA   -8.707mA   -17.91mA
900mV     -32.42mA   -22.22mA   -49.08mA
1.68V     -36.57mA   -24.63mA   -58.03mA
3.96V     -38.36mA   -25.77mA   -60.99mA
[GND_clamp]
|Voltage   I(typ)   I(min)   I(max)
-1.98V    -1.571A    -1.243A    -2.046A
-1.14V    -296.8mA   -307.7mA   -291.9mA
-1.08V    -217.1mA   -250.6mA   -183.3mA
-1.02V    -142mA     -195.3mA   -87.29mA
-960mV    -75.42mA   -142.6mA   -21.4mA
-900mV    -26.21mA   -93.87mA   -2.23mA
-840mV    -4.776mA   -51.84mA   -446.5uA
-780mV    -725.4uA   -21.22mA   -243.9uA
-720mV    -200uA     -5.88mA    -159.3uA
-660mV    -98.47uA   -1.291mA   -98.82uA
-420mV    -3.926uA   -10.95uA   -2.45uA
3.96V     0A         0A         0A
[POWER_clamp]
|Voltage   I(typ)   I(min)   I(max)
-1.98V    13.51A     13.25A     14.01A
-1.2V     3.414A     4.356A     2.802A
-1.14V    2.644A     3.675A     1.949A
-1.08V    1.876A     2.995A     1.103A
-1.02V    1.113A     2.317A     397.9mA
-960mV    462.1mA    1.641A     75.38mA
-900mV    117mA      972.3mA    21.31mA
-840mV    26.38mA    432.6mA    13.76mA
-780mV    10.65mA    139.4mA    9.996mA
-720mV    6.506mA    38.48mA    6.892mA
-660mV    4.142mA    12.01mA    4.303mA
3.96V     0A         0A         0A
[Ramp]
| variable   typ   min   max
dV/dt_r  0.8548/0.9273n   0.7302/1.7242n   1.0104/0.5174n
dV/dt_f  0.8955/0.9383n   0.7520/1.7889n   1.0570/0.4811n
R_load = 78.0000
[Rising Waveform]
R_fixture= 78.0000
V_fixture= 0.0
V_fixture_min= 0.0
V_fixture_max= 0.0
|time   V(typ)   V(min)   V(max)
0s        310.7pV    125.7nV    8.6pV
3.624ns   -2.226mV   -16.88mV   43.22mV
4.4ns     -3.856mV   697.5uV    1.382V
5.264ns   19.47mV    -40.52uV   1.628V
5.676ns   183.5mV    -1.956mV   1.654V
6.625ns   1.094V     -2.194mV   1.676V
7.61ns    1.333V     9.722mV    1.682V
9.893ns   1.413V     868.1mV    1.684V
10.92ns   1.42V      1.067V     1.684V
18.83ns   1.425V     1.217V     1.684V
[Rising Waveform]
R_fixture= 78.0000
V_fixture= 1.8000
V_fixture_min= 1.7100
V_fixture_max= 1.9800
|time   V(typ)   V(min)   V(max)
0s        307.5mV    455.1mV    218.3mV
1.388ns   310.4mV    455.1mV    301.9mV
1.498ns   315.6mV    455mV      479mV
1.701ns   337.2mV    455mV      1.403V
1.932ns   402.7mV    457.5mV    1.703V
2.376ns   1.384V     487.1mV    1.842V
2.657ns   1.629V     539.4mV    1.871V
3.436ns   1.725V     1.462V     1.928V
4.059ns   1.749V     1.662V     1.97V
18.83ns   1.8V       1.71V      1.98V
[Falling Waveform]
R_fixture= 78.0000
V_fixture= 0.0
V_fixture_min= 0.0
V_fixture_max= 0.0
|time   V(typ)   V(min)   V(max)
0s        1.425V     1.219V     1.684V
1.308ns   1.42V      1.22V      1.569V
1.444ns   1.407V     1.22V      1.358V
1.736ns   1.333V     1.218V     435.8mV
1.954ns   1.142V     1.206V     216.1mV
2.405ns   285.7mV    1.126V     192mV
2.968ns   72.53mV    603.2mV    27.76mV
3.437ns   108.5mV    153.8mV    10.48mV
4.222ns   31.19mV    14.67mV    3.572mV
18.83ns   1.628uV    26.25uV    79.9nV
[Falling Waveform]
R_fixture= 78.0000
V_fixture= 1.8000
V_fixture_min= 1.7100
V_fixture_max= 1.9800
|time   V(typ)   V(min)   V(max)
0s        1.8V       1.71V      1.98V
2.628ns   1.831V     1.723V     1.948V
2.832ns   1.816V     1.726V     1.718V
3.356ns   1.818V     1.74V      573.4mV
4.24ns    1.645V     1.714V     287mV
5.235ns   658.4mV    1.717V     237.9mV
6.353ns   407mV      1.554V     224.2mV
7.926ns   334.8mV    814.6mV    219.6mV
9.218ns   318mV      597.6mV    218.7mV
18.83ns   307.5mV    456.7mV    218.3mV
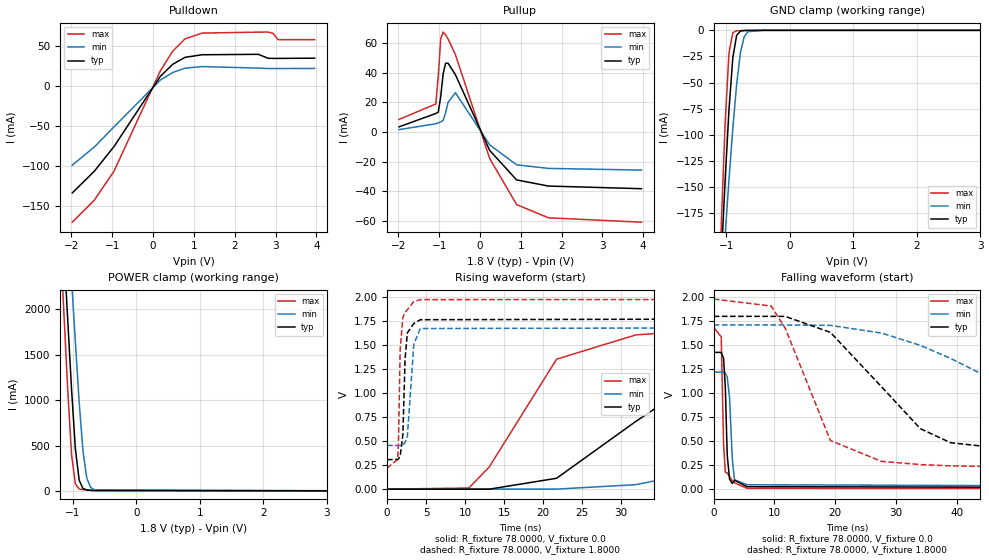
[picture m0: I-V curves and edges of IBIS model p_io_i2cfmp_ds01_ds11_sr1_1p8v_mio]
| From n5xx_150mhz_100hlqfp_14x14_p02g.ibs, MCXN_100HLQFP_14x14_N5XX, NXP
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[Model] p_io_i2cfmp_ds01_ds11_sr1_1p8v_mio
|   Model p_io_i2cfmp_ds01_ds11_sr1_1p8v_mio
| This model was characterised for following simulation conditions:
| External (pad) voltage:
|   - Typ: 1.8V,   - Min: 1.71V,   - Max: 1.98V
| Library cells for typ/min/max conditions are connected as defined below:
|  pad - External Pad
|  ipp_do_lv - Core Input
|  ipp_obe_lv - Output Buffer Enable
|  IOGC - NC
|  REFH3V3 - REFH3V3
|  REFL3V3 - REFL3V3
|  ZI - NC
|  abut_ncal_vddio[1] - vssio vddio vddio
|  abut_ncal_vddio[2] - vddio vddio vssio
|  abut_ncal_vddio[3] - vddio
|  abut_ncal_vddio[4] - vssio vddio vddio
|  abut_ncal_vddio[5] - vddio vddio vssio
|  abut_ncal_vddio[6] - vddio
|  abut_pcal_vddio[1] - vssio
|  abut_pcal_vddio[2] - vddio vssio vddio
|  abut_pcal_vddio[3] - vssio
|  abut_pcal_vddio[4] - vssio
|  abut_pcal_vddio[5] - vddio vssio vddio
|  abut_pcal_vddio[6] - vssio
|  ipp_do_1p8v - ipp_do_1p8v
|  ipp_dse_lv[0] - vdd_lv
|  ipp_dse_lv[1] - vdd_lv
|  ipp_eftd_lv - NC
|  ipp_ina_mux_vddio - NC
|  ipp_ina_mux_vddio[0] - NC
|  ipp_ina_mux_vddio[1] - NC
|  ipp_ina_r0_vddio - NC
|  ipp_ina_r0a_vddio - NC
|  ipp_ina_r0b_vddio - NC
|  ipp_ina_r0c_vddio - NC
|  ipp_ina_r0d_vddio - NC
|  ipp_ina_r0e_vddio - NC
|  ipp_ina_r0f_vddio - NC
|  ipp_ina_r300_vddio - NC
|  ipp_ina_r300a_vddio - NC
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Model_type I/O
Polarity   Non-Inverting
Enable   Active-High
Vinl =   0.5400V
Vinh =   1.2600V
Vmeas =  0.9000V
Cref =   30.0000pF
Rref =   1.0000M
Vref =   1.8000V
C_comp   1.7515pF   1.7218pF   1.7928pF
|C_comp_pullup   0.7560pF   0.8218pF   0.6995pF
|C_comp_pulldown   0.8816pF   0.8521pF   0.9111pF
[Model Spec]
| variable   typ   min   max
Vinh   1.2600V   1.1970V   1.3860V
Vinl   0.5400V   0.5130V   0.5940V
[Temperature Range]   25.0000   0.1250k   -40.0000
[Voltage Range]   1.8000V   1.7100V   1.9800V
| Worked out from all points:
|   slope of the pulldown table from 0 to 0.27 V, typ, clamps not added: 15.8 ohm
|   slope of the pullup table from 0 to 0.27 V, typ, clamps not added: 19.6 ohm
|   GND clamp passes 1 mA (typ) near -0.78 V on its own axis
|   POWER clamp passes 1 mA (typ) near -0.53 V on its own axis
|   rising waveform, R_fixture 78.0000, V_fixture 0.0: 20-80 % time 15.1ns typ, 29.2ns min, 7.75ns max; typ from 0 V to 1.43 V
|   rising waveform, R_fixture 78.0000, V_fixture 1.8000: 20-80 % time 375ps typ, 517ps min, 326ps max; typ from 0.308 V to 1.8 V
|   falling waveform, R_fixture 78.0000, V_fixture 0.0: 20-80 % time 407ps typ, 545ps min, 339ps max; typ from 1.43 V to 0 V
|   falling waveform, R_fixture 78.0000, V_fixture 1.8000: 20-80 % time 12.8ns typ, 25.5ns min, 6.53ns max; typ from 1.8 V to 0.308 V
[Pulldown]
|Voltage   I(typ)   I(min)   I(max)
-1.98V    -133.6mA   -98.95mA   -170.1mA
-1.44V    -106.5mA   -76.26mA   -142.6mA
-960mV    -75.87mA   -51.23mA   -106.7mA
180mV     12.03mA    7.458mA    18.98mA
480mV     26.93mA    16.71mA    43.26mA
780mV     35.63mA    22.1mA     58.63mA
1.2V      38.89mA    24.13mA    65.95mA
2.58V     39.42mA    22.23mA    67.13mA
2.82V     34.46mA    21.68mA    67.18mA
2.94V     34.35mA    21.68mA    65.63mA
3.06V     34.33mA    21.68mA    57.74mA
3.96V     34.62mA    21.85mA    57.75mA
[Pullup]
|Voltage   I(typ)   I(min)   I(max)
-1.98V    3.472mA    1.574mA    8.476mA
-1.08V    12.47mA    5.549mA    18.91mA
-1.02V    13.37mA    6.125mA    37.75mA
-960mV    23.91mA    6.725mA    62.91mA
-900mV    39.34mA    7.86mA     67.5mA
-840mV    46.42mA    13.06mA    65.6mA
-780mV    46.46mA    20.01mA    62.87mA
-600mV    38.71mA    26.52mA    52.24mA
240mV     -12.47mA   -8.707mA   -17.91mA
900mV     -32.42mA   -22.22mA   -49.08mA
1.68V     -36.57mA   -24.63mA   -58.03mA
3.96V     -38.36mA   -25.77mA   -60.99mA
[GND_clamp]
|Voltage   I(typ)   I(min)   I(max)
-1.98V    -1.571A    -1.243A    -2.046A
-1.14V    -296.8mA   -307.7mA   -291.9mA
-1.08V    -217.1mA   -250.6mA   -183.3mA
-1.02V    -142mA     -195.3mA   -87.29mA
-960mV    -75.42mA   -142.6mA   -21.4mA
-900mV    -26.21mA   -93.87mA   -2.23mA
-840mV    -4.776mA   -51.84mA   -446.5uA
-780mV    -725.4uA   -21.22mA   -243.9uA
-720mV    -200uA     -5.88mA    -159.3uA
-660mV    -98.47uA   -1.291mA   -98.82uA
-420mV    -3.926uA   -10.95uA   -2.45uA
3.96V     0A         0A         0A
[POWER_clamp]
|Voltage   I(typ)   I(min)   I(max)
-1.98V    13.51A     13.25A     14.01A
-1.2V     3.414A     4.356A     2.802A
-1.14V    2.644A     3.675A     1.949A
-1.08V    1.876A     2.995A     1.103A
-1.02V    1.113A     2.317A     397.9mA
-960mV    462.1mA    1.641A     75.38mA
-900mV    117mA      972.3mA    21.31mA
-840mV    26.38mA    432.6mA    13.76mA
-780mV    10.65mA    139.4mA    9.996mA
-720mV    6.506mA    38.48mA    6.892mA
-660mV    4.142mA    12.01mA    4.303mA
3.96V     0A         0A         0A
[Ramp]
| variable   typ   min   max
dV/dt_r  0.8548/15.0883n   0.7298/29.2276n   1.0104/7.7458n
dV/dt_f  0.8955/12.8277n   0.7517/25.5410n   1.0570/6.5284n
R_load = 78.0000
[Rising Waveform]
R_fixture= 78.0000
V_fixture= 0.0
V_fixture_min= 0.0
V_fixture_max= 0.0
|time   V(typ)   V(min)   V(max)
0s        310.7pV    125.7nV    8.6pV
10.49ns   -128.9uV   -52.16uV   11.7mV
13.1ns    103.1uV    -51.18uV   231.8mV
21.72ns   113.3mV    443.4uV    1.354V
31.88ns   706.7mV    46.88mV    1.607V
38.97ns   1.09V      163.8mV    1.645V
45.43ns   1.248V     320.5mV    1.661V
65.52ns   1.374V     871.1mV    1.679V
81.29ns   1.402V     1.062V     1.683V
215.6ns   1.425V     1.216V     1.684V
[Rising Waveform]
R_fixture= 78.0000
V_fixture= 1.8000
V_fixture_min= 1.7100
V_fixture_max= 1.9800
|time   V(typ)   V(min)   V(max)
0s        307.5mV    455.1mV    218.3mV
1.363ns   309.7mV    455.1mV    308mV
1.468ns   314.8mV    455mV      483.9mV
1.694ns   344mV      454.8mV    1.458V
2.039ns   570.2mV    461.2mV    1.789V
2.318ns   1.356V     485.2mV    1.841V
2.612ns   1.628V     549.5mV    1.869V
3.439ns   1.726V     1.51V      1.955V
4.268ns   1.765V     1.673V     1.974V
215.6ns   1.8V       1.71V      1.98V
[Falling Waveform]
R_fixture= 78.0000
V_fixture= 0.0
V_fixture_min= 0.0
V_fixture_max= 0.0
|time   V(typ)   V(min)   V(max)
0s        1.425V     1.219V     1.684V
1.225ns   1.424V     1.22V      1.587V
1.614ns   1.363V     1.22V      472.4mV
1.906ns   1.052V     1.21V      176mV
2.213ns   354mV      1.168V     170.8mV
2.603ns   103.5mV    950.4mV    129.7mV
3.051ns   58.88mV    311.8mV    89.14mV
3.412ns   92.77mV    97.88mV    65.77mV
5.491ns   25.86mV    46.21mV    8.779mV
215.6ns   93.42nV    1.942uV    12.84nV
[Falling Waveform]
R_fixture= 78.0000
V_fixture= 1.8000
V_fixture_min= 1.7100
V_fixture_max= 1.9800
|time   V(typ)   V(min)   V(max)
0s        1.8V       1.71V      1.98V
9.474ns   1.8V       1.71V      1.907V
11.8ns    1.799V     1.71V      1.672V
19.21ns   1.633V     1.706V     506.5mV
27.64ns   1.066V     1.626V     289.6mV
34.02ns   630.4mV    1.498V     256mV
39.03ns   483.4mV    1.362V     242.7mV
57.5ns    358.5mV    776.7mV    224.4mV
71.53ns   332.4mV    603.2mV    220.7mV
215.6ns   307.6mV    457.1mV    218.3mV
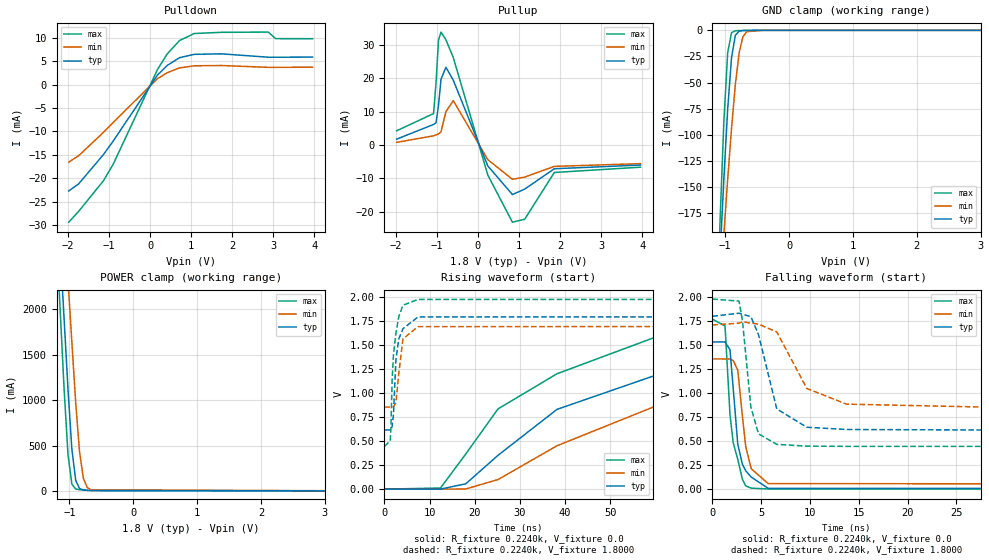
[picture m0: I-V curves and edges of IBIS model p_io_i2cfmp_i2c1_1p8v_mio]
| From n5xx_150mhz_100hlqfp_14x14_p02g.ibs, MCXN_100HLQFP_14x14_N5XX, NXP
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[Model] p_io_i2cfmp_i2c1_1p8v_mio
|   Model p_io_i2cfmp_i2c1_1p8v_mio
| This model was characterised for following simulation conditions:
| External (pad) voltage:
|   - Typ: 1.8V,   - Min: 1.71V,   - Max: 1.98V
| Library cells for typ/min/max conditions are connected as defined below:
|  pad - External Pad
|  ipp_do_lv - Core Input
|  ipp_obe_lv - Output Buffer Enable
|  IOGC - NC
|  REFH3V3 - REFH3V3
|  REFL3V3 - REFL3V3
|  ZI - NC
|  abut_ncal_vddio[1] - vssio vddio vddio
|  abut_ncal_vddio[2] - vddio vddio vssio
|  abut_ncal_vddio[3] - vddio
|  abut_ncal_vddio[4] - vssio vddio vddio
|  abut_ncal_vddio[5] - vddio vddio vssio
|  abut_ncal_vddio[6] - vddio
|  abut_pcal_vddio[1] - vssio
|  abut_pcal_vddio[2] - vddio vssio vddio
|  abut_pcal_vddio[3] - vssio
|  abut_pcal_vddio[4] - vssio
|  abut_pcal_vddio[5] - vddio vssio vddio
|  abut_pcal_vddio[6] - vssio
|  ipp_do_1p8v - ipp_do_1p8v
|  ipp_eftd_lv - NC
|  ipp_i2c_lv - vdd_lv
|  ipp_ina_mux_vddio - NC
|  ipp_ina_mux_vddio[0] - NC
|  ipp_ina_mux_vddio[1] - NC
|  ipp_ina_r0_vddio - NC
|  ipp_ina_r0a_vddio - NC
|  ipp_ina_r0b_vddio - NC
|  ipp_ina_r0c_vddio - NC
|  ipp_ina_r0d_vddio - NC
|  ipp_ina_r0e_vddio - NC
|  ipp_ina_r0f_vddio - NC
|  ipp_ina_r300_vddio - NC
|  ipp_ina_r300a_vddio - NC
|  ipp_ina_r300b_vddio - NC
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Model_type I/O
Polarity   Non-Inverting
Enable   Active-High
Vinl =   0.5400V
Vinh =   1.2600V
Vmeas =  0.9000V
Cref =   30.0000pF
Rref =   1.0000M
Vref =   1.8000V
C_comp   1.7515pF   1.7219pF   1.7929pF
|C_comp_pullup   0.7574pF   0.8231pF   0.7010pF
|C_comp_pulldown   0.8800pF   0.8506pF   0.9095pF
[Model Spec]
| variable   typ   min   max
Vinh   1.2600V   1.1970V   1.3860V
Vinl   0.5400V   0.5130V   0.5940V
[Temperature Range]   25.0000   0.1250k   -40.0000
[Voltage Range]   1.8000V   1.7100V   1.9800V
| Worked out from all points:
|   slope of the pulldown table from 0 to 0.27 V, typ, clamps not added: 94.2 ohm
|   slope of the pullup table from 0 to 0.27 V, typ, clamps not added: 39.1 ohm
|   GND clamp passes 1 mA (typ) near -0.78 V on its own axis
|   POWER clamp passes 1 mA (typ) near -0.53 V on its own axis
|   rising waveform, R_fixture 0.2240k, V_fixture 0.0: 20-80 % time 38ns typ, 47.9ns min, 31.4ns max; typ from 0 V to 1.52 V
|   rising waveform, R_fixture 0.2240k, V_fixture 1.8000: 20-80 % time 1.09ns typ, 1.02ns min, 1.2ns max; typ from 0.616 V to 1.8 V
|   falling waveform, R_fixture 0.2240k, V_fixture 0.0: 20-80 % time 889ps typ, 978ps min, 978ps max; typ from 1.53 V to 0 V
|   falling waveform, R_fixture 0.2240k, V_fixture 1.8000: 20-80 % time 1.69ns typ, 2.81ns min, 951ps max; typ from 1.8 V to 0.616 V
[Pulldown]
|Voltage   I(typ)   I(min)   I(max)
-1.98V    -22.71mA   -16.55mA   -29.37mA
-1.74V    -21.21mA   -15.2mA    -27.08mA
-1.14V    -15mA      -10.25mA   -20.59mA
-900mV    -12.1mA    -8.114mA   -17.06mA
180mV     2.012mA    1.246mA    3.179mA
420mV     4.088mA    2.535mA    6.549mA
720mV     5.743mA    3.561mA    9.405mA
1.08V     6.453mA    4.005mA    10.9mA
1.74V     6.558mA    4.067mA    11.15mA
2.88V     5.839mA    3.678mA    11.2mA
3.06V     5.829mA    3.677mA    9.802mA
3.96V     5.871mA    3.703mA    9.79mA
[Pullup]
|Voltage   I(typ)   I(min)   I(max)
-1.98V    1.753mA    789.2uA    4.254mA
-1.08V    6.153mA    2.753mA    9.394mA
-1.02V    6.639mA    3.034mA    18.73mA
-960mV    11.88mA    3.325mA    31.39mA
-900mV    19.61mA    3.909mA    33.75mA
-780mV    23.23mA    9.977mA    31.44mA
-600mV    19.36mA    13.26mA    26.13mA
240mV     -6.236mA   -4.354mA   -8.961mA
840mV     -14.8mA    -10.24mA   -23.06mA
1.14V     -13.17mA   -9.584mA   -22.17mA
1.86V     -7.096mA   -6.383mA   -8.203mA
3.96V     -5.982mA   -5.561mA   -6.62mA
[GND_clamp]
|Voltage   I(typ)   I(min)   I(max)
-1.98V    -1.571A    -1.243A    -2.046A
-1.14V    -296.8mA   -307.7mA   -291.9mA
-1.08V    -217.1mA   -250.6mA   -183.3mA
-1.02V    -142mA     -195.3mA   -87.29mA
-960mV    -75.42mA   -142.6mA   -21.4mA
-900mV    -26.21mA   -93.87mA   -2.23mA
-840mV    -4.776mA   -51.84mA   -446.5uA
-780mV    -725.4uA   -21.22mA   -243.9uA
-720mV    -200uA     -5.88mA    -159.3uA
-660mV    -98.47uA   -1.291mA   -98.82uA
-420mV    -3.926uA   -10.95uA   -2.45uA
3.96V     0A         0A         0A
[POWER_clamp]
|Voltage   I(typ)   I(min)   I(max)
-1.98V    13.51A     13.25A     14.01A
-1.2V     3.414A     4.356A     2.802A
-1.14V    2.644A     3.675A     1.949A
-1.08V    1.876A     2.995A     1.103A
-1.02V    1.113A     2.317A     397.9mA
-960mV    462.1mA    1.641A     75.38mA
-900mV    117mA      972.3mA    21.31mA
-840mV    26.38mA    432.6mA    13.76mA
-780mV    10.65mA    139.4mA    9.996mA
-720mV    6.506mA    38.48mA    6.892mA
-660mV    4.142mA    12.01mA    4.303mA
3.96V     0A         0A         0A
[Ramp]
| variable   typ   min   max
dV/dt_r  0.9149/38.0295n   0.7991/47.8735n   1.0609/31.3676n
dV/dt_f  0.7103/1.6901n   0.5133/2.8099n   0.9207/0.9506n
R_load = 0.2240k
[Rising Waveform]
R_fixture= 0.2240k
V_fixture= 0.0
V_fixture_min= 0.0
V_fixture_max= 0.0
|time   V(typ)   V(min)   V(max)
0s        1.264nV    596.6nV    30.77pV
12.4ns    568uV      -110.4uV   11.88mV
18ns      55.7mV     1.817mV    366.4mV
25.14ns   352.5mV    99.87mV    836.1mV
38.2ns    831.2mV    452.2mV    1.202V
61.83ns   1.216V     899.2mV    1.616V
87.23ns   1.4V       1.11V      1.73V
137.4ns   1.489V     1.235V     1.76V
243.9ns   1.514V     1.297V     1.765V
1us       1.525V     1.332V     1.768V
[Rising Waveform]
R_fixture= 0.2240k
V_fixture= 1.8000
V_fixture_min= 1.7100
V_fixture_max= 1.9800
|time   V(typ)   V(min)   V(max)
0s        616.1mV    854.4mV    445.6mV
1.28ns    616.8mV    854.5mV    504.5mV
1.433ns   621mV      854.5mV    630mV
1.694ns   651.2mV    854.4mV    1.132V
1.999ns   781.2mV    856.7mV    1.402V
2.546ns   1.353V     902.6mV    1.628V
3.188ns   1.567V     1.214V     1.799V
4.103ns   1.671V     1.565V     1.916V
7.422ns   1.794V     1.693V     1.976V
1us       1.8V       1.71V      1.98V
[Falling Waveform]
R_fixture= 0.2240k
V_fixture= 0.0
V_fixture_min= 0.0
V_fixture_max= 0.0
|time   V(typ)   V(min)   V(max)
0s        1.533V     1.357V     1.771V
1.298ns   1.533V     1.356V     1.7V
1.807ns   1.452V     1.356V     775.1mV
2.135ns   1.049V     1.34V      483.8mV
2.603ns   468.8mV    1.241V     310.8mV
3.072ns   260.6mV    764.6mV    105mV
3.417ns   191.6mV    442.8mV    34.36mV
3.985ns   125.5mV    212.5mV    10.6mV
5.725ns   8.007mV    57.57mV    2.06mV
1us       216nV      1.409uV    25.81nV
[Falling Waveform]
R_fixture= 0.2240k
V_fixture= 1.8000
V_fixture_min= 1.7100
V_fixture_max= 1.9800
|time   V(typ)   V(min)   V(max)
0s        1.8V       1.71V      1.98V
2.732ns   1.833V     1.729V     1.959V
3.088ns   1.822V     1.743V     1.748V
3.942ns   1.797V     1.73V      856.1mV
4.724ns   1.611V     1.719V     576.5mV
6.598ns   835.8mV    1.638V     466.8mV
9.675ns   644.9mV    1.049V     448mV
13.74ns   621.5mV    885.6mV    445.8mV
27.52ns   616.2mV    855.7mV    445.6mV
1us       616.1mV    854.4mV    445.6mV
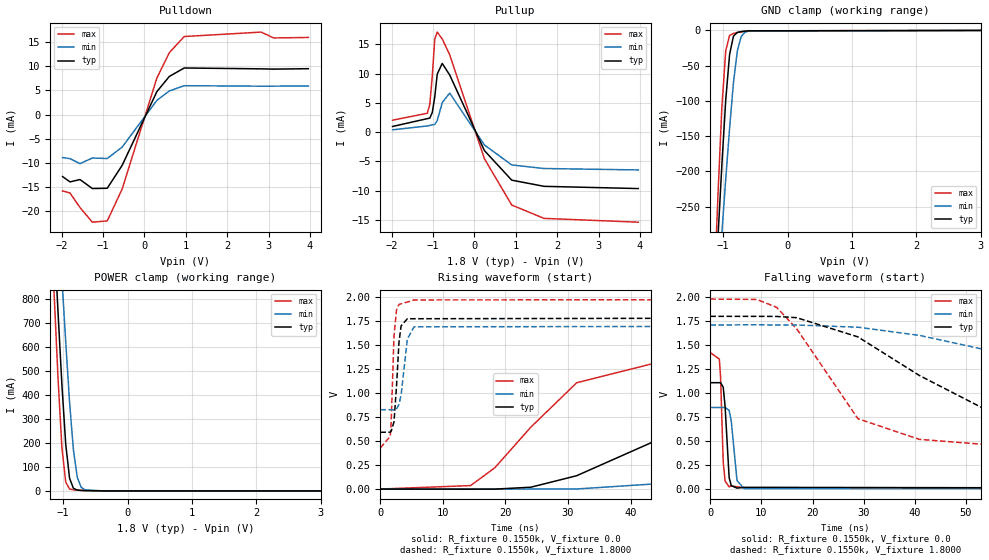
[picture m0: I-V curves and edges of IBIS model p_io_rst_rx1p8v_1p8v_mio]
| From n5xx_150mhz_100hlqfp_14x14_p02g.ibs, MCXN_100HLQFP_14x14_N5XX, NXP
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[Model] p_io_rst_rx1p8v_1p8v_mio
|   Model p_io_rst_rx1p8v_1p8v_mio
| This model was characterised for following simulation conditions:
| External (pad) voltage:
|   - Typ: 1.8V,   - Min: 1.71V,   - Max: 1.98V
| Library cells for typ/min/max conditions are connected as defined below:
|  pad - External Pad
|  ipp_do_lv - Core Input
|  ipp_obe_lv - Output Buffer Enable
|  IOGC - NC
|  REFH3V3 - REFH3V3
|  REFL3V3 - REFL3V3
|  ZI - NC
|  abut_ncal_vddio[1] - vssio vddio vddio
|  abut_ncal_vddio[2] - vddio vddio vssio
|  abut_ncal_vddio[3] - vddio
|  abut_ncal_vddio[4] - vssio vddio vddio
|  abut_ncal_vddio[5] - vddio vddio vssio
|  abut_ncal_vddio[6] - vddio
|  abut_pcal_vddio[1] - vssio
|  abut_pcal_vddio[2] - vddio vssio vddio
|  abut_pcal_vddio[3] - vssio
|  abut_pcal_vddio[4] - vssio
|  abut_pcal_vddio[5] - vddio vssio vddio
|  abut_pcal_vddio[6] - vssio
|  ipp_do_1p8v - ipp_do_1p8v
|  ipp_eftd_lv - NC
|  ipp_ina_mux_vddio - NC
|  ipp_ina_mux_vddio[0] - NC
|  ipp_ina_mux_vddio[1] - NC
|  ipp_ina_r0_vddio - NC
|  ipp_ina_r0a_vddio - NC
|  ipp_ina_r0b_vddio - NC
|  ipp_ina_r0c_vddio - NC
|  ipp_ina_r0d_vddio - NC
|  ipp_ina_r0e_vddio - NC
|  ipp_ina_r0f_vddio - NC
|  ipp_ina_r300_vddio - NC
|  ipp_ina_r300a_vddio - NC
|  ipp_ina_r300b_vddio - NC
|  ipp_ina_r300c_vddio - NC
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Model_type I/O
Polarity   Non-Inverting
Enable   Active-High
Vinl =   0.5400V
Vinh =   1.2600V
Vmeas =  0.9000V
Cref =   30.0000pF
Rref =   1.0000M
Vref =   1.8000V
C_comp   1.3113pF   1.2647pF   1.4205pF
|C_comp_pullup   0.5634pF   0.5967pF   0.5384pF
|C_comp_pulldown   0.6599pF   0.7323pF   0.6352pF
[Model Spec]
| variable   typ   min   max
Vinh   1.2600V   1.1970V   1.3860V
Vinl   0.5400V   0.5130V   0.5940V
[Temperature Range]   25.0000   0.1250k   -40.0000
[Voltage Range]   1.8000V   1.7100V   1.9800V
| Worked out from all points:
|   slope of the pulldown table from 0 to 0.27 V, typ, clamps not added: 62.4 ohm
|   slope of the pullup table from 0 to 0.27 V, typ, clamps not added: 77.5 ohm
|   GND clamp passes 1 mA (typ) near -0.64 V on its own axis
|   POWER clamp passes 1 mA (typ) near -0.63 V on its own axis
|   rising waveform, R_fixture 0.1550k, V_fixture 0.0: 20-80 % time 25.4ns typ, 47ns min, 12.9ns max; typ from 0 V to 1.11 V
|   rising waveform, R_fixture 0.1550k, V_fixture 1.8000: 20-80 % time 632ps typ, 878ps min, 492ps max; typ from 0.592 V to 1.8 V
|   falling waveform, R_fixture 0.1550k, V_fixture 0.0: 20-80 % time 639ps typ, 845ps min, 496ps max; typ from 1.11 V to 0 V
|   falling waveform, R_fixture 0.1550k, V_fixture 1.8000: 20-80 % time 23.6ns typ, 44.7ns min, 11.9ns max; typ from 1.8 V to 0.592 V
[Pulldown]
|Voltage   I(typ)   I(min)   I(max)
-1.98V    -12.82mA   -8.883mA   -15.78mA
-1.8V     -13.92mA   -9.12mA    -16.21mA
-1.56V    -13.43mA   -10.15mA   -19.2mA
-1.26V    -15.29mA   -8.985mA   -22.24mA
-900mV    -15.23mA   -9.091mA   -21.97mA
-540mV    -10.5mA    -6.732mA   -15.4mA
300mV     4.733mA    2.928mA    7.541mA
600mV     7.859mA    4.865mA    12.77mA
960mV     9.606mA    5.947mA    16.1mA
2.82V     9.427mA    5.853mA    17.02mA
3.12V     9.372mA    5.855mA    15.81mA
3.96V     9.458mA    5.904mA    15.91mA
[Pullup]
|Voltage   I(typ)   I(min)   I(max)
-1.98V    970.1uA    399.7uA    2.041mA
-1.14V    2.306mA    1.059mA    3.217mA
-1.08V    2.399mA    1.145mA    4.761mA
-1.02V    3.355mA    1.234mA    9.541mA
-960mV    6.03mA     1.325mA    15.88mA
-900mV    9.91mA     1.972mA    17.07mA
-780mV    11.72mA    5.03mA     15.9mA
-600mV    9.761mA    6.668mA    13.21mA
240mV     -3.146mA   -2.19mA    -4.535mA
900mV     -8.187mA   -5.593mA   -12.43mA
1.68V     -9.242mA   -6.203mA   -14.71mA
3.96V     -9.624mA   -6.445mA   -15.36mA
[GND_clamp]
|Voltage   I(typ)   I(min)   I(max)
-1.98V    -2.029A    -1.716A    -2.516A
-1.14V    -399.2mA   -446.6mA   -369.9mA
-1.08V    -292.8mA   -366.2mA   -232.1mA
-1.02V    -191mA     -287.4mA   -109mA
-960mV    -98.91mA   -211.2mA   -29.36mA
-900mV    -34.26mA   -138.9mA   -7.283mA
-840mV    -8.248mA   -74.31mA   -4.319mA
-780mV    -2.995mA   -29.56mA   -3.112mA
-720mV    -1.791mA   -8.837mA   -2.149mA
-660mV    -1.158mA   -2.642mA   -1.361mA
-600mV    -697.2uA   -1.05mA    -760.6uA
3.96V     0A         0A         0A
[POWER_clamp]
|Voltage   I(typ)   I(min)   I(max)
-1.98V    5.575A     5.314A     6.031A
-1.14V    1.063A     1.433A     822.6mA
-1.08V    748.7mA    1.161A     472.7mA
-1.02V    446mA      889.8mA    183.6mA
-960mV    194.9mA    621.5mA    36.74mA
-900mV    52.34mA    369.1mA    7.81mA
-840mV    10.74mA    169.6mA    4.436mA
-780mV    3.619mA    56.13mA    3.182mA
-720mV    2.073mA    15.03mA    2.194mA
-660mV    1.305mA    4.298mA    1.374mA
-360mV    5.031uA    27.49uA    1.319uA
3.96V     0A         0A         0A
[Ramp]
| variable   typ   min   max
dV/dt_r  0.6652/25.3811n   0.5065/47.0519n   0.8533/12.9143n
dV/dt_f  0.7247/23.5732n   0.5259/44.7499n   0.9321/11.8810n
R_load = 0.1550k
[Rising Waveform]
R_fixture= 0.1550k
V_fixture= 0.0
V_fixture_min= 0.0
V_fixture_max= 0.0
|time   V(typ)   V(min)   V(max)
0s        394.1pV    138.2nV    9.265pV
14.43ns   -1.264mV   -1.194mV   36.03mV
18.31ns   -531.2uV   -892.4uV   222.1mV
24.06ns   19.08mV    -552.8uV   645.2mV
31.39ns   139.1mV    692.7uV    1.108V
45.64ns   551mV      61.17mV    1.342V
60.49ns   893mV      212.8mV    1.395V
84.67ns   1.044V     518.4mV    1.417V
130.1ns   1.099V     768.9mV    1.422V
231.3ns   1.109V     844.1mV    1.422V
[Rising Waveform]
R_fixture= 0.1550k
V_fixture= 1.8000
V_fixture_min= 1.7100
V_fixture_max= 1.9800
|time   V(typ)   V(min)   V(max)
0s        591.8mV    826.8mV    426.6mV
1.598ns   592.8mV    826.9mV    550.9mV
1.747ns   603.2mV    826.8mV    705.5mV
2.192ns   700.6mV    824.4mV    1.596V
2.597ns   1.075V     836.3mV    1.866V
2.984ns   1.527V     880.3mV    1.923V
3.326ns   1.7V       978.4mV    1.931V
4.331ns   1.775V     1.564V     1.949V
5.4ns     1.775V     1.691V     1.971V
231.3ns   1.8V       1.71V      1.98V
[Falling Waveform]
R_fixture= 0.1550k
V_fixture= 0.0
V_fixture_min= 0.0
V_fixture_max= 0.0
|time   V(typ)   V(min)   V(max)
0s        1.109V     850.8mV    1.422V
1.773ns   1.109V     850.8mV    1.355V
2.011ns   1.11V      850.8mV    1.169V
2.531ns   1.062V     850.7mV    282.4mV
2.902ns   858.4mV    851.4mV    83.63mV
3.687ns   120.5mV    820.6mV    24.4mV
4.11ns    35.76mV    705mV      34.26mV
5.229ns   11mV       89.74mV    25.6mV
6.608ns   19.01mV    6.165mV    14.72mV
231.3ns   243.4nV    3.574uV    8.683nV
[Falling Waveform]
R_fixture= 0.1550k
V_fixture= 1.8000
V_fixture_min= 1.7100
V_fixture_max= 1.9800
|time   V(typ)   V(min)   V(max)
0s        1.8V       1.71V      1.98V
9.117ns   1.8V       1.712V     1.976V
12.97ns   1.799V     1.71V      1.894V
16.89ns   1.786V     1.71V      1.671V
28.87ns   1.586V     1.687V     734mV
40.86ns   1.185V     1.602V     518.8mV
54.01ns   824.4mV    1.45V      464.5mV
76.8ns    668.7mV    1.134V     436.9mV
123.1ns   605.8mV    904.6mV    427.4mV
231.3ns   592.2mV    833.6mV    426.6mV
